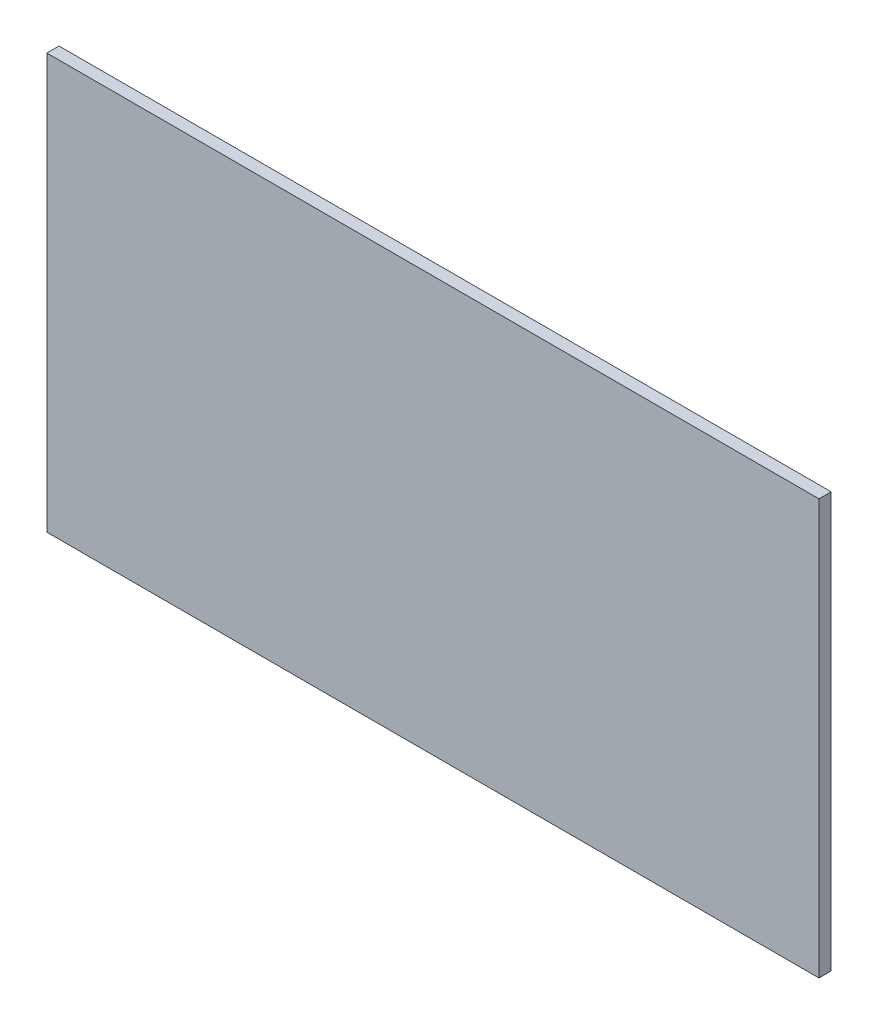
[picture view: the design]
SolidWorks part; units mm, degrees
ref_plane "前视基准面" through (0, 0, 0) normal (0, 0, 1) x (1, 0, 0)
ref_plane "上视基准面" through (0, 0, 0) normal (0, 1, 0) x (1, 0, 0)
ref_plane "右视基准面" through (0, 0, 0) normal (1, 0, 0) x (0, 0, -1)
sketch "草图1" plane through (0, 0, 0) normal (0, 0, 1) x (1, 0, 0)
  line L1 (0, 0) -> (12.6911, 0)
  line L2 (0, 0) -> (0, 6.8209)
  line L3 (0, 6.8209) -> (12.6911, 6.8209)
  line L4 (12.6911, 0) -> (12.6911, 6.8209)
extrude "凸台-拉伸1" add sketch "草图1" along normal blind 0.2
sketch "草图4" plane through (0, 0, 0) normal (0, 0, 1) x (1, 0, 0)
  line B0 (444.903, 426.0047) -> (444.903, 515.0047)
  line B1 (8.903, 515.0084) -> (8.903, 426.0047)
  line B2 (8.903, 426.0047) -> (444.903, 426.0047)
  line B3 (403.403, 506.5047) -> (414.403, 506.5047)
  line B4 (402.903, 492.0047) -> (402.903, 506.0047)
  line B5 (405.403, 491.5047) -> (403.403, 491.5047)
  line B6 (405.903, 503.0047) -> (405.903, 492.0047)
  line B7 (411.403, 503.5047) -> (406.403, 503.5047)
  line B8 (411.903, 492.0047) -> (411.903, 503.0047)
  line B9 (414.403, 491.5047) -> (412.403, 491.5047)
  line B10 (414.903, 506.0047) -> (414.903, 492.0047)
  line B11 (41.403, 491.5047) -> (39.403, 491.5047)
  line B12 (41.903, 503.0047) -> (41.903, 492.0047)
  line B13 (47.403, 503.5047) -> (42.403, 503.5047)
  line B14 (47.903, 492.0047) -> (47.903, 503.0047)
  line B15 (50.403, 491.5047) -> (48.403, 491.5047)
  line B16 (50.903, 506.0047) -> (50.903, 492.0047)
  line B17 (39.403, 506.5047) -> (50.403, 506.5047)
  line B18 (38.903, 492.0047) -> (38.903, 506.0047)
  line B19 (448.903, 515.0047) -> (4.903, 515.0047)
  line B20 (448.903, 525.0047) -> (4.903, 525.0047)
  line B21 (450.903, 525.0047) -> (448.903, 525.0047)
  line B22 (452.903, 523.0047) -> (452.903, 515.0047)
  line B23 (452.903, 515.0047) -> (448.903, 515.0047)
  line B24 (4.903, 525.0047) -> (2.903, 525.0047)
  line B25 (0.903, 523.0047) -> (0.903, 515.0047)
  line B26 (4.903, 515.0047) -> (0.903, 515.0047)
  arc B27 (414.903, 506.0047) -> (414.403, 506.5047) centre (414.403, 506.0047) ccw
  arc B28 (403.403, 506.5047) -> (402.903, 506.0047) centre (403.403, 506.0047) ccw
  arc B29 (402.903, 492.0047) -> (403.403, 491.5047) centre (403.403, 492.0047) ccw
  arc B30 (405.403, 491.5047) -> (405.903, 492.0047) centre (405.403, 492.0047) ccw
  arc B31 (406.403, 503.5047) -> (405.903, 503.0047) centre (406.403, 503.0047) ccw
  arc B32 (411.903, 503.0047) -> (411.403, 503.5047) centre (411.403, 503.0047) ccw
  arc B33 (411.903, 492.0047) -> (412.403, 491.5047) centre (412.403, 492.0047) ccw
  arc B34 (414.403, 491.5047) -> (414.903, 492.0047) centre (414.403, 492.0047) ccw
  arc B35 (38.903, 492.0047) -> (39.403, 491.5047) centre (39.403, 492.0047) ccw
  arc B36 (41.403, 491.5047) -> (41.903, 492.0047) centre (41.403, 492.0047) ccw
  arc B37 (42.403, 503.5047) -> (41.903, 503.0047) centre (42.403, 503.0047) ccw
  arc B38 (47.903, 503.0047) -> (47.403, 503.5047) centre (47.403, 503.0047) ccw
  arc B39 (47.903, 492.0047) -> (48.403, 491.5047) centre (48.403, 492.0047) ccw
  arc B40 (50.403, 491.5047) -> (50.903, 492.0047) centre (50.403, 492.0047) ccw
  arc B41 (50.903, 506.0047) -> (50.403, 506.5047) centre (50.403, 506.0047) ccw
  arc B42 (39.403, 506.5047) -> (38.903, 506.0047) centre (39.403, 506.0047) ccw
  circle B43 centre (55.403, 459.0047) radius 20.5
  circle B44 centre (108.903, 459.0047) radius 13
  circle B45 centre (344.903, 459.0047) radius 13
  circle B46 centre (55.403, 459.0047) radius 16.5
  circle B47 centre (398.403, 459.0047) radius 20.5
  circle B48 centre (398.403, 459.0047) radius 16.5
  arc B49 (452.903, 523.0047) -> (450.903, 525.0047) centre (450.903, 523.0047) ccw
  arc B50 (2.903, 525.0047) -> (0.903, 523.0047) centre (2.903, 523.0047) ccw
  circle B51 centre (309.403, 459.0047) radius 10.5
  circle B52 centre (276.403, 459.0047) radius 10.5
  circle B53 centre (243.403, 459.0047) radius 10.5
  circle B54 centre (210.403, 459.0047) radius 10.5
  circle B55 centre (177.403, 459.0047) radius 10.5
  circle B56 centre (144.403, 459.0047) radius 10.5
  line B57 (1264.4288, 223.2774) -> (1269.0505, 223.2774)
  line B58 (1280.4288, 223.2774) -> (1286.1309, 223.2774)
  line B59 (1288.4288, 223.2774) -> (1294.1309, 223.2774)
  line B60 (1296.4288, 223.2774) -> (1302.1309, 223.2774)
  line B61 (1304.4288, 223.2774) -> (1310.1309, 223.2774)
  line B62 (1312.4288, 223.2774) -> (1318.1309, 223.2774)
  line B63 (1320.4288, 223.2774) -> (1326.1309, 223.2774)
  line B64 (1328.4288, 223.2774) -> (1332.7799, 223.2774)
  line B65 (1332.7799, 223.2774) -> (1332.7799, 216.8774)
  line B66 (1332.7799, 216.8774) -> (1328.4288, 216.8774)
  line B67 (1326.1309, 216.8774) -> (1320.4288, 216.8774)
  line B68 (1318.1309, 216.8774) -> (1312.4288, 216.8774)
  line B69 (1310.1309, 216.8774) -> (1304.4288, 216.8774)
  line B70 (1302.1309, 216.8774) -> (1296.4288, 216.8774)
  line B71 (1294.1309, 216.8774) -> (1288.4288, 216.8774)
  line B72 (1286.1309, 216.8774) -> (1280.4288, 216.8774)
  line B73 (1269.0505, 216.8774) -> (1264.4288, 216.8774)
  line B74 (1273.5092, 223.2774) -> (1278.1309, 223.2774)
  line B75 (1278.1309, 216.8774) -> (1273.5092, 216.8774)
  line B76 (1225.7799, 216.8774) -> (1225.7799, 223.2774)
  line B77 (1225.7799, 223.2774) -> (1230.1309, 223.2774)
  line B78 (1232.4288, 223.2774) -> (1238.1309, 223.2774)
  line B79 (1240.4288, 223.2774) -> (1246.1309, 223.2774)
  line B80 (1248.4288, 223.2774) -> (1253.0505, 223.2774)
  line B81 (1257.5092, 223.2774) -> (1262.1309, 223.2774)
  line B82 (1262.1309, 216.8774) -> (1257.5092, 216.8774)
  line B83 (1253.0505, 216.8774) -> (1248.4288, 216.8774)
  line B84 (1246.1309, 216.8774) -> (1240.4288, 216.8774)
  line B85 (1238.1309, 216.8774) -> (1232.4288, 216.8774)
  line B86 (1230.1309, 216.8774) -> (1225.7799, 216.8774)
  line B87 (1408.1309, 223.1774) -> (1403.5092, 223.1774)
  line B88 (1392.1309, 223.1774) -> (1386.4288, 223.1774)
  line B89 (1384.1309, 223.1774) -> (1378.4288, 223.1774)
  line B90 (1376.1309, 223.1774) -> (1370.4288, 223.1774)
  line B91 (1368.1309, 223.1774) -> (1362.4288, 223.1774)
  line B92 (1360.1309, 223.1774) -> (1354.4288, 223.1774)
  line B93 (1352.1309, 223.1774) -> (1346.4288, 223.1774)
  line B94 (1344.1309, 223.1774) -> (1339.7798, 223.1774)
  line B95 (1339.7798, 223.1774) -> (1339.7798, 216.7774)
  line B96 (1339.7798, 216.7774) -> (1344.1309, 216.7774)
  line B97 (1346.4288, 216.7774) -> (1352.1309, 216.7774)
  line B98 (1354.4288, 216.7774) -> (1360.1309, 216.7774)
  line B99 (1362.4288, 216.7774) -> (1368.1309, 216.7774)
  line B100 (1370.4288, 216.7774) -> (1376.1309, 216.7774)
  line B101 (1378.4288, 216.7774) -> (1384.1309, 216.7774)
  line B102 (1386.4288, 216.7774) -> (1392.1309, 216.7774)
  line B103 (1403.5092, 216.7774) -> (1408.1309, 216.7774)
  line B104 (1399.0505, 223.1774) -> (1394.4288, 223.1774)
  line B105 (1394.4288, 216.7774) -> (1399.0505, 216.7774)
  line B106 (1446.7798, 216.7774) -> (1446.7798, 223.1774)
  line B107 (1446.7798, 223.1774) -> (1442.4288, 223.1774)
  line B108 (1440.1309, 223.1774) -> (1434.4288, 223.1774)
  line B109 (1432.1309, 223.1774) -> (1426.4288, 223.1774)
  line B110 (1424.1309, 223.1774) -> (1419.5092, 223.1774)
  line B111 (1415.0505, 223.1774) -> (1410.4288, 223.1774)
  line B112 (1410.4288, 216.7774) -> (1415.0505, 216.7774)
  line B113 (1419.5092, 216.7774) -> (1424.1309, 216.7774)
  line B114 (1426.4288, 216.7774) -> (1432.1309, 216.7774)
  line B115 (1434.4288, 216.7774) -> (1440.1309, 216.7774)
  line B116 (1442.4288, 216.7774) -> (1446.7798, 216.7774)
  line B117 (1128.2798, 24.8774) -> (1119.2798, 24.8774)
  line B118 (1128.2798, 230.2774) -> (1119.2798, 230.2774)
  line B119 (1129.2799, 24.8774) -> (1128.2798, 24.8774)
  line B120 (1129.2799, 24.8774) -> (1129.2799, 84.5774)
  line B121 (1129.2799, 160.5774) -> (1129.2799, 230.2774)
  line B122 (1129.2799, 230.2774) -> (1128.2798, 230.2774)
  line B123 (1118.2798, 24.8774) -> (1118.2798, 84.5774)
  line B124 (1118.2798, 160.5774) -> (1118.2798, 230.2774)
  line B125 (1119.2798, 24.8774) -> (1118.2798, 24.8774)
  line B126 (1119.2798, 230.2774) -> (1118.2798, 230.2774)
  line B127 (1119.2798, 24.8774) -> (1119.2798, 23.7476)
  line B128 (1118.2798, 24.8774) -> (1118.2798, 22.5774)
  line B129 (1119.2798, 230.2774) -> (1119.2798, 231.4076)
  line B130 (1118.2798, 230.2774) -> (1118.2798, 232.5774)
  line B131 (1130.2799, 160.5774) -> (1130.2799, 230.5774)
  line B132 (1120.0799, 24.5774) -> (1552.4799, 24.5774)
  line B133 (1118.2798, 236.5774) -> (1118.2798, 237.5774)
  line B134 (1118.2798, 237.5774) -> (1554.2799, 237.5774)
  line B135 (1120.0799, 230.5774) -> (1552.4799, 230.5774)
  line B136 (1118.2798, 17.5774) -> (1554.2799, 17.5774)
  line B137 (1118.2798, 17.5774) -> (1118.2798, 18.5774)
  line B138 (1119.1799, 231.5774) -> (1118.2798, 232.5774)
  line B139 (1118.2798, 232.5774) -> (1118.2798, 236.5774)
  line B140 (1118.2798, 18.5774) -> (1118.2798, 22.5774)
  line B141 (1118.2798, 22.5774) -> (1119.1799, 23.5774)
  line B142 (1386.7799, 40.0774) -> (1338.2799, 40.0774)
  line B143 (1334.2799, 40.0774) -> (1285.7799, 40.0774)
  line B144 (1285.7799, 65.0774) -> (1334.2799, 65.0774)
  line B145 (1338.2799, 65.0774) -> (1386.7799, 65.0774)
  line B146 (1285.7799, 190.0774) -> (1334.2799, 190.0774)
  line B147 (1338.2799, 190.0774) -> (1386.7799, 190.0774)
  line B148 (1544.2799, 24.8774) -> (1553.2799, 24.8774)
  line B149 (1544.2799, 230.2774) -> (1553.2799, 230.2774)
  line B150 (1543.2799, 24.8774) -> (1544.2799, 24.8774)
  line B151 (1543.2799, 24.8774) -> (1543.2799, 84.5774)
  line B152 (1543.2798, 160.5774) -> (1543.2798, 230.2774)
  line B153 (1543.2798, 230.2774) -> (1544.2799, 230.2774)
  line B154 (1554.2799, 24.8774) -> (1554.2799, 84.5774)
  line B155 (1554.2799, 160.5774) -> (1554.2799, 230.2774)
  line B156 (1553.2799, 24.8774) -> (1554.2799, 24.8774)
  line B157 (1553.2799, 230.2774) -> (1554.2799, 230.2774)
  line B158 (1553.2799, 24.8774) -> (1553.2799, 23.7476)
  line B159 (1554.2799, 24.8774) -> (1554.2799, 22.5774)
  line B160 (1553.2799, 230.2774) -> (1553.2799, 231.4076)
  line B161 (1554.2799, 230.2774) -> (1554.2799, 232.5774)
  line B162 (1542.2798, 160.5774) -> (1542.2798, 230.5774)
  line B163 (1554.2799, 236.5774) -> (1554.2799, 237.5774)
  line B164 (1554.2799, 17.5774) -> (1554.2799, 18.5774)
  line B165 (1553.3799, 231.5774) -> (1554.2799, 232.5774)
  line B166 (1554.2799, 232.5774) -> (1554.2799, 236.5774)
  line B167 (1554.2799, 18.5774) -> (1554.2799, 22.5774)
  line B168 (1554.2799, 22.5774) -> (1553.3799, 23.5774)
  line B169 (1216.2798, 229.2776) -> (1216.2798, 209.9773)
  line B170 (1456.2798, 209.9773) -> (1456.2798, 229.2774)
  line B171 (1334.5298, 230.2774) -> (1334.5298, 215.9274)
  line B172 (1338.0298, 230.2774) -> (1338.0298, 215.9274)
  line B173 (1334.5298, 224.8938) -> (1216.2799, 224.8938)
  line B174 (1456.2798, 224.8938) -> (1338.0298, 224.8938)
  line B175 (1216.2799, 213.9774) -> (1456.2798, 213.9774)
  line B176 (1456.2798, 215.9274) -> (1325.7798, 215.9274)
  line B177 (1216.2799, 215.9274) -> (1325.7798, 215.9274)
  line B178 (1217.2797, 208.9774) -> (1455.28, 208.9774)
  line B179 (1317.5799, 211.8774) -> (1321.5799, 211.8774)
  line B180 (1317.5799, 212.1774) -> (1317.5799, 211.8774)
  line B181 (1319.4299, 212.1774) -> (1317.5799, 212.1774)
  line B182 (1319.4299, 213.1774) -> (1319.4299, 212.1774)
  line B183 (1319.7299, 213.1774) -> (1319.4299, 213.1774)
  line B184 (1321.5799, 212.1774) -> (1319.7299, 212.1774)
  line B185 (1321.5799, 211.8774) -> (1321.5799, 212.1774)
  line B186 (1319.7299, 212.1774) -> (1319.7299, 213.1774)
  line B187 (1318.8299, 210.7774) -> (1318.8299, 210.4774)
  line B188 (1318.8299, 210.4774) -> (1320.3299, 210.4774)
  line B189 (1320.3299, 210.4774) -> (1320.3299, 210.7774)
  line B190 (1320.3299, 210.7774) -> (1318.8299, 210.7774)
  line B191 (1318.1799, 211.1774) -> (1320.9799, 211.1774)
  line B192 (1320.9799, 211.1774) -> (1320.9799, 211.4774)
  line B193 (1318.1799, 211.4774) -> (1318.1799, 211.1774)
  line B194 (1320.9799, 211.4774) -> (1318.1799, 211.4774)
  line B195 (1439.5791, 212.5037) -> (1439.5791, 210.0827)
  line B196 (1439.5791, 210.0827) -> (1439.9364, 210.0827)
  line B197 (1439.9364, 210.0827) -> (1439.9364, 213.1002)
  line B198 (1439.9364, 213.1002) -> (1439.722, 213.1002)
  line B199 (1438.9897, 212.3985) -> (1438.9897, 212.0652)
  line B200 (1431.5281, 212.5037) -> (1431.5281, 210.0827)
  line B201 (1431.5281, 210.0827) -> (1431.8855, 210.0827)
  line B202 (1431.8855, 210.0827) -> (1431.8855, 213.1002)
  line B203 (1431.8855, 213.1002) -> (1431.6711, 213.1002)
  line B204 (1430.9388, 212.3985) -> (1430.9388, 212.0652)
  line B205 (1423.4772, 212.5037) -> (1423.4772, 210.0827)
  line B206 (1423.4772, 210.0827) -> (1423.8346, 210.0827)
  line B207 (1423.8346, 210.0827) -> (1423.8346, 213.1002)
  line B208 (1423.8346, 213.1002) -> (1423.6201, 213.1002)
  line B209 (1422.8878, 212.3985) -> (1422.8878, 212.0652)
  line B210 (1415.4262, 212.5037) -> (1415.4262, 210.0827)
  line B211 (1415.4262, 210.0827) -> (1415.7836, 210.0827)
  line B212 (1415.7836, 210.0827) -> (1415.7836, 213.1002)
  line B213 (1415.7836, 213.1002) -> (1415.5692, 213.1002)
  line B214 (1414.8369, 212.3985) -> (1414.8369, 212.0652)
  line B215 (1385.1462, 211.9423) -> (1385.8967, 213.1002)
  line B216 (1385.8967, 213.1002) -> (1385.4854, 213.1002)
  line B217 (1385.4854, 213.1002) -> (1384.7531, 211.9774)
  line B218 (1369.5622, 210.7494) -> (1369.5622, 210.0827)
  line B219 (1369.5622, 210.0827) -> (1369.902, 210.0827)
  line B220 (1369.902, 210.0827) -> (1369.902, 210.7494)
  line B221 (1369.902, 210.7494) -> (1370.3309, 210.7494)
  line B222 (1370.3309, 210.7494) -> (1370.3309, 211.0476)
  line B223 (1370.3309, 211.0476) -> (1369.902, 211.0476)
  line B224 (1369.902, 211.0476) -> (1369.902, 213.1002)
  line B225 (1369.902, 213.1002) -> (1369.6337, 213.1002)
  line B226 (1369.6337, 213.1002) -> (1368.1866, 211.0476)
  line B227 (1368.1866, 211.0476) -> (1368.1866, 210.7494)
  line B228 (1368.1866, 210.7494) -> (1369.5622, 210.7494)
  line B229 (1352.2452, 210.1529) -> (1352.2452, 210.0827)
  line B230 (1352.2452, 210.0827) -> (1354.0503, 210.0827)
  line B231 (1354.0503, 210.0827) -> (1354.0503, 210.3985)
  line B232 (1354.0503, 210.3985) -> (1352.7637, 210.3985)
  line B233 (1352.1737, 212.3283) -> (1352.5136, 212.2757)
  line B234 (1230.682, 212.5037) -> (1230.682, 210.0827)
  line B235 (1230.682, 210.0827) -> (1231.0394, 210.0827)
  line B236 (1231.0394, 210.0827) -> (1231.0394, 213.1002)
  line B237 (1231.0394, 213.1002) -> (1230.8249, 213.1002)
  line B238 (1230.0927, 212.3985) -> (1230.0926, 212.0652)
  line B239 (1238.7329, 212.5037) -> (1238.7329, 210.0827)
  line B240 (1238.7329, 210.0827) -> (1239.0903, 210.0827)
  line B241 (1239.0903, 210.0827) -> (1239.0903, 213.1002)
  line B242 (1239.0903, 213.1002) -> (1238.8759, 213.1002)
  line B243 (1238.1436, 212.3985) -> (1238.1436, 212.0652)
  line B244 (1246.7839, 212.5037) -> (1246.7839, 210.0827)
  line B245 (1246.7839, 210.0827) -> (1247.1413, 210.0827)
  line B246 (1247.1413, 210.0827) -> (1247.1413, 213.1002)
  line B247 (1247.1413, 213.1002) -> (1246.9268, 213.1002)
  line B248 (1246.1945, 212.3985) -> (1246.1945, 212.0652)
  line B249 (1254.406, 210.0301) -> (1254.7991, 210.0301)
  line B250 (1270.5436, 210.0827) -> (1270.9367, 210.0827)
  line B251 (1272.0446, 212.7494) -> (1272.0446, 213.0476)
  line B252 (1272.0446, 213.0476) -> (1270.1329, 213.0476)
  line B253 (1270.1329, 213.0476) -> (1270.1329, 212.7318)
  line B254 (1270.1329, 212.7318) -> (1271.6697, 212.7318)
  line B255 (1286.4311, 210.9073) -> (1286.1094, 210.8195)
  line B256 (1286.8066, 212.7318) -> (1287.9502, 212.7318)
  line B257 (1287.9502, 212.7318) -> (1287.9502, 213.0476)
  line B258 (1287.9502, 213.0476) -> (1286.5383, 213.0476)
  line B259 (1286.1991, 211.5388) -> (1286.5025, 211.5038)
  line B260 (1302.3543, 212.3283) -> (1302.6759, 212.2757)
  line B261 (1303.0515, 211.7669) -> (1303.0515, 211.5388)
  line B262 (1302.6402, 210.8897) -> (1302.3185, 210.8371)
  line B263 (1327.2933, 212.5037) -> (1327.2933, 210.0827)
  line B264 (1327.2933, 210.0827) -> (1327.6507, 210.0827)
  line B265 (1327.6507, 210.0827) -> (1327.6507, 213.1002)
  line B266 (1327.6507, 213.1002) -> (1327.4363, 213.1002)
  line B267 (1326.704, 212.3985) -> (1326.704, 212.0652)
  line B268 (1310.4052, 210.1529) -> (1310.4052, 210.0827)
  line B269 (1310.4052, 210.0827) -> (1312.2103, 210.0827)
  line B270 (1312.2103, 210.0827) -> (1312.2103, 210.3985)
  line B271 (1312.2103, 210.3985) -> (1310.9237, 210.3985)
  line B272 (1310.3337, 212.3283) -> (1310.6735, 212.2757)
  line B273 (1295.5184, 210.7494) -> (1295.5184, 210.0827)
  line B274 (1295.5184, 210.0827) -> (1295.8582, 210.0827)
  line B275 (1295.8582, 210.0827) -> (1295.8582, 210.7494)
  line B276 (1295.8582, 210.7494) -> (1296.2871, 210.7494)
  line B277 (1296.2871, 210.7494) -> (1296.2871, 211.0476)
  line B278 (1296.2871, 211.0476) -> (1295.8582, 211.0476)
  line B279 (1295.8582, 211.0476) -> (1295.8582, 213.1002)
  line B280 (1295.8582, 213.1002) -> (1295.5899, 213.1002)
  line B281 (1295.5899, 213.1002) -> (1294.1428, 211.0476)
  line B282 (1294.1428, 211.0476) -> (1294.1428, 210.7494)
  line B283 (1294.1428, 210.7494) -> (1295.5184, 210.7494)
  line B284 (1278.8986, 211.9423) -> (1279.6491, 213.1002)
  line B285 (1279.6491, 213.1002) -> (1279.2378, 213.1002)
  line B286 (1279.2378, 213.1002) -> (1278.5055, 211.9774)
  line B287 (1240.7457, 212.5037) -> (1240.7457, 210.0827)
  line B288 (1240.7457, 210.0827) -> (1241.1031, 210.0827)
  line B289 (1241.1031, 210.0827) -> (1241.1031, 213.1002)
  line B290 (1241.1031, 213.1002) -> (1240.8886, 213.1002)
  line B291 (1240.1563, 212.3985) -> (1240.1563, 212.0652)
  line B292 (1231.9085, 210.1529) -> (1231.9085, 210.0827)
  line B293 (1231.9085, 210.0827) -> (1233.7136, 210.0827)
  line B294 (1233.7136, 210.0827) -> (1233.7136, 210.3985)
  line B295 (1233.7136, 210.3985) -> (1232.427, 210.3985)
  line B296 (1231.837, 212.3283) -> (1232.1769, 212.2757)
  line B297 (1344.9805, 212.5037) -> (1344.9805, 210.0827)
  line B298 (1344.9805, 210.0827) -> (1345.3379, 210.0827)
  line B299 (1345.3379, 210.0827) -> (1345.3379, 213.1002)
  line B300 (1345.3379, 213.1002) -> (1345.1235, 213.1002)
  line B301 (1344.3912, 212.3985) -> (1344.3912, 212.0652)
  line B302 (1360.2962, 212.3283) -> (1360.6178, 212.2757)
  line B303 (1360.9934, 211.7669) -> (1360.9934, 211.5388)
  line B304 (1360.5821, 210.8897) -> (1360.2604, 210.8371)
  line B305 (1376.5767, 210.9073) -> (1376.2551, 210.8195)
  line B306 (1376.9523, 212.7318) -> (1378.0959, 212.7318)
  line B307 (1378.0959, 212.7318) -> (1378.0959, 213.0476)
  line B308 (1378.0959, 213.0476) -> (1376.6839, 213.0476)
  line B309 (1376.3448, 211.5388) -> (1376.6482, 211.5038)
  line B310 (1392.893, 210.0827) -> (1393.2862, 210.0827)
  line B311 (1394.394, 212.7494) -> (1394.394, 213.0476)
  line B312 (1394.394, 213.0476) -> (1392.4824, 213.0476)
  line B313 (1392.4824, 213.0476) -> (1392.4824, 212.7318)
  line B314 (1392.4824, 212.7318) -> (1394.0191, 212.7318)
  line B315 (1408.9592, 210.0301) -> (1409.3523, 210.0301)
  line B316 (1425.4899, 212.5037) -> (1425.4899, 210.0827)
  line B317 (1425.4899, 210.0827) -> (1425.8473, 210.0827)
  line B318 (1425.8473, 210.0827) -> (1425.8473, 213.1002)
  line B319 (1425.8473, 213.1002) -> (1425.6329, 213.1002)
  line B320 (1424.9006, 212.3985) -> (1424.9006, 212.0652)
  line B321 (1432.7546, 210.1529) -> (1432.7546, 210.0827)
  line B322 (1432.7546, 210.0827) -> (1434.5597, 210.0827)
  line B323 (1434.5597, 210.0827) -> (1434.5597, 210.3985)
  line B324 (1434.5597, 210.3985) -> (1433.2732, 210.3985)
  line B325 (1432.6832, 212.3283) -> (1433.023, 212.2757)
  line B326 (1440.8056, 212.3283) -> (1441.1272, 212.2757)
  line B327 (1441.5028, 211.7669) -> (1441.5028, 211.5388)
  line B328 (1441.0915, 210.8897) -> (1440.7698, 210.8371)
  line B329 (1339.2289, 210.5763) -> (1339.8438, 210.5762)
  line B330 (1339.8438, 210.5762) -> (1339.917, 211.058)
  line B331 (1339.917, 211.058) -> (1340.2685, 211.3803)
  line B332 (1340.2685, 211.3803) -> (1340.5756, 210.5763)
  line B333 (1340.5756, 210.5763) -> (1341.3223, 210.5762)
  line B334 (1341.3223, 210.5762) -> (1340.7512, 211.8038)
  line B335 (1340.7512, 211.8038) -> (1341.4687, 212.4472)
  line B336 (1341.4687, 212.4472) -> (1341.4833, 212.4764)
  line B337 (1341.4833, 212.4764) -> (1341.4686, 212.5057)
  line B338 (1341.4686, 212.5057) -> (1341.4392, 212.535)
  line B339 (1341.4392, 212.535) -> (1340.7661, 212.5348)
  line B340 (1340.7661, 212.5348) -> (1340.7366, 212.5201)
  line B341 (1340.7366, 212.5201) -> (1340.0193, 211.7895)
  line B342 (1340.0193, 211.7895) -> (1340.1071, 212.4756)
  line B343 (1340.1071, 212.4756) -> (1340.107, 212.5056)
  line B344 (1340.107, 212.5056) -> (1340.0778, 212.5348)
  line B345 (1340.0778, 212.5348) -> (1339.5362, 212.5348)
  line B346 (1339.5362, 212.5348) -> (1339.5095, 212.5081)
  line B347 (1339.5095, 212.5081) -> (1339.2289, 210.5763)
  line B348 (1342.8593, 210.9415) -> (1342.3173, 210.9852)
  line B349 (1337.6475, 212.4757) -> (1337.6476, 212.5056)
  line B350 (1337.6476, 212.5056) -> (1337.6183, 212.5348)
  line B351 (1337.6183, 212.5348) -> (1337.0766, 212.5348)
  line B352 (1337.0766, 212.5348) -> (1337.0327, 212.491)
  line B353 (1337.0327, 212.491) -> (1336.7702, 210.5756)
  line B354 (1336.7702, 210.5756) -> (1338.2474, 210.5762)
  line B355 (1338.2474, 210.5762) -> (1338.3172, 211.0585)
  line B356 (1338.3172, 211.0585) -> (1337.4428, 211.0584)
  line B357 (1337.4428, 211.0584) -> (1337.6475, 212.4757)
  line B358 (1335.6712, 211.2209) -> (1335.7737, 211.9345)
  line B359 (1335.7737, 211.9345) -> (1335.7736, 211.9648)
  line B360 (1335.7736, 211.9648) -> (1335.7443, 211.994)
  line B361 (1335.7443, 211.994) -> (1335.2612, 211.9939)
  line B362 (1335.2612, 211.9939) -> (1335.2347, 211.9675)
  line B363 (1335.2347, 211.9675) -> (1335.1001, 211.0877)
  line B364 (1335.8764, 210.6347) -> (1336.0082, 210.7372)
  line B365 (1336.0082, 210.7372) -> (1336.0669, 210.7951)
  line B366 (1336.0669, 210.7951) -> (1336.0374, 210.5765)
  line B367 (1336.0374, 210.5765) -> (1336.5496, 210.5762)
  line B368 (1336.5496, 210.5762) -> (1336.7398, 211.9346)
  line B369 (1336.7398, 211.9346) -> (1336.7398, 211.9648)
  line B370 (1336.7398, 211.9648) -> (1336.7107, 211.9938)
  line B371 (1336.7107, 211.9938) -> (1336.2568, 211.994)
  line B372 (1336.2568, 211.994) -> (1336.2128, 211.9794)
  line B373 (1336.2128, 211.9794) -> (1336.1983, 211.9502)
  line B374 (1336.1983, 211.9502) -> (1336.1105, 211.3071)
  line B375 (1339.1995, 211.994) -> (1338.6432, 211.994)
  line B376 (1338.6432, 211.994) -> (1338.4382, 210.5762)
  line B377 (1338.4382, 210.5762) -> (1338.9946, 210.5762)
  line B378 (1338.9946, 210.5762) -> (1339.1995, 211.994)
  line B379 (1339.2578, 212.5345) -> (1338.731, 212.5348)
  line B380 (1338.731, 212.5348) -> (1338.7163, 212.5055)
  line B381 (1338.7163, 212.5055) -> (1338.6724, 212.1986)
  line B382 (1338.6724, 212.1986) -> (1338.6724, 212.184)
  line B383 (1338.6724, 212.184) -> (1338.7017, 212.1695)
  line B384 (1338.7017, 212.1695) -> (1339.1702, 212.1695)
  line B385 (1339.1702, 212.1695) -> (1339.1997, 212.1844)
  line B386 (1339.1997, 212.1844) -> (1339.2145, 212.1992)
  line B387 (1339.2145, 212.1992) -> (1339.2731, 212.5052)
  line B388 (1339.2731, 212.5052) -> (1339.2578, 212.5345)
  line B389 (1331.9085, 212.4753) -> (1332.4796, 211.3948)
  line B390 (1332.4796, 211.3948) -> (1332.3624, 210.5762)
  line B391 (1332.3624, 210.5762) -> (1332.9627, 210.5762)
  line B392 (1332.9627, 210.5762) -> (1333.0798, 211.3947)
  line B393 (1333.0798, 211.3947) -> (1333.9586, 212.4687)
  line B394 (1333.9272, 212.535) -> (1333.3357, 212.5346)
  line B395 (1333.3357, 212.5346) -> (1332.8456, 211.877)
  line B396 (1332.8456, 211.877) -> (1332.5776, 212.4686)
  line B397 (1332.4749, 212.5348) -> (1331.9444, 212.5348)
  line B398 (1329.6099, 212.2426) -> (1329.61, 210.8544)
  line B399 (1329.904, 210.5469) -> (1331.236, 210.5471)
  line B400 (1331.6011, 210.854) -> (1331.6011, 211.4824)
  line B401 (1331.6011, 211.4824) -> (1330.1224, 210.5617)
  line B402 (1330.1224, 210.5617) -> (1331.6011, 211.7457)
  line B403 (1331.6011, 211.7457) -> (1331.601, 211.9502)
  line B404 (1331.601, 211.9502) -> (1330.0931, 210.6789)
  line B405 (1330.0931, 210.6789) -> (1331.6006, 212.2566)
  line B406 (1331.4988, 212.4182) -> (1329.9028, 210.5932)
  line B407 (1329.9028, 210.5932) -> (1329.9028, 212.5344)
  line B408 (1331.235, 212.5494) -> (1330.1225, 212.5494)
  line B409 (1330.1225, 212.5494) -> (1330.1225, 210.947)
  line B410 (1330.1225, 210.947) -> (1331.2702, 212.5435)
  line B411 (1341.8201, 211.1464) -> (1342.9195, 211.1467)
  line B412 (1446.8087, 212.3161) -> (1446.8014, 212.3161)
  line B413 (1446.7036, 211.9572) -> (1446.2689, 210.6774)
  line B414 (1446.2689, 210.6774) -> (1445.8024, 210.6774)
  line B415 (1445.8024, 210.6774) -> (1446.5673, 212.9274)
  line B416 (1446.5673, 212.9274) -> (1447.0908, 212.9274)
  line B417 (1447.0908, 212.9274) -> (1447.5294, 211.5126)
  line B418 (1447.5804, 211.3338) -> (1447.5877, 211.3338)
  line B419 (1447.6678, 211.6447) -> (1448.1039, 212.9274)
  line B420 (1448.1039, 212.9274) -> (1448.5703, 212.9274)
  line B421 (1448.5703, 212.9274) -> (1447.8055, 210.6774)
  line B422 (1447.8055, 210.6774) -> (1447.3137, 210.6774)
  line B423 (1447.3137, 210.6774) -> (1446.8541, 212.133)
  line B424 (1369.5622, 211.0476) -> (1368.5615, 211.0476)
  line B425 (1368.5615, 211.0476) -> (1369.5622, 212.4336)
  line B426 (1369.5622, 212.4336) -> (1369.5622, 211.0476)
  line B427 (1226.0298, 210.7774) -> (1226.0298, 210.4774)
  line B428 (1224.5299, 210.7774) -> (1224.5299, 210.4774)
  line B429 (1224.5299, 210.7774) -> (1226.0298, 210.7774)
  line B430 (1226.0298, 210.4774) -> (1224.5299, 210.4774)
  line B431 (1295.5184, 211.0476) -> (1294.5177, 211.0476)
  line B432 (1294.5177, 211.0476) -> (1295.5184, 212.4336)
  line B433 (1295.5184, 212.4336) -> (1295.5184, 211.0476)
  line B434 (1342.4057, 211.4094) -> (1341.8641, 211.4094)
  line B435 (1226.6799, 211.1774) -> (1223.8798, 211.1774)
  line B436 (1223.8798, 211.4774) -> (1223.8798, 211.1774)
  line B437 (1226.6799, 211.4774) -> (1226.6799, 211.1774)
  line B438 (1223.8798, 211.4774) -> (1226.6799, 211.4774)
  line B439 (1223.2799, 212.1774) -> (1225.1299, 212.1774)
  line B440 (1225.1299, 213.1774) -> (1225.1299, 212.1774)
  line B441 (1223.2799, 211.8774) -> (1223.2799, 212.1774)
  line B442 (1227.2799, 211.8774) -> (1223.2799, 211.8774)
  line B443 (1227.2799, 212.1774) -> (1227.2799, 211.8774)
  line B444 (1225.4299, 212.1774) -> (1227.2799, 212.1774)
  line B445 (1225.1299, 213.1774) -> (1225.4299, 213.1774)
  line B446 (1225.4299, 213.1774) -> (1225.4299, 212.1774)
  line B447 (1217.2798, 230.2774) -> (1455.2798, 230.2774)
  line B448 (1121.4704, 131.5774) -> (1119.161, 127.5774)
  line B449 (1119.161, 127.5774) -> (1121.4704, 123.5774)
  line B450 (1121.4704, 123.5774) -> (1126.0893, 123.5774)
  line B451 (1126.0893, 123.5774) -> (1128.3987, 127.5774)
  line B452 (1128.3987, 127.5774) -> (1126.0893, 131.5774)
  line B453 (1126.0893, 131.5774) -> (1121.4704, 131.5774)
  line B454 (1119.161, 127.5774) -> (1121.4704, 123.5774)
  line B455 (1121.4704, 123.5774) -> (1126.0893, 123.5774)
  line B456 (1126.0893, 123.5774) -> (1128.3987, 127.5774)
  line B457 (1128.3987, 127.5774) -> (1126.0893, 131.5774)
  line B458 (1126.0893, 131.5774) -> (1121.4704, 131.5774)
  line B459 (1121.4704, 131.5774) -> (1119.161, 127.5774)
  line B460 (1121.4704, 123.5774) -> (1126.0893, 123.5774)
  line B461 (1126.0893, 123.5774) -> (1128.3987, 127.5774)
  line B462 (1128.3987, 127.5774) -> (1126.0893, 131.5774)
  line B463 (1126.0893, 131.5774) -> (1121.4704, 131.5774)
  line B464 (1121.4704, 131.5774) -> (1119.161, 127.5774)
  line B465 (1119.161, 127.5774) -> (1121.4704, 123.5774)
  line B466 (1126.0893, 123.5774) -> (1128.3987, 127.5774)
  line B467 (1128.3987, 127.5774) -> (1126.0893, 131.5774)
  line B468 (1126.0893, 131.5774) -> (1121.4704, 131.5774)
  line B469 (1121.4704, 131.5774) -> (1119.161, 127.5774)
  line B470 (1119.161, 127.5774) -> (1121.4704, 123.5774)
  line B471 (1121.4704, 123.5774) -> (1126.0893, 123.5774)
  line B472 (1128.3987, 127.5774) -> (1126.0893, 131.5774)
  line B473 (1126.0893, 131.5774) -> (1121.4704, 131.5774)
  line B474 (1121.4704, 131.5774) -> (1119.161, 127.5774)
  line B475 (1119.161, 127.5774) -> (1121.4704, 123.5774)
  line B476 (1121.4704, 123.5774) -> (1126.0893, 123.5774)
  line B477 (1126.0893, 123.5774) -> (1128.3987, 127.5774)
  line B478 (1126.0893, 131.5774) -> (1121.4704, 131.5774)
  line B479 (1121.4704, 131.5774) -> (1119.161, 127.5774)
  line B480 (1119.161, 127.5774) -> (1121.4704, 123.5774)
  line B481 (1121.4704, 123.5774) -> (1126.0893, 123.5774)
  line B482 (1126.0893, 123.5774) -> (1128.3987, 127.5774)
  line B483 (1128.3987, 127.5774) -> (1126.0893, 131.5774)
  line B484 (1121.9258, 126.8274) -> (1122.8299, 126.8274)
  line B485 (1123.0299, 129.4315) -> (1123.0299, 128.5274)
  line B486 (1124.5299, 129.4315) -> (1124.5299, 128.5274)
  line B487 (1123.0299, 126.6274) -> (1123.0299, 125.7234)
  line B488 (1124.5299, 126.6274) -> (1124.5299, 125.7234)
  line B489 (1122.8299, 128.3274) -> (1121.9258, 128.3274)
  line B490 (1124.7299, 128.3274) -> (1125.6339, 128.3274)
  line B491 (1124.7299, 126.8274) -> (1125.6339, 126.8274)
  line B492 (1546.4704, 131.5774) -> (1544.161, 127.5774)
  line B493 (1544.161, 127.5774) -> (1546.4704, 123.5774)
  line B494 (1546.4704, 123.5774) -> (1551.0893, 123.5774)
  line B495 (1551.0893, 123.5774) -> (1553.3987, 127.5774)
  line B496 (1553.3987, 127.5774) -> (1551.0893, 131.5774)
  line B497 (1551.0893, 131.5774) -> (1546.4704, 131.5774)
  line B498 (1544.161, 127.5774) -> (1546.4704, 123.5774)
  line B499 (1546.4704, 123.5774) -> (1551.0893, 123.5774)
  line B500 (1551.0893, 123.5774) -> (1553.3987, 127.5774)
  line B501 (1553.3987, 127.5774) -> (1551.0893, 131.5774)
  line B502 (1551.0893, 131.5774) -> (1546.4704, 131.5774)
  line B503 (1546.4704, 131.5774) -> (1544.161, 127.5774)
  line B504 (1546.4704, 123.5774) -> (1551.0893, 123.5774)
  line B505 (1551.0893, 123.5774) -> (1553.3987, 127.5774)
  line B506 (1553.3987, 127.5774) -> (1551.0893, 131.5774)
  line B507 (1551.0893, 131.5774) -> (1546.4704, 131.5774)
  line B508 (1546.4704, 131.5774) -> (1544.161, 127.5774)
  line B509 (1544.161, 127.5774) -> (1546.4704, 123.5774)
  line B510 (1551.0893, 123.5774) -> (1553.3987, 127.5774)
  line B511 (1553.3987, 127.5774) -> (1551.0893, 131.5774)
  line B512 (1551.0893, 131.5774) -> (1546.4704, 131.5774)
  line B513 (1546.4704, 131.5774) -> (1544.161, 127.5774)
  line B514 (1544.161, 127.5774) -> (1546.4704, 123.5774)
  line B515 (1546.4704, 123.5774) -> (1551.0893, 123.5774)
  line B516 (1553.3987, 127.5774) -> (1551.0893, 131.5774)
  line B517 (1551.0893, 131.5774) -> (1546.4704, 131.5774)
  line B518 (1546.4704, 131.5774) -> (1544.161, 127.5774)
  line B519 (1544.161, 127.5774) -> (1546.4704, 123.5774)
  line B520 (1546.4704, 123.5774) -> (1551.0893, 123.5774)
  line B521 (1551.0893, 123.5774) -> (1553.3987, 127.5774)
  line B522 (1551.0893, 131.5774) -> (1546.4704, 131.5774)
  line B523 (1546.4704, 131.5774) -> (1544.161, 127.5774)
  line B524 (1544.161, 127.5774) -> (1546.4704, 123.5774)
  line B525 (1546.4704, 123.5774) -> (1551.0893, 123.5774)
  line B526 (1551.0893, 123.5774) -> (1553.3987, 127.5774)
  line B527 (1553.3987, 127.5774) -> (1551.0893, 131.5774)
  line B528 (1546.9258, 126.8274) -> (1547.8299, 126.8274)
  line B529 (1548.0299, 129.4315) -> (1548.0299, 128.5274)
  line B530 (1549.5299, 129.4315) -> (1549.5299, 128.5274)
  line B531 (1548.0299, 126.6274) -> (1548.0299, 125.7234)
  line B532 (1549.5299, 126.6274) -> (1549.5299, 125.7234)
  line B533 (1547.8299, 128.3274) -> (1546.9258, 128.3274)
  line B534 (1549.7299, 128.3274) -> (1550.6339, 128.3274)
  line B535 (1549.7299, 126.8274) -> (1550.6339, 126.8274)
  line B536 (1549.0658, 140.6798) -> (1549.0658, 144.1798)
  line B537 (1549.5366, 140.6798) -> (1549.0658, 140.6798)
  line B538 (1549.5366, 142.0511) -> (1549.5366, 140.6798)
  line B539 (1550.1301, 142.0511) -> (1549.5366, 142.0511)
  line B540 (1549.0658, 144.1798) -> (1550.1301, 144.1798)
  line B541 (1548.5018, 97.263) -> (1550.4396, 97.263)
  line B542 (1546.2514, 90.763) -> (1548.5018, 97.263)
  line B543 (1547.3689, 90.763) -> (1546.2514, 90.763)
  line B544 (1548.3162, 93.4989) -> (1547.3689, 90.763)
  line B545 (1549.0431, 93.4989) -> (1548.3162, 93.4989)
  line B546 (1549.4268, 90.763) -> (1549.0431, 93.4989)
  line B547 (1550.5485, 90.763) -> (1549.4268, 90.763)
  line B548 (1550.1425, 93.6482) -> (1550.5485, 90.763)
  line B549 (1551.2799, 150.0774) -> (1549.7798, 150.0774)
  line B550 (1548.7799, 152.5774) -> (1551.2799, 150.0774)
  line B551 (1546.2798, 150.0774) -> (1548.7799, 152.5774)
  line B552 (1547.7799, 150.0774) -> (1546.2798, 150.0774)
  line B553 (1547.7799, 145.5774) -> (1547.7799, 150.0774)
  line B554 (1549.7798, 145.5774) -> (1547.7799, 145.5774)
  line B555 (1549.7798, 150.0774) -> (1549.7798, 145.5774)
  line B556 (1559.7799, 89.5774) -> (1559.7798, 155.5774)
  line B557 (1554.7799, 84.5774) -> (1540.2799, 84.5774)
  line B558 (1540.2799, 84.5774) -> (1540.2799, 160.5774)
  line B559 (1554.7799, 160.5774) -> (1540.2799, 160.5774)
  line B560 (1554.518, 127.9465) -> (1557.7799, 129.5774)
  line B561 (1557.7799, 125.5774) -> (1554.518, 127.2084)
  line B562 (1556.5799, 127.5774) -> (1557.7799, 125.5774)
  line B563 (1557.7799, 129.5774) -> (1556.5799, 127.5774)
  line B564 (1548.0629, 141.7032) -> (1548.0629, 144.1798)
  line B565 (1546.8758, 144.1798) -> (1546.8758, 141.7032)
  line B566 (1546.405, 144.1798) -> (1546.8758, 144.1798)
  line B567 (1546.405, 141.7032) -> (1546.405, 144.1798)
  line B568 (1548.5336, 144.1798) -> (1548.5336, 141.7032)
  line B569 (1548.0629, 144.1798) -> (1548.5336, 144.1798)
  line B570 (1538.7798, 84.5774) -> (1538.7798, 160.5774)
  line B571 (1540.2799, 160.5774) -> (1538.7798, 160.5774)
  line B572 (1540.2799, 84.5774) -> (1538.7798, 84.5774)
  line B573 (1549.3152, 96.3826) -> (1548.6218, 94.3792)
  line B574 (1549.95, 96.3826) -> (1549.3152, 96.3826)
  line B575 (1548.6218, 94.3792) -> (1549.4784, 94.3792)
  line B576 (1549.5366, 142.44) -> (1550.0073, 142.44)
  line B577 (1550.0073, 143.7909) -> (1549.5366, 143.7909)
  line B578 (1549.5366, 143.7909) -> (1549.5366, 142.44)
  line B579 (1538.7798, 84.5774) -> (1521.2798, 84.5774)
  line B580 (1521.2798, 84.5774) -> (1521.2798, 160.5774)
  line B581 (1538.7798, 160.5774) -> (1521.2798, 160.5774)
  line B582 (1519.7799, 84.5774) -> (1519.7799, 160.5774)
  line B583 (1521.2798, 84.5774) -> (1519.7799, 84.5774)
  line B584 (1521.2798, 160.5774) -> (1519.7799, 160.5774)
  line B585 (1516.2799, 151.5774) -> (1516.2799, 147.5774)
  line B586 (1519.7799, 152.0774) -> (1516.7799, 152.0774)
  line B587 (1516.7799, 147.0774) -> (1519.7799, 147.0774)
  line B588 (1516.2799, 93.5774) -> (1516.2799, 97.5774)
  line B589 (1516.7799, 98.0774) -> (1519.7799, 98.0774)
  line B590 (1519.7799, 93.0774) -> (1516.7799, 93.0774)
  line B591 (1517.2798, 134.3274) -> (1517.2798, 134.3135)
  line B592 (1517.2798, 134.3274) -> (1519.7799, 134.3274)
  line B593 (1518.1846, 132.8274) -> (1519.7799, 132.8274)
  line B594 (1519.7799, 131.8068) -> (1518.2593, 132.4275)
  line B595 (1519.7799, 135.348) -> (1517.2798, 134.3274)
  line B596 (1518.1846, 102.3274) -> (1519.7799, 102.3274)
  line B597 (1519.7799, 103.348) -> (1518.2593, 102.7273)
  line B598 (1517.2798, 100.8274) -> (1519.7799, 100.8274)
  line B599 (1519.7799, 99.8068) -> (1517.2798, 100.8274)
  line B600 (1517.2798, 100.8274) -> (1517.2798, 100.8414)
  line B601 (1516.2799, 95.0346) -> (1516.151, 95.12)
  line B602 (1516.151, 95.12) -> (1515.9434, 95.2793)
  line B603 (1510.2252, 100.0774) -> (1515.9434, 95.2793)
  line B604 (1510.2252, 135.0774) -> (1515.9434, 139.8756)
  line B605 (1519.7799, 140.5774) -> (1517.8718, 140.5774)
  line B606 (1124.0658, 140.6798) -> (1124.0658, 144.1798)
  line B607 (1124.5366, 140.6798) -> (1124.0658, 140.6798)
  line B608 (1124.5366, 142.0511) -> (1124.5366, 140.6798)
  line B609 (1125.1301, 142.0511) -> (1124.5366, 142.0511)
  line B610 (1124.0658, 144.1798) -> (1125.1301, 144.1798)
  line B611 (1124.657, 97.263) -> (1122.7121, 91.6433)
  line B612 (1123.5381, 97.263) -> (1124.657, 97.263)
  line B613 (1121.2877, 90.763) -> (1123.5381, 97.263)
  line B614 (1125.4006, 90.763) -> (1121.2877, 90.763)
  line B615 (1125.7061, 91.6433) -> (1125.4006, 90.763)
  line B616 (1115.9798, 127.5774) -> (1114.7798, 125.5774)
  line B617 (1114.7798, 125.5774) -> (1118.0417, 127.2084)
  line B618 (1118.0417, 127.9465) -> (1114.7798, 129.5774)
  line B619 (1114.7798, 129.5774) -> (1115.9798, 127.5774)
  line B620 (1132.2799, 84.5774) -> (1132.2799, 160.5774)
  line B621 (1117.7799, 84.5774) -> (1132.2799, 84.5774)
  line B622 (1112.7799, 89.5774) -> (1112.7799, 155.5774)
  line B623 (1117.7799, 160.5774) -> (1132.2799, 160.5774)
  line B624 (1122.7799, 145.5774) -> (1124.7798, 145.5774)
  line B625 (1124.7798, 145.5774) -> (1124.7798, 150.0774)
  line B626 (1124.7798, 150.0774) -> (1126.2799, 150.0774)
  line B627 (1126.2799, 150.0774) -> (1123.7798, 152.5774)
  line B628 (1123.7798, 152.5774) -> (1121.2799, 150.0774)
  line B629 (1121.2799, 150.0774) -> (1122.7799, 150.0774)
  line B630 (1122.7799, 150.0774) -> (1122.7799, 145.5774)
  line B631 (1123.0629, 141.7032) -> (1123.0629, 144.1798)
  line B632 (1121.8758, 144.1798) -> (1121.8758, 141.7032)
  line B633 (1121.405, 144.1798) -> (1121.8758, 144.1798)
  line B634 (1121.405, 141.7032) -> (1121.405, 144.1798)
  line B635 (1123.5337, 144.1798) -> (1123.5337, 141.7032)
  line B636 (1123.0629, 144.1798) -> (1123.5337, 144.1798)
  line B637 (1122.7121, 91.6433) -> (1125.7061, 91.6433)
  line B638 (1133.7799, 84.5774) -> (1133.7799, 160.5774)
  line B639 (1132.2799, 160.5774) -> (1133.7799, 160.5774)
  line B640 (1132.2799, 84.5774) -> (1133.7799, 84.5774)
  line B641 (1124.5366, 143.7909) -> (1124.5366, 142.44)
  line B642 (1125.0073, 143.7909) -> (1124.5366, 143.7909)
  line B643 (1124.5366, 142.44) -> (1125.0073, 142.44)
  line B644 (1151.2799, 84.5774) -> (1151.2799, 160.5774)
  line B645 (1133.7799, 84.5774) -> (1151.2799, 84.5774)
  line B646 (1133.7799, 160.5774) -> (1151.2799, 160.5774)
  line B647 (1152.7798, 84.5774) -> (1152.7798, 160.5774)
  line B648 (1151.2799, 84.5774) -> (1152.7798, 84.5774)
  line B649 (1151.2799, 160.5774) -> (1152.7798, 160.5774)
  line B650 (1152.7798, 152.0774) -> (1155.7799, 152.0774)
  line B651 (1156.2799, 151.5774) -> (1156.2798, 147.5774)
  line B652 (1155.7798, 147.0774) -> (1152.7798, 147.0774)
  line B653 (1156.2799, 93.5774) -> (1156.2798, 97.5774)
  line B654 (1155.7799, 98.0774) -> (1152.7798, 98.0774)
  line B655 (1152.7798, 93.0774) -> (1155.7799, 93.0774)
  line B656 (1155.2799, 134.3274) -> (1152.7798, 134.3274)
  line B657 (1155.2799, 134.3274) -> (1155.2799, 134.3135)
  line B658 (1154.3751, 132.8274) -> (1152.7798, 132.8274)
  line B659 (1152.7798, 131.8068) -> (1154.3004, 132.4275)
  line B660 (1152.7798, 135.348) -> (1155.2799, 134.3274)
  line B661 (1155.2799, 100.8274) -> (1152.7798, 100.8274)
  line B662 (1152.7798, 99.8068) -> (1155.2799, 100.8274)
  line B663 (1155.2799, 100.8274) -> (1155.2799, 100.8414)
  line B664 (1154.3751, 102.3274) -> (1152.7798, 102.3274)
  line B665 (1152.7798, 103.348) -> (1154.3004, 102.7273)
  line B666 (1152.7798, 140.5774) -> (1154.6879, 140.5774)
  line B667 (1162.3345, 135.0774) -> (1156.6163, 139.8756)
  line B668 (1162.3345, 100.0774) -> (1156.6163, 95.2793)
  line B669 (1156.2798, 95.0346) -> (1156.4087, 95.12)
  line B670 (1156.4087, 95.12) -> (1156.6163, 95.2793)
  line B671 (1157.2798, 135.0774) -> (1515.2799, 135.0774)
  line B672 (1154.2799, 132.0774) -> (1518.2799, 132.0774)
  line B673 (1154.2799, 130.0774) -> (1518.2799, 130.0774)
  line B674 (1518.2799, 132.0774) -> (1518.2799, 130.0774)
  line B675 (1154.2799, 132.0774) -> (1154.2799, 130.0774)
  line B676 (1154.2799, 103.0774) -> (1518.2799, 103.0774)
  line B677 (1157.2799, 100.0774) -> (1515.2799, 100.0774)
  line B678 (1154.2799, 105.0774) -> (1154.2799, 103.0774)
  line B679 (1154.2799, 105.0774) -> (1518.2799, 105.0774)
  line B680 (1518.2799, 105.0774) -> (1518.2799, 103.0774)
  line B681 (1154.2799, 130.0774) -> (1154.2799, 105.0774)
  line B682 (1518.2799, 130.0774) -> (1518.2799, 105.0774)
  line B683 (1130.7066, 50.1399) -> (1130.213, 55.0149)
  line B684 (1131.7414, 50.1399) -> (1131.2478, 55.0149)
  line B685 (1130.213, 55.0149) -> (1129.6387, 55.5774)
  line B686 (1130.6735, 55.5774) -> (1130.213, 55.0149)
  line B687 (1131.2478, 55.0149) -> (1130.6735, 55.5774)
  line B688 (1131.7082, 55.5774) -> (1131.2478, 55.0149)
  line B689 (1132.3146, 49.5786) -> (1131.7414, 50.1399)
  line B690 (1131.7414, 50.1399) -> (1131.281, 49.5774)
  line B691 (1130.7066, 50.1399) -> (1130.2462, 49.5774)
  line B692 (1131.281, 49.5774) -> (1130.7066, 50.1399)
  line B693 (1130.2462, 49.5774) -> (1129.6387, 55.5774)
  line B694 (1131.281, 49.5774) -> (1130.6735, 55.5774)
  line B695 (1132.3146, 49.5888) -> (1131.7095, 55.5774)
  line B696 (1129.6719, 50.1399) -> (1129.2798, 54.0117)
  line B697 (1129.6387, 55.5774) -> (1129.2798, 55.139)
  line B698 (1130.2462, 49.5774) -> (1129.6719, 50.1399)
  line B699 (1129.6719, 50.1399) -> (1129.2798, 49.661)
  line B700 (1129.2798, 49.661) -> (1129.2114, 49.5774) construction
  line B701 (1133.8122, 50.1399) -> (1133.3186, 55.0149)
  line B702 (1134.847, 50.1399) -> (1134.3534, 55.0149)
  line B703 (1133.3186, 55.0149) -> (1132.7443, 55.5774)
  line B704 (1133.7791, 55.5774) -> (1133.3186, 55.0149)
  line B705 (1134.3534, 55.0149) -> (1133.7791, 55.5774)
  line B706 (1134.8138, 55.5774) -> (1134.3534, 55.0149)
  line B707 (1135.4202, 49.5786) -> (1134.847, 50.1399)
  line B708 (1134.847, 50.1399) -> (1134.3866, 49.5775)
  line B709 (1133.8122, 50.1399) -> (1133.3518, 49.5775)
  line B710 (1134.3866, 49.5775) -> (1133.8122, 50.1399)
  line B711 (1133.3518, 49.5775) -> (1132.7443, 55.5774)
  line B712 (1134.3866, 49.5775) -> (1133.7791, 55.5774)
  line B713 (1135.4202, 49.5888) -> (1134.8151, 55.5774)
  line B714 (1132.2839, 55.0149) -> (1131.7095, 55.5774)
  line B715 (1132.7443, 55.5774) -> (1132.2839, 55.0149)
  line B716 (1133.3518, 49.5775) -> (1132.7775, 50.1399)
  line B717 (1132.7775, 50.1399) -> (1132.317, 49.5774)
  line B718 (1135.3895, 55.0149) -> (1134.8151, 55.5774)
  line B719 (1135.7729, 55.4834) -> (1135.3895, 55.0149)
  line B720 (1135.9902, 50.035) -> (1135.8831, 50.1399)
  line B721 (1135.8831, 50.1399) -> (1135.4226, 49.5775)
  line B722 (1132.2839, 55.0149) -> (1132.7775, 50.1399)
  line B723 (1135.3895, 55.0149) -> (1135.8831, 50.1399)
  line B724 (1137.2798, 54.8712) -> (1137.2798, 50.2836)
  line B725 (1137.2798, 54.8712) -> (1136.2225, 54.9444)
  line B726 (1137.2798, 50.2836) -> (1136.2225, 50.2105)
  line B727 (1135.7729, 55.4834) -> (1136.1345, 51.9124)
  line B728 (1542.2798, 84.5774) -> (1542.2798, 24.5774)
  line B729 (1130.2799, 84.5774) -> (1130.2799, 55.0966)
  line B730 (1130.2799, 49.6185) -> (1130.2799, 24.5774)
  circle B731 centre (1271.2799, 220.0774) radius 3.9
  circle B732 centre (1287.2799, 220.0774) radius 3.4
  circle B733 centre (1295.2799, 220.0774) radius 3.4
  circle B734 centre (1303.2799, 220.0774) radius 3.4
  circle B735 centre (1311.2799, 220.0774) radius 3.4
  circle B736 centre (1327.2799, 220.0774) radius 3.4
  circle B737 centre (1319.2799, 220.0774) radius 3.4
  circle B738 centre (1279.2799, 220.0774) radius 3.4
  circle B739 centre (1263.2799, 220.0774) radius 3.4
  circle B740 centre (1255.2799, 220.0774) radius 3.9
  circle B741 centre (1247.2799, 220.0774) radius 3.4
  circle B742 centre (1401.2798, 219.9774) radius 3.9
  circle B743 centre (1385.2798, 219.9774) radius 3.4
  circle B744 centre (1377.2798, 219.9774) radius 3.4
  circle B745 centre (1369.2798, 219.9774) radius 3.4
  circle B746 centre (1361.2798, 219.9774) radius 3.4
  circle B747 centre (1345.2798, 219.9774) radius 3.4
  circle B748 centre (1353.2798, 219.9774) radius 3.4
  circle B749 centre (1393.2798, 219.9774) radius 3.4
  circle B750 centre (1409.2798, 219.9774) radius 3.4
  circle B751 centre (1417.2798, 219.9774) radius 3.9
  circle B752 centre (1425.2798, 219.9774) radius 3.4
  circle B753 centre (1239.2799, 220.0774) radius 3.4
  circle B754 centre (1433.2798, 219.9774) radius 3.4
  circle B755 centre (1441.2798, 219.9774) radius 3.4
  circle B756 centre (1529.2799, 42.5774) radius 2.5
  circle B757 centre (1143.2799, 42.5774) radius 2.5
  arc B758 (1285.7799, 65.0774) -> (1273.4399, 54.571) centre (1285.7799, 52.5774) ccw
  arc B759 (1273.4399, 50.5838) -> (1273.4399, 54.571) centre (1273.2799, 52.5774) ccw
  arc B760 (1338.2799, 40.0774) -> (1334.2799, 40.0774) centre (1336.2799, 40.0774) ccw
  arc B761 (1399.1199, 54.571) -> (1399.1199, 50.5838) centre (1399.2799, 52.5774) ccw
  arc B762 (1386.7799, 40.0774) -> (1399.1199, 50.5838) centre (1386.7799, 52.5774) ccw
  arc B763 (1273.4399, 50.5838) -> (1285.7799, 40.0774) centre (1285.7799, 52.5774) ccw
  arc B764 (1399.1199, 54.571) -> (1386.7799, 65.0774) centre (1386.7799, 52.5774) ccw
  arc B765 (1334.2799, 65.0774) -> (1338.2799, 65.0774) centre (1336.2799, 65.0774) ccw
  arc B766 (1273.4399, 200.5838) -> (1285.7799, 190.0774) centre (1285.7799, 202.5774) ccw
  arc B767 (1273.4399, 200.5838) -> (1273.4399, 204.571) centre (1273.2799, 202.5774) ccw
  arc B768 (1399.1199, 204.571) -> (1399.1199, 200.5838) centre (1399.2799, 202.5774) ccw
  arc B769 (1399.1199, 204.571) -> (1397.5172, 208.9774) centre (1386.7799, 202.5774) ccw
  arc B770 (1275.0425, 208.9774) -> (1273.4399, 204.571) centre (1285.7799, 202.5774) ccw
  arc B771 (1386.7799, 190.0774) -> (1399.1199, 200.5838) centre (1386.7799, 202.5774) ccw
  arc B772 (1338.2799, 190.0774) -> (1334.2799, 190.0774) centre (1336.2799, 190.0774) ccw
  circle B773 centre (1529.2799, 212.5774) radius 2.5
  circle B774 centre (1143.2799, 212.5774) radius 2.5
  arc B775 (1456.2798, 229.2774) -> (1455.2798, 230.2774) centre (1455.2798, 229.2774) ccw
  arc B776 (1335.1001, 211.0877) -> (1335.1001, 210.8407) centre (1336.6042, 210.9642) ccw
  arc B777 (1335.1001, 210.8407) -> (1335.2314, 210.6201) centre (1335.4755, 210.9147) ccw
  arc B778 (1335.2314, 210.6201) -> (1335.4078, 210.5468) centre (1335.5648, 211.1731) ccw
  arc B779 (1335.4078, 210.5468) -> (1335.5103, 210.5323) centre (1335.5744, 211.3568) ccw
  arc B780 (1335.5103, 210.5323) -> (1335.8764, 210.6347) centre (1335.4489, 211.4582) ccw
  arc B781 (1336.0571, 211.1218) -> (1336.1105, 211.3071) centre (1335.3806, 211.4171) ccw
  arc B782 (1335.9392, 210.997) -> (1336.0571, 211.1218) centre (1335.8072, 211.2398) ccw
  arc B783 (1335.7297, 210.9998) -> (1335.9392, 210.997) centre (1335.8365, 211.1532) ccw
  arc B784 (1335.6709, 211.1026) -> (1335.7297, 210.9998) centre (1335.8651, 211.1454) ccw
  arc B785 (1335.6712, 211.2209) -> (1335.6709, 211.1026) centre (1336.2356, 211.1604) ccw
  arc B786 (1333.8603, 210.5555) -> (1334.6626, 210.6934) centre (1334.0878, 211.6349) ccw
  arc B787 (1334.6626, 210.6934) -> (1335.0037, 211.1517) centre (1334.1095, 211.461) ccw
  arc B788 (1335.0037, 211.1517) -> (1335.0273, 211.5562) centre (1334.1887, 211.4022) ccw
  arc B789 (1335.0273, 211.5562) -> (1334.7498, 211.9358) centre (1334.3932, 211.3838) ccw
  arc B790 (1334.7498, 211.9358) -> (1334.12, 212.0218) centre (1334.2795, 210.8413) ccw
  arc B791 (1334.12, 212.0218) -> (1333.475, 211.5836) centre (1334.3026, 211.0593) ccw
  arc B792 (1333.475, 211.5836) -> (1333.3716, 211.1578) centre (1334.5393, 211.0996) ccw
  arc B793 (1333.3716, 211.1578) -> (1333.8603, 210.5555) centre (1333.9656, 211.1403) ccw
  arc B794 (1333.9586, 212.4687) -> (1333.9272, 212.535) centre (1333.9272, 212.4944) ccw
  arc B795 (1332.5776, 212.4686) -> (1332.4749, 212.5348) centre (1332.4749, 212.4221) ccw
  arc B796 (1331.9444, 212.5348) -> (1331.9085, 212.4753) centre (1331.9444, 212.4942) ccw
  arc B797 (1329.61, 210.8544) -> (1329.904, 210.5469) centre (1329.99, 210.9236) ccw
  arc B798 (1331.236, 210.5471) -> (1331.6011, 210.854) centre (1331.2389, 210.9143) ccw
  arc B799 (1331.6006, 212.2566) -> (1331.4988, 212.4182) centre (1331.1774, 212.1028) ccw
  arc B800 (1329.9028, 212.5344) -> (1329.6099, 212.2426) centre (1329.9701, 212.1739) ccw
  arc B801 (1331.2702, 212.5435) -> (1331.235, 212.5494) centre (1331.1774, 212.1028) ccw
  arc B802 (1334.0445, 210.9267) -> (1334.2665, 210.9272) centre (1334.1547, 211.2385) ccw
  arc B803 (1334.3495, 211.6463) -> (1334.2649, 211.6572) centre (1334.2731, 211.3866) ccw
  arc B804 (1334.5001, 211.4208) -> (1334.3495, 211.6463) centre (1334.277, 211.4349) ccw
  arc B805 (1334.0014, 211.5113) -> (1333.9277, 211.1179) centre (1334.6164, 211.1924) ccw
  arc B806 (1333.9277, 211.1179) -> (1334.0445, 210.9267) centre (1334.1861, 211.1445) ccw
  arc B807 (1334.2665, 210.9272) -> (1334.4355, 211.1257) centre (1334.0405, 211.2909) ccw
  arc B808 (1334.4355, 211.1257) -> (1334.4997, 211.4059) centre (1333.8487, 211.4076) ccw
  arc B809 (1334.2649, 211.6572) -> (1334.0014, 211.5113) centre (1334.2898, 211.3014) ccw
  arc B810 (1334.4997, 211.4059) -> (1334.5001, 211.4208) centre (1333.9323, 211.4262) ccw
  arc B811 (1217.2798, 230.2774) -> (1216.2798, 229.2776) centre (1217.2798, 229.2774) ccw
  circle B812 centre (1231.2799, 220.0774) radius 3.4
  circle B813 centre (1167.2799, 125.5774) radius 1.5
  arc B814 (1120.3906, 122.5439) -> (1120.6186, 122.7744) centre (1119.8029, 123.3529) ccw
  arc B815 (1126.8936, 122.7435) -> (1127.0356, 122.6248) centre (1127.6035, 123.4479) ccw
  arc B816 (1545.5241, 122.6248) -> (1545.6661, 122.7435) centre (1544.9562, 123.4479) ccw
  arc B817 (1551.9411, 122.7744) -> (1552.1691, 122.5439) centre (1552.7568, 123.3529) ccw
  circle B818 centre (1123.7799, 127.5774) radius 3.6
  circle B819 centre (1123.7799, 127.5774) radius 5.75
  arc B820 (1123.0299, 125.7234) -> (1124.5299, 125.7234) centre (1123.7799, 127.5774) ccw
  arc B821 (1124.5299, 128.5274) -> (1124.7299, 128.3274) centre (1124.7299, 128.5274) ccw
  arc B822 (1122.8299, 128.3274) -> (1123.0299, 128.5274) centre (1122.8299, 128.5274) ccw
  arc B823 (1123.0299, 126.6274) -> (1122.8299, 126.8274) centre (1122.8299, 126.6274) ccw
  arc B824 (1124.7299, 126.8274) -> (1124.5299, 126.6274) centre (1124.7299, 126.6274) ccw
  arc B825 (1125.6339, 126.8274) -> (1125.6339, 128.3274) centre (1123.7799, 127.5774) ccw
  arc B826 (1124.5299, 129.4315) -> (1123.0299, 129.4315) centre (1123.7799, 127.5774) ccw
  arc B827 (1121.9258, 128.3274) -> (1121.9258, 126.8274) centre (1123.7799, 127.5774) ccw
  circle B828 centre (1548.7799, 127.5774) radius 3.6
  circle B829 centre (1548.7799, 127.5774) radius 5.75
  arc B830 (1548.0299, 125.7234) -> (1549.5299, 125.7234) centre (1548.7799, 127.5774) ccw
  arc B831 (1549.5299, 128.5274) -> (1549.7299, 128.3274) centre (1549.7299, 128.5274) ccw
  arc B832 (1547.8299, 128.3274) -> (1548.0299, 128.5274) centre (1547.8299, 128.5274) ccw
  arc B833 (1548.0299, 126.6274) -> (1547.8299, 126.8274) centre (1547.8299, 126.6274) ccw
  arc B834 (1549.7299, 126.8274) -> (1549.5299, 126.6274) centre (1549.7299, 126.6274) ccw
  arc B835 (1550.6339, 126.8274) -> (1550.6339, 128.3274) centre (1548.7799, 127.5774) ccw
  arc B836 (1549.5299, 129.4315) -> (1548.0299, 129.4315) centre (1548.7799, 127.5774) ccw
  arc B837 (1546.9258, 128.3274) -> (1546.9258, 126.8274) centre (1548.7799, 127.5774) ccw
  arc B838 (1545.5241, 122.6248) -> (1552.1691, 122.5439) centre (1548.7895, 117.8919) ccw
  arc B839 (1551.4428, 132.6736) -> (1551.2813, 134.9851) centre (1390.2799, 122.5774) ccw
  arc B840 (1551.2813, 134.9851) -> (1545.4984, 134.5395) centre (1548.3899, 134.7623) ccw
  arc B841 (1545.6485, 132.4) -> (1545.4984, 134.5395) centre (1390.2799, 122.5774) ccw
  arc B842 (1559.7798, 155.5774) -> (1554.7799, 160.5774) centre (1554.7798, 155.5774) ccw
  arc B843 (1554.7799, 84.5774) -> (1559.7799, 89.5774) centre (1554.7799, 89.5774) ccw
  circle B844 centre (1527.2799, 117.5774) radius 2.6
  circle B845 centre (1529.2799, 155.5774) radius 2.1
  circle B846 centre (1529.2799, 145.5774) radius 2.1
  circle B847 centre (1527.2799, 117.5774) radius 1.6
  arc B848 (1516.2799, 147.5774) -> (1516.7799, 147.0774) centre (1516.7799, 147.5774) ccw
  arc B849 (1516.7799, 152.0774) -> (1516.2799, 151.5774) centre (1516.7799, 151.5774) ccw
  arc B850 (1516.2799, 93.5774) -> (1516.7799, 93.0774) centre (1516.7799, 93.5774) ccw
  arc B851 (1516.7799, 98.0774) -> (1516.2799, 97.5774) centre (1516.7799, 97.5774) ccw
  arc B852 (1517.8718, 140.5774) -> (1515.9434, 139.8756) centre (1517.8718, 137.5774) ccw
  arc B853 (1112.7799, 89.5774) -> (1117.7799, 84.5774) centre (1117.7799, 89.5774) ccw
  arc B854 (1117.7799, 160.5774) -> (1112.7799, 155.5774) centre (1117.7799, 155.5774) ccw
  arc B855 (1127.0613, 134.5395) -> (1121.2784, 134.9851) centre (1124.1698, 134.7623) ccw
  arc B856 (1121.2784, 134.9851) -> (1121.1169, 132.6736) centre (1282.2799, 122.5774) ccw
  arc B857 (1120.3906, 122.5439) -> (1120.6186, 122.7744) centre (1119.8029, 123.3529) ccw
  arc B858 (1120.3906, 122.5439) -> (1127.0356, 122.6248) centre (1123.7702, 117.8919) ccw
  arc B859 (1126.8936, 122.7435) -> (1127.0356, 122.6248) centre (1127.6035, 123.4479) ccw
  arc B860 (1127.0613, 134.5395) -> (1126.9112, 132.4) centre (1282.2799, 122.5774) ccw
  circle B861 centre (1145.2799, 117.5774) radius 2.6
  circle B862 centre (1143.2799, 155.5774) radius 2.1
  circle B863 centre (1143.2799, 145.5774) radius 2.1
  circle B864 centre (1145.2799, 117.5774) radius 1.6
  arc B865 (1156.2799, 151.5774) -> (1155.7799, 152.0774) centre (1155.7799, 151.5774) ccw
  arc B866 (1155.7798, 147.0774) -> (1156.2798, 147.5774) centre (1155.7798, 147.5774) ccw
  arc B867 (1156.2798, 97.5774) -> (1155.7799, 98.0774) centre (1155.7798, 97.5774) ccw
  arc B868 (1155.7799, 93.0774) -> (1156.2799, 93.5774) centre (1155.7799, 93.5774) ccw
  arc B869 (1156.6163, 139.8756) -> (1154.6879, 140.5774) centre (1154.6879, 137.5774) ccw
  arc B870 (1157.2798, 135.0774) -> (1154.2799, 132.0774) centre (1157.2799, 132.0774) ccw
  arc B871 (1518.2799, 132.0774) -> (1515.2799, 135.0774) centre (1515.2799, 132.0774) ccw
  arc B872 (1154.2799, 103.0774) -> (1157.2799, 100.0774) centre (1157.2799, 103.0774) ccw
  arc B873 (1515.2799, 100.0774) -> (1518.2799, 103.0774) centre (1515.2799, 103.0774) ccw
  circle B874 centre (1505.2799, 125.5774) radius 1.5
  circle B875 centre (1505.2799, 109.5774) radius 1.5
  circle B876 centre (1167.2799, 109.5774) radius 1.5
  arc B877 (1526.7622, 115.6456) -> (1525.348, 117.0598) centre (1527.2799, 117.5774) ccw
  arc B878 (1144.7622, 115.6456) -> (1143.348, 117.0598) centre (1145.2799, 117.5774) ccw
  arc B879 (1135.7831, 55.3827) -> (1136.2354, 54.9435) centre (1136.2612, 55.4226) ccw
  arc B880 (1136.2225, 50.2105) -> (1135.9902, 50.035) centre (1136.2568, 49.9236) ccw
  ellipse B881 centre (1455.2797, 209.9776) end of major axis (1454.5724, 210.6849) minor radius 1 (1455.28, 208.9774) -> (1456.2798, 209.9773) ccw
  ellipse B882 centre (1217.28, 209.9776) end of major axis (1217.9873, 210.6849) minor radius 1 (1216.2798, 209.9773) -> (1217.2797, 208.9774) ccw
  spline B883 degree 3 poles (1119.1799, 23.5774) (1119.2556, 23.7096) (1119.3293, 23.8381) (1119.4806, 24.0823) (1119.5543, 24.1913) (1119.7056, 24.378) (1119.7795, 24.451) (1119.9306, 24.5519) (1120.0041, 24.5774) (1120.0799, 24.5774) knots 0 0 0 0 0.25 0.25 0.5 0.5 0.75 0.75 1 1 1 1
  spline B884 degree 3 poles (1120.0799, 230.5774) (1120.0041, 230.5774) (1119.9304, 230.603) (1119.7791, 230.7042) (1119.7054, 230.7771) (1119.5541, 230.9639) (1119.4802, 231.0731) (1119.3291, 231.317) (1119.2556, 231.4453) (1119.1799, 231.5774) knots 0 0 0 0 0.25 0.25 0.5 0.5 0.75 0.75 1 1 1 1
  spline B885 degree 3 poles (1553.3799, 23.5774) (1553.3041, 23.7096) (1553.2304, 23.8381) (1553.0791, 24.0823) (1553.0054, 24.1913) (1552.8541, 24.378) (1552.7802, 24.451) (1552.6291, 24.5519) (1552.5556, 24.5774) (1552.4799, 24.5774) knots 0 0 0 0 0.25 0.25 0.5 0.5 0.75 0.75 1 1 1 1
  spline B886 degree 3 poles (1552.4799, 230.5774) (1552.5556, 230.5774) (1552.6293, 230.603) (1552.7806, 230.7042) (1552.8543, 230.7771) (1553.0056, 230.9639) (1553.0795, 231.0731) (1553.2306, 231.317) (1553.3041, 231.4453) (1553.3799, 231.5774) knots 0 0 0 0 0.25 0.25 0.5 0.5 0.75 0.75 1 1 1 1
  spline B887 degree 3 poles (1227.7799, 211.7274) (1227.7799, 211.8733) (1227.7545, 212.0382) (1227.6052, 212.3966) (1227.4799, 212.5908) (1227.0799, 212.9641) (1226.8023, 213.1424) (1226.1103, 213.4007) (1225.6965, 213.4774) (1224.8632, 213.4774) (1224.4494, 213.4007) (1223.7574, 213.1424) (1223.4799, 212.9641) (1223.0799, 212.5908) (1222.9545, 212.3966) (1222.8052, 212.0382) (1222.7799, 211.8733) (1222.7799, 211.7274) knots 0 0 0 0 0.125 0.125 0.25 0.25 0.375 0.375 0.5 0.5 0.625 0.625 0.75 0.75 0.875 0.875 1 1 1 1
  spline B888 degree 3 poles (1222.7799, 211.7274) (1222.7799, 211.5816) (1222.8052, 211.4166) (1222.9545, 211.0582) (1223.0799, 210.8641) (1223.4799, 210.4908) (1223.7574, 210.3125) (1224.4494, 210.0541) (1224.8632, 209.9774) (1225.6965, 209.9774) (1226.1103, 210.0541) (1226.8023, 210.3125) (1227.0799, 210.4908) (1227.4799, 210.8641) (1227.6052, 211.0582) (1227.7545, 211.4166) (1227.7799, 211.5816) (1227.7799, 211.7274) knots 0 0 0 0 0.125 0.125 0.25 0.25 0.375 0.375 0.5 0.5 0.625 0.625 0.75 0.75 0.875 0.875 1 1 1 1
  spline B889 degree 3 poles (1449.7799, 211.7274) (1449.7799, 211.8733) (1449.7545, 212.0382) (1449.6052, 212.3966) (1449.4799, 212.5908) (1449.0799, 212.9641) (1448.8023, 213.1424) (1448.1103, 213.4007) (1447.6965, 213.4774) (1446.8632, 213.4774) (1446.4494, 213.4007) (1445.7574, 213.1424) (1445.4799, 212.9641) (1445.0799, 212.5908) (1444.9545, 212.3966) (1444.8052, 212.0382) (1444.7799, 211.8733) (1444.7799, 211.7274) knots 0 0 0 0 0.125 0.125 0.25 0.25 0.375 0.375 0.5 0.5 0.625 0.625 0.75 0.75 0.875 0.875 1 1 1 1
  spline B890 degree 3 poles (1444.7799, 211.7274) (1444.7799, 211.5816) (1444.8052, 211.4166) (1444.9545, 211.0582) (1445.0799, 210.8641) (1445.4799, 210.4908) (1445.7574, 210.3125) (1446.4494, 210.0541) (1446.8632, 209.9774) (1447.6965, 209.9774) (1448.1103, 210.0541) (1448.8023, 210.3125) (1449.0799, 210.4908) (1449.4799, 210.8641) (1449.6052, 211.0582) (1449.7545, 211.4166) (1449.7799, 211.5816) (1449.7799, 211.7274) knots 0 0 0 0 0.125 0.125 0.25 0.25 0.375 0.375 0.5 0.5 0.625 0.625 0.75 0.75 0.875 0.875 1 1 1 1
  spline B891 degree 3 poles (1439.722, 213.1002) (1439.6977, 213.0668) (1439.649, 213.0001) (1439.5697, 212.9042) (1439.4853, 212.8116) (1439.3964, 212.7219) (1439.3025, 212.6356) (1439.2027, 212.5536) (1439.0992, 212.473) (1439.0264, 212.4234) (1438.9897, 212.3985) knots 0 0 0 0 0.121557 0.242856 0.365979 0.489864 0.614317 0.740997 0.869571 1 1 1 1
  spline B892 degree 3 poles (1438.9897, 212.0652) (1439.0471, 212.1) (1439.1584, 212.1678) (1439.3137, 212.2765) (1439.4542, 212.3867) (1439.5382, 212.4655) (1439.5791, 212.5037) knots 0 0 0 0 0.273515 0.530811 0.771994 1 1 1 1
  spline B893 degree 3 poles (1431.6711, 213.1002) (1431.6467, 213.0668) (1431.5981, 213.0001) (1431.5187, 212.9042) (1431.4344, 212.8116) (1431.3454, 212.7219) (1431.2515, 212.6356) (1431.1518, 212.5536) (1431.0483, 212.473) (1430.9755, 212.4234) (1430.9388, 212.3985) knots 0 0 0 0 0.121557 0.242855 0.365979 0.489864 0.614317 0.740997 0.869571 1 1 1 1
  spline B894 degree 3 poles (1430.9388, 212.0652) (1430.9962, 212.1) (1431.1075, 212.1678) (1431.2628, 212.2765) (1431.4032, 212.3867) (1431.4873, 212.4655) (1431.5281, 212.5037) knots 0 0 0 0 0.273515 0.530811 0.771994 1 1 1 1
  spline B895 degree 3 poles (1423.6201, 213.1002) (1423.5958, 213.0668) (1423.5471, 213.0001) (1423.4678, 212.9042) (1423.3834, 212.8116) (1423.2945, 212.7219) (1423.2006, 212.6356) (1423.1008, 212.5536) (1422.9973, 212.473) (1422.9245, 212.4234) (1422.8878, 212.3985) knots 0 0 0 0 0.121557 0.242855 0.365979 0.489864 0.614317 0.740997 0.869571 1 1 1 1
  spline B896 degree 3 poles (1422.8878, 212.0652) (1422.9452, 212.1) (1423.0565, 212.1678) (1423.2118, 212.2765) (1423.3523, 212.3867) (1423.4363, 212.4655) (1423.4772, 212.5037) knots 0 0 0 0 0.273515 0.530811 0.771994 1 1 1 1
  spline B897 degree 3 poles (1415.5692, 213.1002) (1415.5448, 213.0668) (1415.4962, 213.0001) (1415.4168, 212.9042) (1415.3325, 212.8116) (1415.2436, 212.7219) (1415.1496, 212.6356) (1415.0499, 212.5536) (1414.9464, 212.473) (1414.8736, 212.4234) (1414.8369, 212.3985) knots 0 0 0 0 0.121557 0.242855 0.365979 0.489864 0.614317 0.740997 0.869571 1 1 1 1
  spline B898 degree 3 poles (1414.8369, 212.0652) (1414.8943, 212.1) (1415.0056, 212.1678) (1415.1609, 212.2765) (1415.3014, 212.3867) (1415.3854, 212.4655) (1415.4262, 212.5037) knots 0 0 0 0 0.273515 0.530811 0.771994 1 1 1 1
  spline B899 degree 3 poles (1400.4619, 210.9423) (1400.4623, 210.9081) (1400.4631, 210.8415) (1400.4716, 210.7442) (1400.486, 210.6527) (1400.5049, 210.566) (1400.5321, 210.4845) (1400.5693, 210.4084) (1400.6174, 210.3382) (1400.6755, 210.2742) (1400.7416, 210.216) (1400.8169, 210.1664) (1400.8995, 210.1242) (1400.9902, 210.0898) (1401.0888, 210.0622) (1401.1967, 210.0441) (1401.3132, 210.0323) (1401.4352, 210.0289) (1401.5561, 210.0323) (1401.669, 210.0439) (1401.7716, 210.0619) (1401.8627, 210.0897) (1401.9442, 210.1224) (1402.0156, 210.1622) (1402.0794, 210.2057) (1402.1335, 210.2575) (1402.182, 210.3143) (1402.2278, 210.3772) (1402.2706, 210.4469) (1402.3138, 210.5224) (1402.3493, 210.6091) (1402.3745, 210.7087) (1402.3884, 210.8213) (1402.3937, 210.943) (1402.387, 211.0668) (1402.364, 211.185) (1402.3243, 211.2931) (1402.2793, 211.376) (1402.2329, 211.4352) (1402.1932, 211.4769) (1402.1477, 211.5157) (1402.0964, 211.5511) (1402.0397, 211.5837) (1401.9774, 211.6128) (1401.9098, 211.6398) (1401.862, 211.6542) (1401.8374, 211.6616) knots 0 0 0 0 0.025462 0.049558 0.072548 0.094356 0.115448 0.13627 0.157138 0.178584 0.200393 0.222465 0.24545 0.269265 0.294515 0.321504 0.350487 0.381595 0.41222 0.440401 0.465964 0.489512 0.511112 0.531157 0.550241 0.568363 0.586641 0.605782 0.62612 0.647464 0.67044 0.695565 0.723681 0.754639 0.786114 0.815687 0.84382 0.871517 0.885406 0.89965 0.914276 0.929783 0.945949 0.962884 0.980894 1 1 1 1
  spline B900 degree 3 poles (1401.8374, 211.6616) (1401.8647, 211.6751) (1401.9176, 211.7011) (1401.9911, 211.746) (1402.0555, 211.7958) (1402.1129, 211.8485) (1402.1617, 211.9057) (1402.2024, 211.9668) (1402.2354, 212.0314) (1402.2587, 212.0996) (1402.2756, 212.1681) (1402.2892, 212.235) (1402.2965, 212.3) (1402.301, 212.3627) (1402.2998, 212.4232) (1402.2929, 212.4813) (1402.283, 212.5376) (1402.262, 212.6082) (1402.2278, 212.69) (1402.1755, 212.7788) (1402.1113, 212.8552) (1402.0362, 212.9173) (1401.9575, 212.968) (1401.8804, 213.0109) (1401.805, 213.0431) (1401.7309, 213.0662) (1401.6556, 213.0821) (1401.577, 213.0916) (1401.4943, 213.0995) (1401.4083, 213.1008) (1401.3217, 213.0988) (1401.2373, 213.0903) (1401.1564, 213.0765) (1401.0782, 213.0584) (1401.0035, 213.0305) (1400.9314, 212.9946) (1400.8641, 212.9465) (1400.8007, 212.8908) (1400.743, 212.8287) (1400.6914, 212.7641) (1400.6483, 212.6967) (1400.6124, 212.6269) (1400.5843, 212.5526) (1400.5673, 212.4715) (1400.5582, 212.3844) (1400.5587, 212.2928) (1400.5669, 212.2008) (1400.5828, 212.1122) (1400.6072, 212.0291) (1400.6386, 211.9498) (1400.6849, 211.8748) (1400.7485, 211.8042) (1400.8303, 211.7378) (1400.8932, 211.6994) (1400.9264, 211.6792) knots 0 0 0 0 0.021339 0.041329 0.060294 0.078357 0.095927 0.112911 0.129764 0.146681 0.163303 0.179246 0.194551 0.209167 0.223302 0.236911 0.250204 0.263333 0.288534 0.312249 0.335324 0.358185 0.380354 0.400958 0.419953 0.437784 0.455338 0.473884 0.493255 0.513622 0.534145 0.553998 0.573108 0.59172 0.610181 0.628938 0.648034 0.668061 0.688057 0.707422 0.726011 0.744088 0.762406 0.781542 0.802015 0.823744 0.845715 0.866727 0.886828 0.906383 0.926373 0.94833 0.972728 1 1 1 1
  spline B901 degree 3 poles (1400.9264, 211.6792) (1400.9061, 211.6689) (1400.8663, 211.6486) (1400.8103, 211.614) (1400.7591, 211.5769) (1400.7116, 211.538) (1400.6697, 211.4953) (1400.631, 211.4515) (1400.5975, 211.4046) (1400.5593, 211.3397) (1400.5209, 211.2554) (1400.4866, 211.1522) (1400.4655, 211.0476) (1400.4631, 210.9773) (1400.4619, 210.9423) knots 0 0 0 0 0.074163 0.145434 0.214162 0.280285 0.345139 0.408654 0.470329 0.532642 0.653859 0.771212 0.886194 1 1 1 1
  spline B902 degree 3 poles (1384.4139, 211.1093) (1384.4122, 211.0664) (1384.4088, 210.9798) (1384.423, 210.8483) (1384.4507, 210.7153) (1384.4844, 210.6041) (1384.52, 210.5168) (1384.5519, 210.4541) (1384.5891, 210.3953) (1384.6315, 210.3405) (1384.6791, 210.2898) (1384.7313, 210.2427) (1384.7888, 210.1997) (1384.851, 210.1609) (1384.9176, 210.1265) (1384.9874, 210.0965) (1385.061, 210.0726) (1385.1375, 210.0528) (1385.2177, 210.0394) (1385.3013, 210.0312) (1385.3881, 210.027) (1385.4768, 210.0293) (1385.5646, 210.036) (1385.6487, 210.0487) (1385.728, 210.0648) (1385.8021, 210.0881) (1385.8716, 210.1155) (1385.9358, 210.1492) (1385.9953, 210.1873) (1386.066, 210.2453) (1386.1439, 210.3239) (1386.2244, 210.4243) (1386.2887, 210.531) (1386.3367, 210.6428) (1386.3706, 210.7576) (1386.3943, 210.8737) (1386.4066, 210.9912) (1386.4082, 211.1089) (1386.3975, 211.2248) (1386.3773, 211.3374) (1386.3439, 211.4451) (1386.3088, 211.5323) (1386.2711, 211.5983) (1386.2383, 211.6475) (1386.198, 211.6939) (1386.1531, 211.74) (1386.1015, 211.7836) (1386.0448, 211.827) (1385.9816, 211.868) (1385.9139, 211.909) (1385.8396, 211.9444) (1385.7582, 211.9701) (1385.6708, 211.9877) (1385.5774, 211.9966) (1385.4778, 211.9964) (1385.3725, 211.9868) (1385.2609, 211.9693) (1385.1853, 211.9515) (1385.1462, 211.9423) knots 0 0 0 0 0.025119 0.050741 0.077161 0.104644 0.118637 0.132309 0.145822 0.159295 0.172846 0.186499 0.200452 0.214812 0.229393 0.244283 0.259245 0.27469 0.290518 0.306838 0.323852 0.341361 0.358795 0.375335 0.391158 0.406164 0.420791 0.434805 0.448562 0.462093 0.488283 0.513205 0.53733 0.560965 0.584281 0.607317 0.630276 0.653364 0.67616 0.698352 0.720222 0.742108 0.753185 0.76469 0.77666 0.789128 0.80235 0.816202 0.830943 0.84641 0.862526 0.879053 0.896268 0.91462 0.933901 0.954527 0.976487 1 1 1 1
  spline B903 degree 3 poles (1384.7531, 211.9774) (1384.7278, 211.9355) (1384.6797, 211.8558) (1384.6137, 211.7409) (1384.5587, 211.6365) (1384.5112, 211.5405) (1384.4732, 211.4446) (1384.4447, 211.3416) (1384.4249, 211.2288) (1384.4177, 211.1501) (1384.4139, 211.1093) knots 0 0 0 0 0.155661 0.296002 0.421379 0.530722 0.636482 0.748767 0.869802 1 1 1 1
  spline B904 degree 3 poles (1352.7637, 210.3985) (1352.793, 210.4316) (1352.8502, 210.4965) (1352.9345, 210.5921) (1353.014, 210.6851) (1353.0909, 210.7742) (1353.1645, 210.8595) (1353.2329, 210.9427) (1353.2999, 211.0206) (1353.361, 211.0971) (1353.4198, 211.1692) (1353.475, 211.2379) (1353.5263, 211.3035) (1353.574, 211.3658) (1353.617, 211.4254) (1353.6587, 211.48) (1353.6945, 211.5329) (1353.7384, 211.5968) (1353.7874, 211.6732) (1353.8393, 211.7626) (1353.8845, 211.8488) (1353.9228, 211.9316) (1353.9544, 212.0111) (1353.9788, 212.0875) (1353.9956, 212.1608) (1354.0094, 212.252) (1354.0128, 212.3598) (1354.0044, 212.4821) (1353.9781, 212.5947) (1353.9371, 212.6965) (1353.8839, 212.7863) (1353.825, 212.8658) (1353.7587, 212.9333) (1353.6859, 212.9873) (1353.6103, 213.0303) (1353.5357, 213.0655) (1353.4625, 213.093) (1353.3891, 213.1105) (1353.314, 213.121) (1353.2355, 213.1251) (1353.1526, 213.1246) (1353.0962, 213.1201) (1353.0672, 213.1178) knots 0 0 0 0 0.035373 0.069278 0.101977 0.133322 0.163445 0.192123 0.219558 0.245685 0.270458 0.294013 0.316242 0.33715 0.35674 0.375081 0.392153 0.407876 0.437114 0.464767 0.490588 0.515022 0.537749 0.559022 0.579124 0.597879 0.632752 0.665274 0.695719 0.724885 0.752775 0.779021 0.803906 0.828176 0.851399 0.873424 0.8941 0.913904 0.933689 0.9547 0.976718 1 1 1 1
  spline B905 degree 3 poles (1353.0672, 213.1178) (1353.0422, 213.1158) (1352.9929, 213.1119) (1352.9207, 213.099) (1352.8507, 213.0827) (1352.7836, 213.0594) (1352.7186, 213.0319) (1352.6567, 212.998) (1352.5964, 212.9606) (1352.5392, 212.9167) (1352.484, 212.8671) (1352.4323, 212.81) (1352.3818, 212.7472) (1352.3353, 212.6762) (1352.2903, 212.5992) (1352.2492, 212.5148) (1352.209, 212.4245) (1352.1857, 212.3609) (1352.1737, 212.3283) knots 0 0 0 0 0.058881 0.116278 0.172401 0.227846 0.283327 0.338283 0.393714 0.450086 0.507822 0.568061 0.631184 0.69734 0.767451 0.840846 0.918214 1 1 1 1
  spline B906 degree 3 poles (1352.5136, 212.2757) (1352.529, 212.3145) (1352.5587, 212.3895) (1352.6191, 212.4905) (1352.6896, 212.5764) (1352.7704, 212.6454) (1352.8565, 212.6998) (1352.9453, 212.7419) (1353.0366, 212.7709) (1353.1289, 212.7867) (1353.22, 212.7884) (1353.3068, 212.7714) (1353.3885, 212.7394) (1353.4618, 212.6901) (1353.5259, 212.6301) (1353.576, 212.5598) (1353.6127, 212.4826) (1353.6299, 212.4123) (1353.6358, 212.3529) (1353.6365, 212.3055) (1353.6325, 212.2559) (1353.6235, 212.2044) (1353.6122, 212.1504) (1353.5957, 212.0944) (1353.5745, 212.0365) (1353.5498, 211.9754) (1353.5187, 211.9098) (1353.4792, 211.8394) (1353.4331, 211.7619) (1353.3792, 211.6781) (1353.3165, 211.5889) (1353.2467, 211.4928) (1353.1689, 211.3907) (1353.0852, 211.2844) (1353.0004, 211.178) (1352.9165, 211.0777) (1352.837, 210.9842) (1352.7613, 210.8982) (1352.6899, 210.8193) (1352.6222, 210.7482) (1352.5581, 210.6847) (1352.4975, 210.628) (1352.4412, 210.5749) (1352.3933, 210.5194) (1352.3512, 210.4627) (1352.3159, 210.4041) (1352.2877, 210.3435) (1352.2673, 210.2812) (1352.2513, 210.2179) (1352.2473, 210.1746) (1352.2452, 210.1529) knots 0 0 0 0 0.02948 0.056933 0.082798 0.107648 0.131593 0.154596 0.176909 0.1991 0.220526 0.240936 0.261199 0.282082 0.302975 0.322936 0.342721 0.363062 0.373676 0.384849 0.396516 0.408769 0.421767 0.435473 0.449947 0.465322 0.482094 0.501136 0.522343 0.545818 0.571545 0.599371 0.629735 0.662217 0.694986 0.725847 0.754615 0.781724 0.80675 0.829806 0.851125 0.870503 0.888469 0.905716 0.922245 0.938308 0.953988 0.96933 0.984586 1 1 1 1
  spline B907 degree 3 poles (1230.8249, 213.1002) (1230.8006, 213.0668) (1230.7519, 213.0001) (1230.6726, 212.9042) (1230.5882, 212.8116) (1230.4993, 212.7219) (1230.4054, 212.6356) (1230.3056, 212.5536) (1230.2021, 212.473) (1230.1293, 212.4234) (1230.0927, 212.3985) knots 0 0 0 0 0.121557 0.242855 0.365979 0.489864 0.614317 0.740997 0.869571 1 1 1 1
  spline B908 degree 3 poles (1230.0926, 212.0652) (1230.15, 212.1) (1230.2614, 212.1678) (1230.4166, 212.2765) (1230.5571, 212.3867) (1230.6412, 212.4655) (1230.682, 212.5037) knots 0 0 0 0 0.273515 0.530811 0.771994 1 1 1 1
  spline B909 degree 3 poles (1238.8759, 213.1002) (1238.8515, 213.0668) (1238.8029, 213.0001) (1238.7235, 212.9042) (1238.6392, 212.8116) (1238.5502, 212.7219) (1238.4563, 212.6356) (1238.3566, 212.5536) (1238.2531, 212.473) (1238.1803, 212.4234) (1238.1436, 212.3985) knots 0 0 0 0 0.121557 0.242855 0.365979 0.489864 0.614317 0.740997 0.869571 1 1 1 1
  spline B910 degree 3 poles (1238.1436, 212.0652) (1238.201, 212.1) (1238.3123, 212.1678) (1238.4676, 212.2765) (1238.608, 212.3867) (1238.6921, 212.4655) (1238.7329, 212.5037) knots 0 0 0 0 0.273515 0.530811 0.771994 1 1 1 1
  spline B911 degree 3 poles (1246.9268, 213.1002) (1246.9025, 213.0668) (1246.8538, 213.0001) (1246.7745, 212.9042) (1246.6901, 212.8116) (1246.6012, 212.7219) (1246.5073, 212.6356) (1246.4075, 212.5536) (1246.304, 212.473) (1246.2312, 212.4234) (1246.1945, 212.3985) knots 0 0 0 0 0.121557 0.242855 0.365979 0.489864 0.614317 0.740997 0.869571 1 1 1 1
  spline B912 degree 3 poles (1246.1945, 212.0652) (1246.2519, 212.1) (1246.3632, 212.1678) (1246.5185, 212.2765) (1246.659, 212.3867) (1246.743, 212.4655) (1246.7839, 212.5037) knots 0 0 0 0 0.273515 0.530811 0.771994 1 1 1 1
  spline B913 degree 3 number of poles 75 (1254.7991, 210.0301) -> (1255.0492, 211.2055)
  spline B914 degree 3 poles (1255.0492, 211.2055) (1255.0276, 211.1611) (1254.9836, 211.0705) (1254.9152, 210.9327) (1254.8406, 210.7919) (1254.7628, 210.6468) (1254.6802, 210.4981) (1254.5931, 210.3454) (1254.5015, 210.1887) (1254.4381, 210.0835) (1254.406, 210.0301) knots 0 0 0 0 0.110561 0.225453 0.344271 0.467022 0.593952 0.72508 0.860425 1 1 1 1
  spline B915 degree 3 poles (1270.9367, 210.0827) (1270.9609, 210.1941) (1271.0096, 210.4183) (1271.1042, 210.7519) (1271.216, 211.0856) (1271.3464, 211.4191) (1271.4942, 211.7527) (1271.6596, 212.0864) (1271.8426, 212.4201) (1271.9767, 212.6388) (1272.0446, 212.7494) knots 0 0 0 0 0.117755 0.236999 0.358088 0.481311 0.606856 0.734965 0.865975 1 1 1 1
  spline B916 degree 3 poles (1271.6697, 212.7318) (1271.6043, 212.6225) (1271.4749, 212.4058) (1271.2961, 212.0758) (1271.1332, 211.7451) (1270.9846, 211.414) (1270.8512, 211.0824) (1270.7331, 210.7502) (1270.6284, 210.4179) (1270.5718, 210.1941) (1270.5436, 210.0827) knots 0 0 0 0 0.132219 0.261895 0.389489 0.514883 0.638461 0.760417 0.880737 1 1 1 1
  spline B917 degree 3 poles (1286.1094, 210.8195) (1286.1171, 210.7856) (1286.1321, 210.7197) (1286.1627, 210.626) (1286.1958, 210.5392) (1286.2346, 210.4602) (1286.2794, 210.3898) (1286.3275, 210.326) (1286.3806, 210.2697) (1286.4392, 210.2226) (1286.4997, 210.1811) (1286.5613, 210.1446) (1286.624, 210.1134) (1286.6873, 210.0866) (1286.7514, 210.0642) (1286.8168, 210.0483) (1286.8827, 210.0364) (1286.9703, 210.0272) (1287.0771, 210.0256) (1287.2001, 210.0341) (1287.3156, 210.0552) (1287.4227, 210.0895) (1287.5212, 210.133) (1287.6133, 210.1812) (1287.6962, 210.2383) (1287.7727, 210.3006) (1287.8402, 210.3713) (1287.8985, 210.4509) (1287.9483, 210.5392) (1287.9873, 210.6352) (1288.0187, 210.7345) (1288.0429, 210.834) (1288.0592, 210.9323) (1288.0679, 211.0292) (1288.068, 211.1239) (1288.0635, 211.2158) (1288.0508, 211.3044) (1288.0321, 211.3904) (1288.0055, 211.4742) (1287.9728, 211.5577) (1287.9337, 211.6412) (1287.8892, 211.7249) (1287.833, 211.8049) (1287.7601, 211.8751) (1287.674, 211.9377) (1287.5743, 211.9887) (1287.4674, 212.0312) (1287.3561, 212.062) (1287.2432, 212.0842) (1287.1274, 212.094) (1287.0074, 212.0907) (1286.8839, 212.0687) (1286.7555, 212.0324) (1286.6715, 211.9962) (1286.6279, 211.9774) knots 0 0 0 0 0.020599 0.039992 0.058312 0.075639 0.092012 0.107664 0.122909 0.137676 0.152159 0.166307 0.180076 0.193587 0.207015 0.220239 0.233401 0.24669 0.272353 0.296539 0.319637 0.341709 0.362968 0.383344 0.403199 0.422516 0.441662 0.460933 0.480808 0.501512 0.522245 0.542439 0.562074 0.581262 0.599993 0.618111 0.635728 0.652941 0.670145 0.687775 0.706027 0.724743 0.743863 0.763639 0.784399 0.806722 0.829759 0.852421 0.875016 0.897805 0.921166 0.945885 0.971913 1 1 1 1
  spline B918 degree 3 poles (1286.6279, 211.9774) (1286.6353, 212.0019) (1286.6507, 212.0527) (1286.6737, 212.1318) (1286.6955, 212.217) (1286.7175, 212.3083) (1286.7406, 212.4054) (1286.7621, 212.5089) (1286.7854, 212.6181) (1286.7994, 212.6932) (1286.8066, 212.7318) knots 0 0 0 0 0.098849 0.205167 0.318538 0.439221 0.568247 0.704448 0.848199 1 1 1 1
  spline B919 degree 3 poles (1286.5383, 213.0476) (1286.5258, 212.9909) (1286.5017, 212.8807) (1286.4679, 212.7202) (1286.4342, 212.5703) (1286.404, 212.4303) (1286.3751, 212.3007) (1286.3495, 212.1807) (1286.3245, 212.0713) (1286.3026, 211.9718) (1286.2825, 211.8825) (1286.264, 211.8036) (1286.249, 211.7345) (1286.2341, 211.676) (1286.2228, 211.6273) (1286.213, 211.5888) (1286.2053, 211.5605) (1286.2008, 211.5449) (1286.1991, 211.5388) knots 0 0 0 0 0.112653 0.218791 0.318182 0.410647 0.496685 0.575798 0.648575 0.714426 0.773441 0.826031 0.871694 0.910621 0.943026 0.968604 0.987765 1 1 1 1
  spline B920 degree 3 poles (1286.5025, 211.5038) (1286.5146, 211.5194) (1286.5384, 211.5501) (1286.5783, 211.5915) (1286.6202, 211.6292) (1286.665, 211.6621) (1286.7121, 211.6912) (1286.7621, 211.715) (1286.8146, 211.7346) (1286.8862, 211.755) (1286.9755, 211.7704) (1287.0795, 211.7776) (1287.1781, 211.7712) (1287.271, 211.7522) (1287.3571, 211.7185) (1287.4361, 211.6722) (1287.5064, 211.6116) (1287.5687, 211.5398) (1287.6204, 211.4564) (1287.6579, 211.3628) (1287.6829, 211.2609) (1287.6929, 211.1527) (1287.6916, 211.0432) (1287.6796, 210.9368) (1287.6559, 210.8358) (1287.6219, 210.7404) (1287.575, 210.6516) (1287.5138, 210.5717) (1287.4393, 210.5007) (1287.3671, 210.4502) (1287.3031, 210.4154) (1287.2503, 210.3948) (1287.1939, 210.3791) (1287.134, 210.3689) (1287.0705, 210.3635) (1287.0036, 210.3648) (1286.9331, 210.37) (1286.86, 210.3796) (1286.7864, 210.3977) (1286.7178, 210.4319) (1286.6551, 210.4791) (1286.5984, 210.5393) (1286.5466, 210.6121) (1286.5024, 210.6991) (1286.4626, 210.7982) (1286.4419, 210.8698) (1286.4311, 210.9073) knots 0 0 0 0 0.016032 0.0316 0.046691 0.061799 0.076657 0.091699 0.106744 0.122126 0.152176 0.180228 0.206699 0.232255 0.257008 0.281559 0.306292 0.332133 0.358619 0.385628 0.413728 0.443636 0.473748 0.502644 0.530492 0.557841 0.584782 0.611793 0.639317 0.668138 0.683105 0.698441 0.714162 0.730605 0.747743 0.76588 0.784949 0.805219 0.825806 0.846201 0.867085 0.889253 0.913243 0.939469 0.968309 1 1 1 1
  spline B921 degree 3 poles (1302.3185, 210.8371) (1302.325, 210.8058) (1302.3377, 210.7446) (1302.3639, 210.6564) (1302.3953, 210.5738) (1302.4336, 210.4974) (1302.476, 210.4261) (1302.5255, 210.3616) (1302.5793, 210.3019) (1302.6393, 210.249) (1302.703, 210.2015) (1302.7699, 210.1597) (1302.84, 210.1249) (1302.9121, 210.0941) (1302.988, 210.0722) (1303.066, 210.054) (1303.1471, 210.0434) (1303.2301, 210.038) (1303.3133, 210.0394) (1303.3951, 210.0469) (1303.4745, 210.0622) (1303.5523, 210.0831) (1303.627, 210.1132) (1303.7003, 210.1479) (1303.7707, 210.1907) (1303.8382, 210.2397) (1303.9019, 210.2936) (1303.9585, 210.353) (1304.0083, 210.4163) (1304.0506, 210.4837) (1304.0868, 210.5549) (1304.1153, 210.6305) (1304.1367, 210.7104) (1304.1512, 210.7929) (1304.1595, 210.8752) (1304.162, 210.9547) (1304.1599, 211.0301) (1304.1511, 211.1015) (1304.1381, 211.1689) (1304.1182, 211.2322) (1304.093, 211.2912) (1304.0623, 211.3464) (1304.0259, 211.3968) (1303.9873, 211.445) (1303.9447, 211.4898) (1303.8976, 211.5301) (1303.8484, 211.5694) (1303.7941, 211.6032) (1303.737, 211.6348) (1303.6968, 211.6526) (1303.6765, 211.6616) knots 0 0 0 0 0.025876 0.050575 0.074453 0.09736 0.119713 0.141499 0.163105 0.184723 0.206159 0.227431 0.248455 0.269532 0.290786 0.312362 0.334317 0.356989 0.379621 0.401648 0.423426 0.445088 0.466751 0.488561 0.510673 0.53341 0.556052 0.578136 0.599752 0.621117 0.642533 0.664296 0.686466 0.709451 0.73202 0.753432 0.773793 0.793048 0.81166 0.829303 0.84667 0.863554 0.880296 0.897008 0.913509 0.930291 0.947169 0.964443 0.982027 1 1 1 1
  spline B922 degree 3 poles (1303.6765, 211.6616) (1303.7036, 211.6793) (1303.7564, 211.7136) (1303.8292, 211.7693) (1303.8935, 211.8276) (1303.9496, 211.8877) (1303.9969, 211.9508) (1304.0361, 212.0158) (1304.067, 212.0831) (1304.089, 212.1522) (1304.1031, 212.2216) (1304.1142, 212.2899) (1304.1185, 212.3568) (1304.1179, 212.4224) (1304.1125, 212.4867) (1304.1, 212.5495) (1304.0845, 212.6113) (1304.0619, 212.6708) (1304.0359, 212.7282) (1304.0034, 212.7814) (1303.9681, 212.8318) (1303.9271, 212.8775) (1303.8826, 212.9198) (1303.833, 212.9579) (1303.7792, 212.992) (1303.7213, 213.0228) (1303.6598, 213.0483) (1303.5956, 213.0701) (1303.5289, 213.0867) (1303.4597, 213.0994) (1303.388, 213.106) (1303.3138, 213.1097) (1303.237, 213.1073) (1303.1586, 213.1011) (1303.081, 213.0898) (1303.0067, 213.0729) (1302.9362, 213.0509) (1302.8705, 213.0222) (1302.8084, 212.9888) (1302.7508, 212.9498) (1302.6969, 212.9055) (1302.6319, 212.8374) (1302.5569, 212.7431) (1302.4788, 212.6168) (1302.4087, 212.4784) (1302.3727, 212.3792) (1302.3543, 212.3283) knots 0 0 0 0 0.028136 0.054763 0.079725 0.10361 0.126237 0.148227 0.169575 0.190566 0.211203 0.23123 0.250697 0.269554 0.288299 0.306716 0.325239 0.343734 0.36204 0.380052 0.397895 0.415527 0.433401 0.451279 0.469848 0.488827 0.508263 0.527762 0.547793 0.568099 0.588944 0.610461 0.632718 0.6558 0.678867 0.700915 0.722085 0.743031 0.763197 0.783436 0.803523 0.823792 0.865255 0.908208 0.952902 1 1 1 1
  spline B923 degree 3 poles (1302.6759, 212.2757) (1302.6877, 212.3079) (1302.7105, 212.3698) (1302.7511, 212.456) (1302.7944, 212.5326) (1302.8413, 212.5991) (1302.8907, 212.6565) (1302.9437, 212.7037) (1302.9998, 212.7417) (1303.0595, 212.7677) (1303.1193, 212.7866) (1303.1786, 212.7987) (1303.2371, 212.806) (1303.2948, 212.8045) (1303.3519, 212.7996) (1303.4076, 212.7857) (1303.4629, 212.7672) (1303.5163, 212.7417) (1303.5667, 212.712) (1303.6113, 212.6764) (1303.6503, 212.6368) (1303.6819, 212.5918) (1303.7094, 212.5437) (1303.7285, 212.4902) (1303.7421, 212.4329) (1303.7498, 212.3723) (1303.751, 212.3111) (1303.7463, 212.2518) (1303.737, 212.1952) (1303.7205, 212.1418) (1303.6984, 212.0913) (1303.6699, 212.0444) (1303.6369, 211.9995) (1303.5967, 211.9587) (1303.551, 211.9204) (1303.4981, 211.8871) (1303.4392, 211.8569) (1303.3738, 211.8311) (1303.3023, 211.8092) (1303.2243, 211.7912) (1303.1402, 211.7759) (1303.0816, 211.77) (1303.0515, 211.7669) knots 0 0 0 0 0.039409 0.075647 0.109149 0.140173 0.168879 0.195808 0.221446 0.246247 0.270216 0.293316 0.315571 0.337687 0.359421 0.381119 0.403436 0.426223 0.448852 0.470429 0.491516 0.512343 0.533365 0.554829 0.577309 0.600857 0.624716 0.647395 0.669088 0.69039 0.711305 0.732144 0.753265 0.775056 0.797645 0.821563 0.846678 0.873441 0.90205 0.932428 0.965232 1 1 1 1
  spline B924 degree 3 poles (1303.0515, 211.5388) (1303.0816, 211.5343) (1303.1401, 211.5255) (1303.2243, 211.5089) (1303.302, 211.489) (1303.3737, 211.4682) (1303.4387, 211.4433) (1303.4974, 211.4165) (1303.5506, 211.3887) (1303.5964, 211.356) (1303.6375, 211.3217) (1303.6724, 211.2829) (1303.7033, 211.2417) (1303.7297, 211.1972) (1303.7501, 211.149) (1303.7667, 211.0977) (1303.7781, 211.0432) (1303.7853, 210.9863) (1303.7873, 210.9287) (1303.7838, 210.8717) (1303.7764, 210.8161) (1303.7626, 210.7625) (1303.7441, 210.7106) (1303.7215, 210.66) (1303.6926, 210.6116) (1303.6597, 210.5651) (1303.6233, 210.5216) (1303.5825, 210.4837) (1303.5389, 210.4508) (1303.4918, 210.4243) (1303.4419, 210.4026) (1303.389, 210.3862) (1303.333, 210.3759) (1303.2748, 210.3719) (1303.2166, 210.3715) (1303.1598, 210.3766) (1303.1055, 210.3874) (1303.0534, 210.4018) (1303.0043, 210.4226) (1302.9573, 210.4469) (1302.9134, 210.4774) (1302.8584, 210.5241) (1302.7962, 210.591) (1302.7309, 210.6803) (1302.6787, 210.781) (1302.6532, 210.853) (1302.6402, 210.8897) knots 0 0 0 0 0.032802 0.063703 0.092308 0.119076 0.144011 0.167063 0.188548 0.208464 0.227476 0.246118 0.264439 0.282827 0.301619 0.320711 0.340734 0.361406 0.382395 0.402707 0.422715 0.442671 0.462207 0.481922 0.502189 0.522755 0.543258 0.563047 0.582533 0.601845 0.621158 0.640916 0.661306 0.682346 0.703557 0.723921 0.743623 0.763025 0.781941 0.800917 0.81986 0.839378 0.878456 0.917854 0.958097 1 1 1 1
  spline B925 degree 3 poles (1327.4363, 213.1002) (1327.4119, 213.0668) (1327.3632, 213.0001) (1327.2839, 212.9042) (1327.1996, 212.8116) (1327.1106, 212.7219) (1327.0167, 212.6356) (1326.9169, 212.5536) (1326.8134, 212.473) (1326.7406, 212.4234) (1326.704, 212.3985) knots 0 0 0 0 0.121557 0.242855 0.365979 0.489864 0.614317 0.740997 0.869571 1 1 1 1
  spline B926 degree 3 poles (1326.704, 212.0652) (1326.7613, 212.1) (1326.8727, 212.1678) (1327.0279, 212.2765) (1327.1684, 212.3867) (1327.2525, 212.4655) (1327.2933, 212.5037) knots 0 0 0 0 0.273515 0.530811 0.771994 1 1 1 1
  spline B927 degree 3 poles (1310.9237, 210.3985) (1310.953, 210.4316) (1311.0102, 210.4965) (1311.0945, 210.5921) (1311.174, 210.6851) (1311.2508, 210.7742) (1311.3245, 210.8595) (1311.3928, 210.9427) (1311.4598, 211.0206) (1311.521, 211.0971) (1311.5798, 211.1692) (1311.635, 211.2379) (1311.6863, 211.3035) (1311.7339, 211.3658) (1311.777, 211.4254) (1311.8187, 211.48) (1311.8545, 211.5329) (1311.8984, 211.5968) (1311.9474, 211.6732) (1311.9992, 211.7626) (1312.0445, 211.8488) (1312.0828, 211.9316) (1312.1144, 212.0111) (1312.1388, 212.0875) (1312.1556, 212.1608) (1312.1694, 212.252) (1312.1728, 212.3598) (1312.1644, 212.4821) (1312.1381, 212.5947) (1312.0971, 212.6965) (1312.0439, 212.7863) (1311.985, 212.8658) (1311.9187, 212.9333) (1311.8458, 212.9873) (1311.7702, 213.0303) (1311.6957, 213.0655) (1311.6224, 213.093) (1311.549, 213.1105) (1311.4739, 213.121) (1311.3955, 213.1251) (1311.3126, 213.1246) (1311.2562, 213.1201) (1311.2272, 213.1178) knots 0 0 0 0 0.035373 0.069278 0.101977 0.133322 0.163445 0.192123 0.219558 0.245685 0.270458 0.294013 0.316242 0.33715 0.35674 0.375081 0.392153 0.407876 0.437114 0.464767 0.490588 0.515022 0.537749 0.559022 0.579124 0.597879 0.632752 0.665274 0.695719 0.724885 0.752775 0.779021 0.803906 0.828176 0.851399 0.873424 0.8941 0.913904 0.933689 0.9547 0.976718 1 1 1 1
  spline B928 degree 3 poles (1311.2272, 213.1178) (1311.2022, 213.1158) (1311.1529, 213.1119) (1311.0807, 213.099) (1311.0107, 213.0827) (1310.9436, 213.0594) (1310.8786, 213.0319) (1310.8166, 212.998) (1310.7564, 212.9606) (1310.6992, 212.9167) (1310.6439, 212.8671) (1310.5922, 212.81) (1310.5418, 212.7472) (1310.4953, 212.6762) (1310.4503, 212.5992) (1310.4092, 212.5148) (1310.369, 212.4245) (1310.3457, 212.3609) (1310.3337, 212.3283) knots 0 0 0 0 0.058881 0.116278 0.172401 0.227846 0.283327 0.338283 0.393714 0.450086 0.507822 0.568061 0.631184 0.69734 0.767451 0.840846 0.918214 1 1 1 1
  spline B929 degree 3 poles (1310.6735, 212.2757) (1310.689, 212.3145) (1310.7187, 212.3895) (1310.7791, 212.4905) (1310.8496, 212.5764) (1310.9303, 212.6454) (1311.0164, 212.6998) (1311.1052, 212.7419) (1311.1966, 212.7709) (1311.2888, 212.7867) (1311.38, 212.7884) (1311.4668, 212.7714) (1311.5485, 212.7394) (1311.6218, 212.6901) (1311.6859, 212.6301) (1311.736, 212.5598) (1311.7727, 212.4826) (1311.7899, 212.4123) (1311.7957, 212.3529) (1311.7964, 212.3055) (1311.7925, 212.2559) (1311.7834, 212.2044) (1311.7722, 212.1504) (1311.7557, 212.0944) (1311.7345, 212.0365) (1311.7098, 211.9754) (1311.6787, 211.9098) (1311.6392, 211.8394) (1311.593, 211.7619) (1311.5392, 211.6781) (1311.4765, 211.5889) (1311.4067, 211.4928) (1311.3289, 211.3907) (1311.2452, 211.2844) (1311.1604, 211.178) (1311.0765, 211.0777) (1310.997, 210.9842) (1310.9213, 210.8982) (1310.8499, 210.8193) (1310.7822, 210.7482) (1310.718, 210.6847) (1310.6574, 210.628) (1310.6012, 210.5749) (1310.5533, 210.5194) (1310.5112, 210.4627) (1310.4759, 210.4041) (1310.4477, 210.3435) (1310.4272, 210.2812) (1310.4113, 210.2179) (1310.4072, 210.1746) (1310.4052, 210.1529) knots 0 0 0 0 0.02948 0.056933 0.082798 0.107648 0.131593 0.154596 0.176909 0.1991 0.220526 0.240936 0.261199 0.282082 0.302975 0.322936 0.342721 0.363062 0.373676 0.384849 0.396516 0.408769 0.421767 0.435473 0.449947 0.465322 0.482094 0.501136 0.522343 0.545818 0.571545 0.599371 0.629735 0.662217 0.694986 0.725847 0.754615 0.781724 0.80675 0.829806 0.851125 0.870503 0.888469 0.905716 0.922245 0.938308 0.953988 0.96933 0.984586 1 1 1 1
  spline B930 degree 3 poles (1278.1663, 211.1093) (1278.1646, 211.0664) (1278.1612, 210.9798) (1278.1755, 210.8483) (1278.2031, 210.7153) (1278.2369, 210.6041) (1278.2724, 210.5168) (1278.3043, 210.4541) (1278.3415, 210.3953) (1278.3839, 210.3405) (1278.4316, 210.2898) (1278.4838, 210.2427) (1278.5413, 210.1997) (1278.6035, 210.1609) (1278.67, 210.1265) (1278.7398, 210.0965) (1278.8134, 210.0726) (1278.8899, 210.0528) (1278.9702, 210.0394) (1279.0538, 210.0312) (1279.1405, 210.027) (1279.2293, 210.0293) (1279.317, 210.036) (1279.4011, 210.0487) (1279.4805, 210.0648) (1279.5546, 210.0881) (1279.624, 210.1155) (1279.6882, 210.1492) (1279.7477, 210.1873) (1279.8185, 210.2453) (1279.8963, 210.3239) (1279.9768, 210.4243) (1280.0411, 210.531) (1280.0891, 210.6428) (1280.123, 210.7576) (1280.1468, 210.8737) (1280.159, 210.9912) (1280.1606, 211.1089) (1280.1499, 211.2248) (1280.1298, 211.3374) (1280.0963, 211.4451) (1280.0613, 211.5323) (1280.0236, 211.5983) (1279.9908, 211.6475) (1279.9505, 211.6939) (1279.9056, 211.74) (1279.854, 211.7836) (1279.7972, 211.827) (1279.734, 211.868) (1279.6664, 211.909) (1279.592, 211.9444) (1279.5106, 211.9701) (1279.4233, 211.9877) (1279.3299, 211.9966) (1279.2302, 211.9964) (1279.1249, 211.9868) (1279.0133, 211.9693) (1278.9377, 211.9515) (1278.8986, 211.9423) knots 0 0 0 0 0.025119 0.050741 0.077161 0.104644 0.118637 0.132309 0.145822 0.159295 0.172846 0.186499 0.200452 0.214812 0.229393 0.244283 0.259245 0.27469 0.290518 0.306838 0.323852 0.341361 0.358795 0.375335 0.391158 0.406164 0.420791 0.434805 0.448562 0.462093 0.488283 0.513205 0.53733 0.560965 0.584281 0.607317 0.630276 0.653364 0.67616 0.698352 0.720222 0.742108 0.753185 0.76469 0.77666 0.789128 0.80235 0.816202 0.830943 0.84641 0.862526 0.879053 0.896268 0.91462 0.933901 0.954527 0.976487 1 1 1 1
  spline B931 degree 3 poles (1278.5055, 211.9774) (1278.4802, 211.9355) (1278.4322, 211.8558) (1278.3661, 211.7409) (1278.3112, 211.6365) (1278.2636, 211.5405) (1278.2257, 211.4446) (1278.1971, 211.3416) (1278.1773, 211.2288) (1278.1701, 211.1501) (1278.1663, 211.1093) knots 0 0 0 0 0.155661 0.296002 0.421379 0.530722 0.636482 0.748767 0.869802 1 1 1 1
  spline B932 degree 3 poles (1262.0105, 210.9423) (1262.0109, 210.9081) (1262.0118, 210.8415) (1262.0203, 210.7442) (1262.0347, 210.6527) (1262.0536, 210.566) (1262.0808, 210.4845) (1262.1179, 210.4084) (1262.1661, 210.3382) (1262.2241, 210.2742) (1262.2903, 210.216) (1262.3655, 210.1664) (1262.4481, 210.1242) (1262.5389, 210.0898) (1262.6375, 210.0622) (1262.7453, 210.0441) (1262.8619, 210.0323) (1262.9839, 210.0289) (1263.1048, 210.0323) (1263.2177, 210.0439) (1263.3202, 210.0619) (1263.4113, 210.0897) (1263.4928, 210.1224) (1263.5643, 210.1622) (1263.6281, 210.2057) (1263.6821, 210.2575) (1263.7306, 210.3143) (1263.7764, 210.3772) (1263.8192, 210.4469) (1263.8625, 210.5224) (1263.8979, 210.6091) (1263.9232, 210.7087) (1263.937, 210.8213) (1263.9424, 210.943) (1263.9357, 211.0668) (1263.9127, 211.185) (1263.8729, 211.2931) (1263.8279, 211.376) (1263.7815, 211.4352) (1263.7418, 211.4769) (1263.6964, 211.5157) (1263.6451, 211.5511) (1263.5883, 211.5837) (1263.526, 211.6128) (1263.4585, 211.6398) (1263.4107, 211.6542) (1263.3861, 211.6616) knots 0 0 0 0 0.025462 0.049558 0.072548 0.094356 0.115448 0.13627 0.157138 0.178584 0.200393 0.222465 0.24545 0.269265 0.294515 0.321504 0.350487 0.381595 0.41222 0.440401 0.465964 0.489512 0.511112 0.531157 0.550241 0.568363 0.586641 0.605782 0.62612 0.647464 0.67044 0.695565 0.723681 0.754639 0.786114 0.815687 0.84382 0.871517 0.885406 0.89965 0.914276 0.929783 0.945949 0.962884 0.980894 1 1 1 1
  spline B933 degree 3 poles (1263.3861, 211.6616) (1263.4134, 211.6751) (1263.4662, 211.7011) (1263.5398, 211.746) (1263.6041, 211.7958) (1263.6616, 211.8485) (1263.7103, 211.9057) (1263.7511, 211.9668) (1263.7841, 212.0314) (1263.8074, 212.0996) (1263.8243, 212.1681) (1263.8379, 212.235) (1263.8452, 212.3) (1263.8496, 212.3627) (1263.8485, 212.4232) (1263.8415, 212.4813) (1263.8316, 212.5376) (1263.8107, 212.6082) (1263.7764, 212.69) (1263.7242, 212.7788) (1263.66, 212.8552) (1263.5848, 212.9173) (1263.5061, 212.968) (1263.4291, 213.0109) (1263.3537, 213.0431) (1263.2796, 213.0662) (1263.2042, 213.0821) (1263.1257, 213.0916) (1263.043, 213.0995) (1262.957, 213.1008) (1262.8704, 213.0988) (1262.786, 213.0903) (1262.705, 213.0765) (1262.6269, 213.0584) (1262.5521, 213.0305) (1262.4801, 212.9946) (1262.4127, 212.9465) (1262.3494, 212.8908) (1262.2917, 212.8287) (1262.24, 212.7641) (1262.1969, 212.6967) (1262.1611, 212.6269) (1262.1329, 212.5526) (1262.116, 212.4715) (1262.1069, 212.3844) (1262.1073, 212.2928) (1262.1155, 212.2008) (1262.1315, 212.1122) (1262.1559, 212.0291) (1262.1872, 211.9498) (1262.2336, 211.8748) (1262.2972, 211.8042) (1262.3789, 211.7378) (1262.4419, 211.6994) (1262.4751, 211.6792) knots 0 0 0 0 0.021339 0.041329 0.060294 0.078357 0.095927 0.112911 0.129764 0.146681 0.163303 0.179246 0.194551 0.209167 0.223302 0.236911 0.250204 0.263333 0.288534 0.312249 0.335324 0.358185 0.380354 0.400958 0.419953 0.437784 0.455338 0.473884 0.493255 0.513622 0.534145 0.553998 0.573108 0.59172 0.610181 0.628938 0.648034 0.668061 0.688057 0.707422 0.726011 0.744088 0.762406 0.781542 0.802015 0.823744 0.845715 0.866727 0.886828 0.906383 0.926373 0.94833 0.972728 1 1 1 1
  spline B934 degree 3 poles (1262.4751, 211.6792) (1262.4548, 211.6689) (1262.415, 211.6486) (1262.359, 211.614) (1262.3077, 211.5769) (1262.2602, 211.538) (1262.2183, 211.4953) (1262.1797, 211.4515) (1262.1461, 211.4046) (1262.108, 211.3397) (1262.0696, 211.2554) (1262.0352, 211.1522) (1262.0142, 211.0476) (1262.0117, 210.9773) (1262.0105, 210.9423) knots 0 0 0 0 0.074163 0.145434 0.214162 0.280285 0.345139 0.408654 0.470329 0.532642 0.653859 0.771212 0.886194 1 1 1 1
  spline B935 degree 3 poles (1249.8447, 211.3925) (1249.8474, 211.4551) (1249.8509, 211.5938) (1249.8462, 211.8042) (1249.8301, 212.019) (1249.8051, 212.1885) (1249.7784, 212.3167) (1249.7529, 212.4072) (1249.7226, 212.4937) (1249.6863, 212.5759) (1249.6467, 212.6546) (1249.6005, 212.7285) (1249.5501, 212.7986) (1249.495, 212.864) (1249.4366, 212.9239) (1249.3738, 212.9751) (1249.3092, 213.0192) (1249.2419, 213.0552) (1249.1722, 213.0832) (1249.1, 213.1038) (1249.0251, 213.1153) (1248.9487, 213.1188) (1248.8728, 213.1163) (1248.799, 213.1076) (1248.7282, 213.0945) (1248.6609, 213.0743) (1248.5959, 213.0508) (1248.5345, 213.0201) (1248.4762, 212.9839) (1248.4027, 212.9292) (1248.3181, 212.8508) (1248.2293, 212.7438) (1248.1521, 212.6253) (1248.0985, 212.5171) (1248.0624, 212.4231) (1248.0378, 212.3459) (1248.0165, 212.2625) (1247.9983, 212.1734) (1247.9836, 212.0782) (1247.9712, 211.977) (1247.9622, 211.8697) (1247.9586, 211.7962) (1247.9571, 211.7585) knots 0 0 0 0 0.023197 0.051343 0.07788 0.102846 0.114733 0.126306 0.137615 0.148637 0.159536 0.170192 0.180873 0.191455 0.201829 0.211796 0.221379 0.23074 0.239985 0.249147 0.258479 0.267951 0.277416 0.286534 0.295433 0.304034 0.312507 0.321004 0.329391 0.337873 0.354893 0.371911 0.389233 0.407123 0.416488 0.426502 0.437099 0.448309 0.460158 0.472757 0.486032 0.5 0.5 0.5 0.5
  spline B936 degree 3 poles (1247.9571, 211.7585) (1247.9557, 211.7208) (1247.9537, 211.6474) (1247.952, 211.5401) (1247.9535, 211.4387) (1247.9567, 211.3434) (1247.9616, 211.2543) (1247.9694, 211.1713) (1247.9797, 211.0944) (1247.9962, 210.9998) (1248.0224, 210.8869) (1248.0628, 210.7557) (1248.1118, 210.6275) (1248.1599, 210.5237) (1248.2045, 210.4431) (1248.2443, 210.3858) (1248.29, 210.332) (1248.3409, 210.2808) (1248.3979, 210.2336) (1248.4596, 210.1884) (1248.5277, 210.1471) (1248.5999, 210.1084) (1248.675, 210.0753) (1248.7512, 210.0506) (1248.8273, 210.0336) (1248.9037, 210.027) (1248.9802, 210.0271) (1249.0565, 210.0375) (1249.1331, 210.0547) (1249.2085, 210.0816) (1249.2814, 210.1153) (1249.3509, 210.1546) (1249.4145, 210.2016) (1249.4749, 210.2527) (1249.5297, 210.3109) (1249.5787, 210.3758) (1249.6249, 210.4454) (1249.6649, 210.5218) (1249.7004, 210.6042) (1249.7331, 210.6916) (1249.7607, 210.7854) (1249.7856, 210.8843) (1249.8056, 210.9896) (1249.8214, 211.1004) (1249.8348, 211.217) (1249.8411, 211.315) (1249.844, 211.3741) (1249.8447, 211.3925) knots 0.5 0.5 0.5 0.5 0.513955 0.527184 0.539691 0.551482 0.562484 0.572711 0.582337 0.591207 0.608242 0.625181 0.642005 0.659005 0.667477 0.676061 0.684765 0.693608 0.702713 0.712126 0.721915 0.732172 0.742404 0.752266 0.761779 0.7712 0.78058 0.790036 0.799663 0.809601 0.819574 0.829378 0.83908 0.848801 0.858612 0.868618 0.878868 0.889483 0.900505 0.912046 0.924017 0.936655 0.9498 0.963654 0.978093 0.993201 1 1 1 1
  spline B937 degree 3 poles (1240.8886, 213.1002) (1240.8643, 213.0668) (1240.8156, 213.0001) (1240.7363, 212.9042) (1240.6519, 212.8116) (1240.563, 212.7219) (1240.4691, 212.6356) (1240.3693, 212.5536) (1240.2658, 212.473) (1240.193, 212.4234) (1240.1563, 212.3985) knots 0 0 0 0 0.121557 0.242856 0.365979 0.489864 0.614317 0.740997 0.869571 1 1 1 1
  spline B938 degree 3 poles (1240.1563, 212.0652) (1240.2137, 212.1) (1240.325, 212.1678) (1240.4803, 212.2765) (1240.6208, 212.3867) (1240.7048, 212.4655) (1240.7457, 212.5037) knots 0 0 0 0 0.273515 0.530811 0.771994 1 1 1 1
  spline B939 degree 3 poles (1232.427, 210.3985) (1232.4563, 210.4316) (1232.5135, 210.4965) (1232.5978, 210.5921) (1232.6773, 210.6851) (1232.7542, 210.7742) (1232.8278, 210.8595) (1232.8962, 210.9427) (1232.9632, 211.0206) (1233.0243, 211.0971) (1233.0831, 211.1692) (1233.1383, 211.2379) (1233.1896, 211.3035) (1233.2372, 211.3658) (1233.2803, 211.4254) (1233.322, 211.48) (1233.3578, 211.5329) (1233.4017, 211.5968) (1233.4507, 211.6732) (1233.5026, 211.7626) (1233.5478, 211.8488) (1233.5861, 211.9316) (1233.6177, 212.0111) (1233.6421, 212.0875) (1233.6589, 212.1608) (1233.6727, 212.252) (1233.6761, 212.3598) (1233.6677, 212.4821) (1233.6414, 212.5947) (1233.6004, 212.6965) (1233.5472, 212.7863) (1233.4883, 212.8658) (1233.422, 212.9333) (1233.3492, 212.9873) (1233.2735, 213.0303) (1233.199, 213.0655) (1233.1257, 213.093) (1233.0523, 213.1105) (1232.9773, 213.121) (1232.8988, 213.1251) (1232.8159, 213.1246) (1232.7595, 213.1201) (1232.7305, 213.1178) knots 0 0 0 0 0.035373 0.069278 0.101977 0.133322 0.163445 0.192123 0.219558 0.245685 0.270458 0.294013 0.316242 0.33715 0.35674 0.375081 0.392153 0.407876 0.437114 0.464767 0.490588 0.515022 0.537749 0.559022 0.579124 0.597879 0.632752 0.665274 0.695719 0.724885 0.752775 0.779021 0.803906 0.828176 0.851399 0.873424 0.8941 0.913904 0.933689 0.9547 0.976718 1 1 1 1
  spline B940 degree 3 poles (1232.7305, 213.1178) (1232.7055, 213.1158) (1232.6562, 213.1119) (1232.584, 213.099) (1232.514, 213.0827) (1232.4469, 213.0594) (1232.3819, 213.0319) (1232.32, 212.998) (1232.2597, 212.9606) (1232.2025, 212.9167) (1232.1472, 212.8671) (1232.0956, 212.81) (1232.0451, 212.7472) (1231.9986, 212.6762) (1231.9536, 212.5992) (1231.9125, 212.5148) (1231.8723, 212.4245) (1231.849, 212.3609) (1231.837, 212.3283) knots 0 0 0 0 0.058881 0.116278 0.172401 0.227846 0.283327 0.338283 0.393714 0.450086 0.507822 0.568061 0.631184 0.69734 0.767451 0.840846 0.918214 1 1 1 1
  spline B941 degree 3 poles (1232.1769, 212.2757) (1232.1923, 212.3145) (1232.222, 212.3895) (1232.2824, 212.4905) (1232.3529, 212.5764) (1232.4337, 212.6454) (1232.5198, 212.6998) (1232.6085, 212.7419) (1232.6999, 212.7709) (1232.7922, 212.7867) (1232.8833, 212.7884) (1232.9701, 212.7714) (1233.0518, 212.7394) (1233.1251, 212.6901) (1233.1892, 212.6301) (1233.2393, 212.5598) (1233.276, 212.4826) (1233.2932, 212.4123) (1233.2991, 212.3529) (1233.2998, 212.3055) (1233.2958, 212.2559) (1233.2868, 212.2044) (1233.2755, 212.1504) (1233.259, 212.0944) (1233.2378, 212.0365) (1233.2131, 211.9754) (1233.182, 211.9098) (1233.1425, 211.8394) (1233.0964, 211.7619) (1233.0425, 211.6781) (1232.9798, 211.5889) (1232.91, 211.4928) (1232.8322, 211.3907) (1232.7485, 211.2844) (1232.6637, 211.178) (1232.5798, 211.0777) (1232.5003, 210.9842) (1232.4246, 210.8982) (1232.3532, 210.8193) (1232.2855, 210.7482) (1232.2214, 210.6847) (1232.1607, 210.628) (1232.1045, 210.5749) (1232.0566, 210.5194) (1232.0145, 210.4627) (1231.9792, 210.4041) (1231.951, 210.3435) (1231.9305, 210.2812) (1231.9146, 210.2179) (1231.9106, 210.1746) (1231.9085, 210.1529) knots 0 0 0 0 0.02948 0.056933 0.082798 0.107648 0.131593 0.154596 0.176909 0.1991 0.220526 0.240936 0.261199 0.282082 0.302975 0.322936 0.342721 0.363062 0.373676 0.384849 0.396516 0.408769 0.421767 0.435473 0.449947 0.465322 0.482094 0.501136 0.522343 0.545818 0.571545 0.599371 0.629735 0.662217 0.694986 0.725847 0.754615 0.781724 0.80675 0.829806 0.851125 0.870503 0.888469 0.905716 0.922245 0.938308 0.953988 0.96933 0.984586 1 1 1 1
  spline B942 degree 3 poles (1345.1235, 213.1002) (1345.0991, 213.0668) (1345.0504, 213.0001) (1344.9711, 212.9042) (1344.8867, 212.8116) (1344.7978, 212.7219) (1344.7039, 212.6356) (1344.6041, 212.5536) (1344.5006, 212.473) (1344.4278, 212.4234) (1344.3912, 212.3985) knots 0 0 0 0 0.121557 0.242856 0.365979 0.489864 0.614317 0.740997 0.869571 1 1 1 1
  spline B943 degree 3 poles (1344.3912, 212.0652) (1344.4485, 212.1) (1344.5599, 212.1678) (1344.7151, 212.2765) (1344.8556, 212.3867) (1344.9397, 212.4655) (1344.9805, 212.5037) knots 0 0 0 0 0.273515 0.530811 0.771994 1 1 1 1
  spline B944 degree 3 poles (1360.2604, 210.8371) (1360.2669, 210.8058) (1360.2796, 210.7446) (1360.3058, 210.6564) (1360.3372, 210.5738) (1360.3755, 210.4974) (1360.4179, 210.4261) (1360.4674, 210.3616) (1360.5212, 210.3019) (1360.5812, 210.249) (1360.645, 210.2015) (1360.7118, 210.1597) (1360.7819, 210.1249) (1360.854, 210.0941) (1360.9299, 210.0722) (1361.0079, 210.054) (1361.089, 210.0434) (1361.172, 210.038) (1361.2552, 210.0394) (1361.337, 210.0469) (1361.4164, 210.0622) (1361.4942, 210.0831) (1361.5689, 210.1132) (1361.6422, 210.1479) (1361.7127, 210.1907) (1361.7801, 210.2397) (1361.8438, 210.2936) (1361.9004, 210.353) (1361.9502, 210.4163) (1361.9925, 210.4837) (1362.0287, 210.5549) (1362.0572, 210.6305) (1362.0786, 210.7104) (1362.0931, 210.7929) (1362.1014, 210.8752) (1362.1039, 210.9547) (1362.1018, 211.0301) (1362.0931, 211.1015) (1362.08, 211.1689) (1362.0601, 211.2322) (1362.0349, 211.2912) (1362.0042, 211.3464) (1361.9678, 211.3968) (1361.9292, 211.445) (1361.8866, 211.4898) (1361.8395, 211.5301) (1361.7903, 211.5694) (1361.736, 211.6032) (1361.6789, 211.6348) (1361.6387, 211.6526) (1361.6184, 211.6616) knots 0 0 0 0 0.025876 0.050575 0.074453 0.09736 0.119713 0.141499 0.163105 0.184723 0.206159 0.227431 0.248455 0.269532 0.290786 0.312362 0.334317 0.356989 0.379621 0.401648 0.423426 0.445088 0.466751 0.488561 0.510673 0.53341 0.556052 0.578136 0.599752 0.621117 0.642533 0.664296 0.686466 0.709451 0.73202 0.753432 0.773793 0.793048 0.81166 0.829303 0.84667 0.863554 0.880296 0.897008 0.913509 0.930291 0.947169 0.964443 0.982027 1 1 1 1
  spline B945 degree 3 poles (1361.6184, 211.6616) (1361.6455, 211.6793) (1361.6983, 211.7136) (1361.7711, 211.7693) (1361.8354, 211.8276) (1361.8915, 211.8877) (1361.9388, 211.9508) (1361.978, 212.0158) (1362.0089, 212.0831) (1362.0309, 212.1522) (1362.045, 212.2216) (1362.0561, 212.2899) (1362.0604, 212.3568) (1362.0598, 212.4224) (1362.0544, 212.4867) (1362.042, 212.5495) (1362.0264, 212.6113) (1362.0038, 212.6708) (1361.9778, 212.7282) (1361.9453, 212.7814) (1361.91, 212.8318) (1361.869, 212.8775) (1361.8245, 212.9198) (1361.7749, 212.9579) (1361.7211, 212.992) (1361.6633, 213.0228) (1361.6017, 213.0483) (1361.5376, 213.0701) (1361.4708, 213.0867) (1361.4016, 213.0994) (1361.3299, 213.106) (1361.2557, 213.1097) (1361.1789, 213.1073) (1361.1005, 213.1011) (1361.0229, 213.0898) (1360.9486, 213.0729) (1360.8781, 213.0509) (1360.8125, 213.0222) (1360.7503, 212.9888) (1360.6927, 212.9498) (1360.6388, 212.9055) (1360.5738, 212.8374) (1360.4988, 212.7431) (1360.4207, 212.6168) (1360.3506, 212.4784) (1360.3146, 212.3792) (1360.2962, 212.3283) knots 0 0 0 0 0.028136 0.054763 0.079725 0.10361 0.126237 0.148227 0.169575 0.190566 0.211203 0.23123 0.250697 0.269554 0.288299 0.306716 0.325239 0.343734 0.36204 0.380052 0.397895 0.415527 0.433401 0.451279 0.469848 0.488827 0.508263 0.527762 0.547793 0.568099 0.588944 0.610461 0.632718 0.6558 0.678867 0.700915 0.722085 0.743031 0.763197 0.783436 0.803523 0.823792 0.865255 0.908208 0.952902 1 1 1 1
  spline B946 degree 3 poles (1360.6178, 212.2757) (1360.6297, 212.3079) (1360.6524, 212.3698) (1360.693, 212.456) (1360.7363, 212.5326) (1360.7832, 212.5991) (1360.8326, 212.6565) (1360.8856, 212.7037) (1360.9417, 212.7417) (1361.0014, 212.7677) (1361.0612, 212.7866) (1361.1205, 212.7987) (1361.179, 212.806) (1361.2367, 212.8045) (1361.2938, 212.7996) (1361.3495, 212.7857) (1361.4049, 212.7672) (1361.4582, 212.7417) (1361.5086, 212.712) (1361.5533, 212.6764) (1361.5922, 212.6368) (1361.6238, 212.5918) (1361.6513, 212.5437) (1361.6704, 212.4902) (1361.684, 212.4329) (1361.6917, 212.3723) (1361.6929, 212.3111) (1361.6883, 212.2518) (1361.6789, 212.1952) (1361.6624, 212.1418) (1361.6403, 212.0913) (1361.6118, 212.0444) (1361.5788, 211.9995) (1361.5386, 211.9587) (1361.4929, 211.9204) (1361.44, 211.8871) (1361.3811, 211.8569) (1361.3157, 211.8311) (1361.2442, 211.8092) (1361.1662, 211.7912) (1361.0821, 211.7759) (1361.0235, 211.77) (1360.9934, 211.7669) knots 0 0 0 0 0.039409 0.075647 0.109149 0.140173 0.168879 0.195808 0.221446 0.246247 0.270216 0.293316 0.315571 0.337687 0.359421 0.381119 0.403436 0.426223 0.448852 0.470429 0.491516 0.512343 0.533365 0.554829 0.577309 0.600857 0.624716 0.647395 0.669088 0.69039 0.711305 0.732144 0.753265 0.775056 0.797645 0.821563 0.846678 0.873441 0.90205 0.932428 0.965232 1 1 1 1
  spline B947 degree 3 poles (1360.9934, 211.5388) (1361.0235, 211.5343) (1361.0821, 211.5255) (1361.1662, 211.5089) (1361.2439, 211.489) (1361.3157, 211.4682) (1361.3806, 211.4433) (1361.4393, 211.4165) (1361.4925, 211.3887) (1361.5383, 211.356) (1361.5794, 211.3217) (1361.6143, 211.2829) (1361.6452, 211.2417) (1361.6717, 211.1972) (1361.692, 211.149) (1361.7086, 211.0977) (1361.72, 211.0432) (1361.7272, 210.9863) (1361.7292, 210.9287) (1361.7257, 210.8717) (1361.7183, 210.8161) (1361.7045, 210.7625) (1361.686, 210.7106) (1361.6634, 210.66) (1361.6345, 210.6116) (1361.6016, 210.5651) (1361.5652, 210.5216) (1361.5244, 210.4837) (1361.4808, 210.4508) (1361.4337, 210.4243) (1361.3838, 210.4026) (1361.3309, 210.3862) (1361.2749, 210.3759) (1361.2167, 210.3719) (1361.1585, 210.3715) (1361.1017, 210.3766) (1361.0474, 210.3874) (1360.9954, 210.4018) (1360.9462, 210.4226) (1360.8992, 210.4469) (1360.8553, 210.4774) (1360.8003, 210.5241) (1360.7381, 210.591) (1360.6728, 210.6803) (1360.6206, 210.781) (1360.5951, 210.853) (1360.5821, 210.8897) knots 0 0 0 0 0.032802 0.063703 0.092308 0.119076 0.144011 0.167063 0.188548 0.208464 0.227476 0.246118 0.264439 0.282827 0.301619 0.320711 0.340734 0.361406 0.382395 0.402707 0.422715 0.442671 0.462207 0.481922 0.502189 0.522755 0.543258 0.563047 0.582533 0.601845 0.621158 0.640916 0.661306 0.682346 0.703557 0.723921 0.743623 0.763025 0.781941 0.800917 0.81986 0.839378 0.878456 0.917854 0.958097 1 1 1 1
  spline B948 degree 3 poles (1376.2551, 210.8195) (1376.2628, 210.7856) (1376.2777, 210.7197) (1376.3083, 210.626) (1376.3415, 210.5392) (1376.3803, 210.4602) (1376.4251, 210.3898) (1376.4732, 210.326) (1376.5262, 210.2697) (1376.5849, 210.2226) (1376.6453, 210.1811) (1376.707, 210.1446) (1376.7697, 210.1134) (1376.833, 210.0866) (1376.8971, 210.0642) (1376.9625, 210.0483) (1377.0284, 210.0364) (1377.116, 210.0272) (1377.2228, 210.0256) (1377.3458, 210.0341) (1377.4613, 210.0552) (1377.5684, 210.0895) (1377.6669, 210.133) (1377.759, 210.1812) (1377.8419, 210.2383) (1377.9184, 210.3006) (1377.9859, 210.3713) (1378.0442, 210.4509) (1378.0939, 210.5392) (1378.133, 210.6352) (1378.1644, 210.7345) (1378.1886, 210.834) (1378.2049, 210.9323) (1378.2136, 211.0292) (1378.2137, 211.1239) (1378.2091, 211.2158) (1378.1965, 211.3044) (1378.1778, 211.3904) (1378.1511, 211.4742) (1378.1185, 211.5577) (1378.0794, 211.6412) (1378.0349, 211.7249) (1377.9787, 211.8049) (1377.9057, 211.8751) (1377.8196, 211.9377) (1377.72, 211.9887) (1377.6131, 212.0312) (1377.5018, 212.062) (1377.3889, 212.0842) (1377.2731, 212.094) (1377.1531, 212.0907) (1377.0296, 212.0687) (1376.9012, 212.0324) (1376.8172, 211.9962) (1376.7736, 211.9774) knots 0 0 0 0 0.020599 0.039992 0.058312 0.075639 0.092012 0.107664 0.122909 0.137676 0.152159 0.166307 0.180076 0.193587 0.207015 0.220239 0.233401 0.24669 0.272353 0.296539 0.319637 0.341709 0.362968 0.383344 0.403199 0.422516 0.441662 0.460933 0.480808 0.501512 0.522245 0.542439 0.562074 0.581262 0.599993 0.618111 0.635728 0.652941 0.670145 0.687775 0.706027 0.724743 0.743863 0.763639 0.784399 0.806722 0.829759 0.852421 0.875016 0.897805 0.921166 0.945885 0.971913 1 1 1 1
  spline B949 degree 3 poles (1376.7736, 211.9774) (1376.781, 212.0019) (1376.7964, 212.0527) (1376.8194, 212.1318) (1376.8412, 212.217) (1376.8632, 212.3083) (1376.8863, 212.4054) (1376.9078, 212.5089) (1376.9311, 212.6181) (1376.9451, 212.6932) (1376.9523, 212.7318) knots 0 0 0 0 0.098849 0.205167 0.318538 0.439221 0.568247 0.704448 0.848199 1 1 1 1
  spline B950 degree 3 poles (1376.6839, 213.0476) (1376.6715, 212.9909) (1376.6474, 212.8807) (1376.6135, 212.7202) (1376.5799, 212.5703) (1376.5496, 212.4303) (1376.5208, 212.3007) (1376.4952, 212.1807) (1376.4701, 212.0713) (1376.4483, 211.9718) (1376.4281, 211.8825) (1376.4097, 211.8036) (1376.3947, 211.7345) (1376.3798, 211.676) (1376.3685, 211.6273) (1376.3587, 211.5888) (1376.351, 211.5605) (1376.3465, 211.5449) (1376.3448, 211.5388) knots 0 0 0 0 0.112653 0.218791 0.318182 0.410647 0.496685 0.575798 0.648575 0.714426 0.773441 0.826031 0.871694 0.910621 0.943026 0.968604 0.987765 1 1 1 1
  spline B951 degree 3 poles (1376.6482, 211.5038) (1376.6603, 211.5194) (1376.6841, 211.5501) (1376.724, 211.5915) (1376.7659, 211.6292) (1376.8106, 211.6621) (1376.8578, 211.6912) (1376.9078, 211.715) (1376.9603, 211.7346) (1377.0319, 211.755) (1377.1212, 211.7704) (1377.2252, 211.7776) (1377.3238, 211.7712) (1377.4167, 211.7522) (1377.5028, 211.7185) (1377.5818, 211.6722) (1377.6521, 211.6116) (1377.7144, 211.5398) (1377.7661, 211.4564) (1377.8036, 211.3628) (1377.8286, 211.2609) (1377.8386, 211.1527) (1377.8373, 211.0432) (1377.8252, 210.9368) (1377.8016, 210.8358) (1377.7676, 210.7404) (1377.7207, 210.6516) (1377.6595, 210.5717) (1377.5849, 210.5007) (1377.5128, 210.4502) (1377.4488, 210.4154) (1377.3959, 210.3948) (1377.3396, 210.3791) (1377.2797, 210.3689) (1377.2162, 210.3635) (1377.1493, 210.3648) (1377.0788, 210.37) (1377.0057, 210.3796) (1376.9321, 210.3977) (1376.8635, 210.4319) (1376.8008, 210.4791) (1376.744, 210.5393) (1376.6922, 210.6121) (1376.6481, 210.6991) (1376.6082, 210.7982) (1376.5876, 210.8698) (1376.5767, 210.9073) knots 0 0 0 0 0.016032 0.0316 0.046691 0.061799 0.076657 0.091699 0.106744 0.122126 0.152176 0.180228 0.206699 0.232255 0.257008 0.281559 0.306292 0.332133 0.358619 0.385628 0.413728 0.443636 0.473748 0.502644 0.530492 0.557841 0.584782 0.611793 0.639317 0.668138 0.683105 0.698441 0.714162 0.730605 0.747743 0.76588 0.784949 0.805219 0.825806 0.846201 0.867085 0.889253 0.913243 0.939469 0.968309 1 1 1 1
  spline B952 degree 3 poles (1393.2862, 210.0827) (1393.3103, 210.1941) (1393.359, 210.4183) (1393.4537, 210.7519) (1393.5654, 211.0856) (1393.6959, 211.4191) (1393.8436, 211.7527) (1394.009, 212.0864) (1394.192, 212.4201) (1394.3262, 212.6388) (1394.394, 212.7494) knots 0 0 0 0 0.117755 0.236999 0.358088 0.481311 0.606856 0.734965 0.865975 1 1 1 1
  spline B953 degree 3 poles (1394.0191, 212.7318) (1393.9538, 212.6225) (1393.8244, 212.4058) (1393.6456, 212.0758) (1393.4826, 211.7451) (1393.3341, 211.414) (1393.2006, 211.0824) (1393.0826, 210.7502) (1392.9778, 210.4179) (1392.9212, 210.1941) (1392.893, 210.0827) knots 0 0 0 0 0.132219 0.261895 0.389489 0.514883 0.638461 0.760417 0.880737 1 1 1 1
  spline B954 degree 3 number of poles 75 (1409.3523, 210.0301) -> (1409.6025, 211.2055)
  spline B955 degree 3 poles (1409.6025, 211.2055) (1409.5809, 211.1611) (1409.5368, 211.0705) (1409.4684, 210.9327) (1409.3938, 210.7919) (1409.316, 210.6468) (1409.2334, 210.4981) (1409.1463, 210.3454) (1409.0547, 210.1887) (1408.9914, 210.0835) (1408.9592, 210.0301) knots 0 0 0 0 0.110561 0.225453 0.344271 0.467022 0.593952 0.72508 0.860425 1 1 1 1
  spline B956 degree 3 poles (1418.4871, 211.3925) (1418.4898, 211.4551) (1418.4933, 211.5938) (1418.4886, 211.8042) (1418.4725, 212.019) (1418.4474, 212.1885) (1418.4208, 212.3167) (1418.3953, 212.4072) (1418.365, 212.4937) (1418.3287, 212.5759) (1418.2891, 212.6546) (1418.2428, 212.7285) (1418.1925, 212.7986) (1418.1373, 212.864) (1418.0789, 212.9239) (1418.0162, 212.9751) (1417.9516, 213.0192) (1417.8843, 213.0552) (1417.8145, 213.0832) (1417.7423, 213.1038) (1417.6674, 213.1153) (1417.5911, 213.1188) (1417.5152, 213.1163) (1417.4414, 213.1076) (1417.3706, 213.0945) (1417.3033, 213.0743) (1417.2383, 213.0508) (1417.1769, 213.0201) (1417.1185, 212.9839) (1417.045, 212.9292) (1416.9605, 212.8508) (1416.8717, 212.7438) (1416.7945, 212.6253) (1416.7408, 212.5171) (1416.7047, 212.4231) (1416.6801, 212.3459) (1416.6588, 212.2625) (1416.6407, 212.1734) (1416.626, 212.0782) (1416.6136, 211.977) (1416.6046, 211.8697) (1416.6009, 211.7962) (1416.5995, 211.7585) knots 0 0 0 0 0.023197 0.051343 0.07788 0.102846 0.114733 0.126306 0.137615 0.148637 0.159536 0.170192 0.180873 0.191455 0.201829 0.211796 0.221379 0.23074 0.239985 0.249147 0.258479 0.267951 0.277416 0.286534 0.295433 0.304034 0.312507 0.321004 0.329391 0.337873 0.354893 0.371911 0.389233 0.407123 0.416488 0.426502 0.437099 0.448309 0.460158 0.472757 0.486032 0.5 0.5 0.5 0.5
  spline B957 degree 3 poles (1416.5995, 211.7585) (1416.598, 211.7208) (1416.5961, 211.6474) (1416.5944, 211.5401) (1416.5959, 211.4387) (1416.599, 211.3434) (1416.604, 211.2543) (1416.6118, 211.1713) (1416.6221, 211.0944) (1416.6385, 210.9998) (1416.6648, 210.8869) (1416.7051, 210.7557) (1416.7542, 210.6275) (1416.8022, 210.5237) (1416.8468, 210.4431) (1416.8866, 210.3858) (1416.9324, 210.332) (1416.9832, 210.2808) (1417.0402, 210.2336) (1417.102, 210.1884) (1417.1701, 210.1471) (1417.2422, 210.1084) (1417.3173, 210.0753) (1417.3935, 210.0506) (1417.4697, 210.0336) (1417.546, 210.027) (1417.6225, 210.0271) (1417.6989, 210.0375) (1417.7755, 210.0547) (1417.8508, 210.0816) (1417.9238, 210.1153) (1417.9932, 210.1546) (1418.0568, 210.2016) (1418.1172, 210.2527) (1418.1721, 210.3109) (1418.2211, 210.3758) (1418.2673, 210.4454) (1418.3073, 210.5218) (1418.3427, 210.6042) (1418.3755, 210.6916) (1418.4031, 210.7854) (1418.4279, 210.8843) (1418.4479, 210.9896) (1418.4637, 211.1004) (1418.4772, 211.217) (1418.4835, 211.315) (1418.4863, 211.3741) (1418.4871, 211.3925) knots 0.5 0.5 0.5 0.5 0.513955 0.527184 0.539691 0.551482 0.562484 0.572711 0.582337 0.591207 0.608242 0.625181 0.642005 0.659005 0.667477 0.676061 0.684765 0.693608 0.702713 0.712126 0.721915 0.732172 0.742404 0.752266 0.761779 0.7712 0.78058 0.790036 0.799663 0.809601 0.819574 0.829378 0.83908 0.848801 0.858612 0.868618 0.878868 0.889483 0.900505 0.912046 0.924017 0.936655 0.9498 0.963654 0.978093 0.993201 1 1 1 1
  spline B958 degree 3 poles (1425.6329, 213.1002) (1425.6085, 213.0668) (1425.5598, 213.0001) (1425.4805, 212.9042) (1425.3962, 212.8116) (1425.3072, 212.7219) (1425.2133, 212.6356) (1425.1136, 212.5536) (1425.0101, 212.473) (1424.9372, 212.4234) (1424.9006, 212.3985) knots 0 0 0 0 0.121557 0.242856 0.365979 0.489864 0.614317 0.740997 0.869571 1 1 1 1
  spline B959 degree 3 poles (1424.9006, 212.0652) (1424.9579, 212.1) (1425.0693, 212.1678) (1425.2246, 212.2765) (1425.365, 212.3867) (1425.4491, 212.4655) (1425.4899, 212.5037) knots 0 0 0 0 0.273515 0.530811 0.771994 1 1 1 1
  spline B960 degree 3 poles (1433.2732, 210.3985) (1433.3024, 210.4316) (1433.3597, 210.4965) (1433.444, 210.5921) (1433.5234, 210.6851) (1433.6003, 210.7742) (1433.6739, 210.8595) (1433.7423, 210.9427) (1433.8093, 211.0206) (1433.8704, 211.0971) (1433.9292, 211.1692) (1433.9844, 211.2379) (1434.0357, 211.3035) (1434.0834, 211.3658) (1434.1264, 211.4254) (1434.1681, 211.48) (1434.2039, 211.5329) (1434.2478, 211.5968) (1434.2969, 211.6732) (1434.3487, 211.7626) (1434.394, 211.8488) (1434.4323, 211.9316) (1434.4638, 212.0111) (1434.4883, 212.0875) (1434.5051, 212.1608) (1434.5189, 212.252) (1434.5222, 212.3598) (1434.5139, 212.4821) (1434.4875, 212.5947) (1434.4465, 212.6965) (1434.3934, 212.7863) (1434.3345, 212.8658) (1434.2682, 212.9333) (1434.1953, 212.9873) (1434.1197, 213.0303) (1434.0451, 213.0655) (1433.9719, 213.093) (1433.8985, 213.1105) (1433.8234, 213.121) (1433.745, 213.1251) (1433.662, 213.1246) (1433.6056, 213.1201) (1433.5766, 213.1178) knots 0 0 0 0 0.035373 0.069278 0.101977 0.133322 0.163445 0.192123 0.219558 0.245685 0.270458 0.294013 0.316242 0.33715 0.35674 0.375081 0.392153 0.407876 0.437114 0.464767 0.490588 0.515022 0.537749 0.559022 0.579124 0.597879 0.632752 0.665274 0.695719 0.724885 0.752775 0.779021 0.803906 0.828176 0.851399 0.873424 0.8941 0.913904 0.933689 0.9547 0.976718 1 1 1 1
  spline B961 degree 3 poles (1433.5766, 213.1178) (1433.5516, 213.1158) (1433.5024, 213.1119) (1433.4302, 213.099) (1433.3602, 213.0827) (1433.293, 213.0594) (1433.228, 213.0319) (1433.1661, 212.998) (1433.1058, 212.9606) (1433.0486, 212.9167) (1432.9934, 212.8671) (1432.9417, 212.81) (1432.8912, 212.7472) (1432.8447, 212.6762) (1432.7997, 212.5992) (1432.7586, 212.5148) (1432.7185, 212.4245) (1432.6951, 212.3609) (1432.6832, 212.3283) knots 0 0 0 0 0.058881 0.116278 0.172401 0.227846 0.283327 0.338283 0.393714 0.450086 0.507822 0.568061 0.631184 0.69734 0.767451 0.840846 0.918214 1 1 1 1
  spline B962 degree 3 poles (1433.023, 212.2757) (1433.0384, 212.3145) (1433.0682, 212.3895) (1433.1286, 212.4905) (1433.199, 212.5764) (1433.2798, 212.6454) (1433.3659, 212.6998) (1433.4547, 212.7419) (1433.546, 212.7709) (1433.6383, 212.7867) (1433.7294, 212.7884) (1433.8162, 212.7714) (1433.8979, 212.7394) (1433.9712, 212.6901) (1434.0354, 212.6301) (1434.0854, 212.5598) (1434.1222, 212.4826) (1434.1393, 212.4123) (1434.1452, 212.3529) (1434.1459, 212.3055) (1434.1419, 212.2559) (1434.1329, 212.2044) (1434.1216, 212.1504) (1434.1051, 212.0944) (1434.0839, 212.0365) (1434.0592, 211.9754) (1434.0281, 211.9098) (1433.9886, 211.8394) (1433.9425, 211.7619) (1433.8886, 211.6781) (1433.8259, 211.5889) (1433.7561, 211.4928) (1433.6784, 211.3907) (1433.5947, 211.2844) (1433.5098, 211.178) (1433.426, 211.0777) (1433.3464, 210.9842) (1433.2708, 210.8982) (1433.1993, 210.8193) (1433.1316, 210.7482) (1433.0675, 210.6847) (1433.0069, 210.628) (1432.9507, 210.5749) (1432.9027, 210.5194) (1432.8607, 210.4627) (1432.8253, 210.4041) (1432.7971, 210.3435) (1432.7767, 210.2812) (1432.7608, 210.2179) (1432.7567, 210.1746) (1432.7546, 210.1529) knots 0 0 0 0 0.02948 0.056933 0.082798 0.107648 0.131593 0.154596 0.176909 0.1991 0.220526 0.240936 0.261199 0.282082 0.302975 0.322936 0.342721 0.363062 0.373676 0.384849 0.396516 0.408769 0.421767 0.435473 0.449947 0.465322 0.482094 0.501136 0.522343 0.545818 0.571545 0.599371 0.629735 0.662217 0.694986 0.725847 0.754615 0.781724 0.80675 0.829806 0.851125 0.870503 0.888469 0.905716 0.922245 0.938308 0.953988 0.96933 0.984586 1 1 1 1
  spline B963 degree 3 poles (1440.7698, 210.8371) (1440.7763, 210.8058) (1440.789, 210.7446) (1440.8153, 210.6564) (1440.8466, 210.5738) (1440.8849, 210.4974) (1440.9273, 210.4261) (1440.9768, 210.3616) (1441.0306, 210.3019) (1441.0906, 210.249) (1441.1544, 210.2015) (1441.2212, 210.1597) (1441.2914, 210.1249) (1441.3634, 210.0941) (1441.4393, 210.0722) (1441.5173, 210.054) (1441.5985, 210.0434) (1441.6814, 210.038) (1441.7646, 210.0394) (1441.8464, 210.0469) (1441.9259, 210.0622) (1442.0036, 210.0831) (1442.0783, 210.1132) (1442.1516, 210.1479) (1442.2221, 210.1907) (1442.2896, 210.2397) (1442.3532, 210.2936) (1442.4098, 210.353) (1442.4596, 210.4163) (1442.5019, 210.4837) (1442.5381, 210.5549) (1442.5666, 210.6305) (1442.588, 210.7104) (1442.6025, 210.7929) (1442.6108, 210.8752) (1442.6134, 210.9547) (1442.6113, 211.0301) (1442.6025, 211.1015) (1442.5894, 211.1689) (1442.5695, 211.2322) (1442.5443, 211.2912) (1442.5137, 211.3464) (1442.4772, 211.3968) (1442.4386, 211.445) (1442.3961, 211.4898) (1442.3489, 211.5301) (1442.2997, 211.5694) (1442.2454, 211.6032) (1442.1883, 211.6348) (1442.1482, 211.6526) (1442.1279, 211.6616) knots 0 0 0 0 0.025876 0.050575 0.074453 0.09736 0.119713 0.141499 0.163105 0.184723 0.206159 0.227431 0.248455 0.269532 0.290786 0.312362 0.334317 0.356989 0.379621 0.401648 0.423426 0.445088 0.466751 0.488561 0.510673 0.53341 0.556052 0.578136 0.599752 0.621117 0.642533 0.664296 0.686466 0.709451 0.73202 0.753432 0.773793 0.793048 0.81166 0.829303 0.84667 0.863554 0.880296 0.897008 0.913509 0.930291 0.947169 0.964443 0.982027 1 1 1 1
  spline B964 degree 3 poles (1442.1279, 211.6616) (1442.155, 211.6793) (1442.2077, 211.7136) (1442.2806, 211.7693) (1442.3448, 211.8276) (1442.401, 211.8877) (1442.4482, 211.9508) (1442.4874, 212.0158) (1442.5183, 212.0831) (1442.5403, 212.1522) (1442.5545, 212.2216) (1442.5655, 212.2899) (1442.5699, 212.3568) (1442.5692, 212.4224) (1442.5638, 212.4867) (1442.5514, 212.5495) (1442.5358, 212.6113) (1442.5132, 212.6708) (1442.4872, 212.7282) (1442.4547, 212.7814) (1442.4194, 212.8318) (1442.3784, 212.8775) (1442.3339, 212.9198) (1442.2843, 212.9579) (1442.2306, 212.992) (1442.1727, 213.0228) (1442.1112, 213.0483) (1442.047, 213.0701) (1441.9802, 213.0867) (1441.911, 213.0994) (1441.8393, 213.106) (1441.7651, 213.1097) (1441.6883, 213.1073) (1441.6099, 213.1011) (1441.5323, 213.0898) (1441.458, 213.0729) (1441.3876, 213.0509) (1441.3219, 213.0222) (1441.2597, 212.9888) (1441.2021, 212.9498) (1441.1482, 212.9055) (1441.0832, 212.8374) (1441.0082, 212.7431) (1440.9301, 212.6168) (1440.86, 212.4784) (1440.824, 212.3792) (1440.8056, 212.3283) knots 0 0 0 0 0.028136 0.054763 0.079725 0.10361 0.126237 0.148227 0.169575 0.190566 0.211203 0.23123 0.250697 0.269554 0.288299 0.306716 0.325239 0.343734 0.36204 0.380052 0.397895 0.415527 0.433401 0.451279 0.469848 0.488827 0.508263 0.527762 0.547793 0.568099 0.588944 0.610461 0.632718 0.6558 0.678867 0.700915 0.722085 0.743031 0.763197 0.783436 0.803523 0.823792 0.865255 0.908208 0.952902 1 1 1 1
  spline B965 degree 3 poles (1441.1272, 212.2757) (1441.1391, 212.3079) (1441.1618, 212.3698) (1441.2024, 212.456) (1441.2457, 212.5326) (1441.2926, 212.5991) (1441.342, 212.6565) (1441.395, 212.7037) (1441.4512, 212.7417) (1441.5108, 212.7677) (1441.5707, 212.7866) (1441.6299, 212.7987) (1441.6884, 212.806) (1441.7461, 212.8045) (1441.8032, 212.7996) (1441.859, 212.7857) (1441.9143, 212.7672) (1441.9677, 212.7417) (1442.0181, 212.712) (1442.0627, 212.6764) (1442.1016, 212.6368) (1442.1332, 212.5918) (1442.1607, 212.5437) (1442.1798, 212.4902) (1442.1934, 212.4329) (1442.2011, 212.3723) (1442.2023, 212.3111) (1442.1977, 212.2518) (1442.1883, 212.1952) (1442.1718, 212.1418) (1442.1498, 212.0913) (1442.1213, 212.0444) (1442.0882, 211.9995) (1442.0481, 211.9587) (1442.0023, 211.9204) (1441.9494, 211.8871) (1441.8905, 211.8569) (1441.8252, 211.8311) (1441.7536, 211.8092) (1441.6756, 211.7912) (1441.5916, 211.7759) (1441.533, 211.77) (1441.5028, 211.7669) knots 0 0 0 0 0.039409 0.075647 0.109149 0.140173 0.168879 0.195808 0.221446 0.246247 0.270216 0.293316 0.315571 0.337687 0.359421 0.381119 0.403436 0.426223 0.448852 0.470429 0.491516 0.512343 0.533365 0.554829 0.577309 0.600857 0.624716 0.647395 0.669088 0.69039 0.711305 0.732144 0.753265 0.775056 0.797645 0.821563 0.846678 0.873441 0.90205 0.932428 0.965232 1 1 1 1
  spline B966 degree 3 poles (1441.5028, 211.5388) (1441.5329, 211.5343) (1441.5915, 211.5255) (1441.6757, 211.5089) (1441.7534, 211.489) (1441.8251, 211.4682) (1441.89, 211.4433) (1441.9488, 211.4165) (1442.0019, 211.3887) (1442.0477, 211.356) (1442.0889, 211.3217) (1442.1237, 211.2829) (1442.1547, 211.2417) (1442.1811, 211.1972) (1442.2015, 211.149) (1442.2181, 211.0977) (1442.2294, 211.0432) (1442.2366, 210.9863) (1442.2386, 210.9287) (1442.2351, 210.8717) (1442.2278, 210.8161) (1442.2139, 210.7625) (1442.1954, 210.7106) (1442.1728, 210.66) (1442.1439, 210.6116) (1442.111, 210.5651) (1442.0746, 210.5216) (1442.0338, 210.4837) (1441.9903, 210.4508) (1441.9431, 210.4243) (1441.8933, 210.4026) (1441.8404, 210.3862) (1441.7843, 210.3759) (1441.7262, 210.3719) (1441.6679, 210.3715) (1441.6111, 210.3766) (1441.5568, 210.3874) (1441.5048, 210.4018) (1441.4557, 210.4226) (1441.4087, 210.4469) (1441.3647, 210.4774) (1441.3098, 210.5241) (1441.2475, 210.591) (1441.1822, 210.6803) (1441.13, 210.781) (1441.1045, 210.853) (1441.0915, 210.8897) knots 0 0 0 0 0.032802 0.063703 0.092308 0.119076 0.144011 0.167063 0.188548 0.208464 0.227476 0.246118 0.264439 0.282827 0.301619 0.320711 0.340735 0.361406 0.382395 0.402707 0.422715 0.442671 0.462207 0.481922 0.502189 0.522755 0.543258 0.563047 0.582533 0.601845 0.621158 0.640916 0.661306 0.682346 0.703557 0.723921 0.743623 0.763025 0.781941 0.800917 0.81986 0.839378 0.878456 0.917854 0.958097 1 1 1 1
  spline B967 degree 3 poles (1342.2701, 210.9368) (1342.2479, 210.9156) (1342.2334, 210.9077) (1342.2145, 210.8979) knots 0.25082 0.25082 0.25082 0.25082 0.545652 0.545652 0.545652 0.545652
  spline B968 degree 3 poles (1342.2145, 210.8979) (1342.1939, 210.8873) (1342.1682, 210.8744) (1342.1424, 210.8658) knots 0.545652 0.545652 0.545652 0.545652 0.864595 0.864595 0.864595 0.864595
  spline B969 degree 3 poles (1342.1424, 210.8658) (1342.1133, 210.8562) (1342.0841, 210.8521) (1342.0544, 210.8529) knots 0.864595 0.864595 0.864595 0.864595 1.224079 1.224079 1.224079 1.224079
  spline B970 degree 3 poles (1342.0544, 210.8529) (1342.0141, 210.8541) (1341.9729, 210.8643) (1341.9371, 210.8831) knots 1.224078 1.224078 1.224078 1.224078 1.712263 1.712263 1.712263 1.712263
  spline B971 degree 3 poles (1341.9371, 210.8831) (1341.9215, 210.8912) (1341.9069, 210.901) (1341.8932, 210.9124) knots 1.712263 1.712263 1.712263 1.712263 1.925678 1.925678 1.925678 1.925678
  spline B972 degree 3 poles (1341.8932, 210.9124) (1341.8691, 210.9324) (1341.848, 210.9573) (1341.835, 210.9852) knots 1.925678 1.925678 1.925678 1.925678 2.302789 2.302789 2.302789 2.302789
  spline B973 degree 3 poles (1342.9195, 211.1467) (1342.9239, 211.1639) (1342.9278, 211.1805) (1342.9311, 211.1966) knots 0 0 0 0 0.247209 0.247209 0.247209 0.247209
  spline B974 degree 3 poles (1342.9311, 211.1966) (1342.9425, 211.2517) (1342.9454, 211.2981) (1342.9477, 211.3447) knots 0.247209 0.247209 0.247209 0.247209 0.810326 0.810326 0.810326 0.810326
  spline B975 degree 3 poles (1342.9477, 211.3447) (1342.9498, 211.3871) (1342.9512, 211.4295) (1342.9477, 211.4715) knots 0.810326 0.810326 0.810326 0.810326 1.323074 1.323074 1.323074 1.323074
  spline B976 degree 3 poles (1342.9477, 211.4715) (1342.9449, 211.5042) (1342.9391, 211.5366) (1342.9328, 211.5693) knots 1.323074 1.323074 1.323074 1.323074 1.72324 1.72324 1.72324 1.72324
  spline B977 degree 3 poles (1342.9328, 211.5693) (1342.926, 211.6045) (1342.9186, 211.6399) (1342.9039, 211.6719) knots 1.72324 1.72324 1.72324 1.72324 2.154597 2.154597 2.154597 2.154597
  spline B978 degree 3 poles (1342.9039, 211.6719) (1342.8925, 211.6969) (1342.8766, 211.7198) (1342.8611, 211.7434) knots 2.154597 2.154597 2.154597 2.154597 2.49133 2.49133 2.49133 2.49133
  spline B979 degree 3 poles (1342.8611, 211.7434) (1342.8257, 211.797) (1342.7922, 211.8538) (1342.7424, 211.8917) knots 2.49133 2.49133 2.49133 2.49133 3.259934 3.259934 3.259934 3.259934
  spline B980 degree 3 poles (1342.7424, 211.8917) (1342.7203, 211.9085) (1342.6951, 211.9215) (1342.6702, 211.935) knots 3.259934 3.259934 3.259934 3.259934 3.600232 3.600232 3.600232 3.600232
  spline B981 degree 3 poles (1342.6702, 211.935) (1342.6408, 211.9509) (1342.612, 211.9673) (1342.5813, 211.9794) knots 3.600232 3.600232 3.600232 3.600232 4.002056 4.002056 4.002056 4.002056
  spline B982 degree 3 poles (1342.5813, 211.9794) (1342.5442, 211.994) (1342.5045, 212.0023) (1342.4647, 212.0084) knots 4.002056 4.002056 4.002056 4.002056 4.487879 4.487879 4.487879 4.487879
  spline B983 degree 3 poles (1342.4647, 212.0084) (1342.4207, 212.0152) (1342.3768, 212.0194) (1342.3325, 212.0233) knots 4.48788 4.48788 4.48788 4.48788 5.026313 5.026313 5.026313 5.026313
  spline B984 degree 3 poles (1342.3325, 212.0233) (1342.2253, 212.0327) (1342.1163, 212.0406) (1342.0106, 212.0232) knots 5.026313 5.026313 5.026313 5.026313 6.328079 6.328079 6.328079 6.328079
  spline B985 degree 3 poles (1342.0106, 212.0232) (1341.9559, 212.0142) (1341.902, 211.9984) (1341.8498, 211.9793) knots 6.328079 6.328079 6.328079 6.328079 7.002356 7.002356 7.002356 7.002356
  spline B986 degree 3 poles (1341.8498, 211.9793) (1341.8249, 211.9702) (1341.8004, 211.9603) (1341.7761, 211.95) knots 7.002356 7.002356 7.002356 7.002356 7.322833 7.322833 7.322833 7.322833
  spline B987 degree 3 poles (1341.7761, 211.95) (1341.726, 211.9289) (1341.6766, 211.9059) (1341.6301, 211.8771) knots 7.322833 7.322833 7.322833 7.322833 7.983075 7.983075 7.983075 7.983075
  spline B988 degree 3 poles (1341.6301, 211.8771) (1341.5622, 211.835) (1341.5007, 211.7806) (1341.4545, 211.7159) knots 7.983075 7.983075 7.983075 7.983075 8.947105 8.947105 8.947105 8.947105
  spline B989 degree 3 poles (1341.4545, 211.7159) (1341.4253, 211.675) (1341.4023, 211.6299) (1341.3811, 211.5842) knots 8.947105 8.947105 8.947105 8.947105 9.556783 9.556783 9.556783 9.556783
  spline B990 degree 3 poles (1341.3811, 211.5842) (1341.359, 211.5363) (1341.3389, 211.4875) (1341.322, 211.4377) knots 9.556783 9.556783 9.556783 9.556783 10.195676 10.195676 10.195676 10.195676
  spline B991 degree 3 poles (1341.322, 211.4377) (1341.3043, 211.3851) (1341.2901, 211.3314) (1341.2786, 211.2768) knots 10.195676 10.195676 10.195676 10.195676 10.869827 10.869827 10.869827 10.869827
  spline B992 degree 3 poles (1341.2786, 211.2768) (1341.2716, 211.2433) (1341.2656, 211.2095) (1341.2643, 211.1757) knots 10.869827 10.869827 10.869827 10.869827 11.282752 11.282752 11.282752 11.282752
  spline B993 degree 3 poles (1341.2643, 211.1757) (1341.2616, 211.107) (1341.2782, 211.0384) (1341.2938, 210.9703) knots 11.282752 11.282752 11.282752 11.282752 12.122088 12.122088 12.122088 12.122088
  spline B994 degree 3 poles (1341.2938, 210.9703) (1341.3018, 210.9354) (1341.3095, 210.9006) (1341.3228, 210.8681) knots 12.122088 12.122088 12.122088 12.122088 12.551728 12.551728 12.551728 12.551728
  spline B995 degree 3 poles (1341.3228, 210.8681) (1341.3451, 210.8132) (1341.383, 210.7648) (1341.4253, 210.7211) knots 12.551728 12.551728 12.551728 12.551728 13.276397 13.276397 13.276397 13.276397
  spline B996 degree 3 poles (1341.4253, 210.7211) (1341.4647, 210.6804) (1341.5079, 210.6437) (1341.5568, 210.6183) knots 13.276397 13.276397 13.276397 13.276397 13.951563 13.951563 13.951563 13.951563
  spline B997 degree 3 poles (1341.5568, 210.6183) (1341.6148, 210.588) (1341.6809, 210.5736) (1341.7467, 210.561) knots 13.951563 13.951563 13.951563 13.951563 14.753591 14.753591 14.753591 14.753591
  spline B998 degree 3 poles (1341.7467, 210.561) (1341.83, 210.5452) (1341.913, 210.5324) (1341.9962, 210.5316) knots 14.753591 14.753591 14.753591 14.753591 15.769925 15.769925 15.769925 15.769925
  spline B999 degree 3 poles (1341.9962, 210.5316) (1342.0911, 210.5306) (1342.1864, 210.5452) (1342.2813, 210.5606) knots 15.769925 15.769925 15.769925 15.769925 16.928879 16.928879 16.928879 16.928879
  spline B1000 degree 3 poles (1342.2813, 210.5606) (1342.3285, 210.5682) (1342.3755, 210.576) (1342.4205, 210.5905) knots 16.928879 16.928879 16.928879 16.928879 17.5046 17.5046 17.5046 17.5046
  spline B1001 degree 3 poles (1342.4205, 210.5905) (1342.4546, 210.6015) (1342.4875, 210.6163) (1342.5199, 210.633) knots 17.504599 17.504599 17.504599 17.504599 17.942118 17.942118 17.942118 17.942118
  spline B1002 degree 3 poles (1342.5199, 210.633) (1342.584, 210.6659) (1342.6463, 210.7059) (1342.698, 210.7509) knots 17.942117 17.942117 17.942117 17.942117 18.80599 18.80599 18.80599 18.80599
  spline B1003 degree 3 poles (1342.698, 210.7509) (1342.728, 210.7771) (1342.7545, 210.8048) (1342.7856, 210.8385) knots 18.80599 18.80599 18.80599 18.80599 19.306749 19.306749 19.306749 19.306749
  spline B1004 degree 3 poles (1342.7856, 210.8385) (1342.8174, 210.873) (1342.854, 210.9136) (1342.8593, 210.9415) (1342.8593, 210.9415) (1342.8593, 210.9415) (1342.8593, 210.9415) knots 19.306749 19.306749 19.306749 19.306749 19.819127 19.819127 19.819127 19.819236 19.819236 19.819236 19.819236
  spline B1005 degree 3 poles (1342.3173, 210.9852) (1342.3135, 210.9825) (1342.289, 210.9548) (1342.2701, 210.9368) knots 0 0 0 0 0.25082 0.25082 0.25082 0.25082
  spline B1006 degree 3 poles (1341.835, 210.9852) (1341.8124, 211.0336) (1341.8142, 211.0913) (1341.8201, 211.1463) (1341.8201, 211.1463) (1341.8201, 211.1464) (1341.8201, 211.1464) knots 2.302789 2.302789 2.302789 2.302789 2.957072 2.957072 2.957072 2.957312 2.957312 2.957312 2.957312
  spline B1007 degree 3 poles (1446.8541, 212.133) (1446.8485, 212.151) (1446.838, 212.1849) (1446.8253, 212.2334) (1446.8149, 212.2764) (1446.8106, 212.3035) (1446.8087, 212.3161) knots 0 0 0 0 0.298832 0.564305 0.7973 1 1 1 1
  spline B1008 degree 3 poles (1446.8014, 212.3161) (1446.7999, 212.3058) (1446.7967, 212.2836) (1446.7897, 212.2486) (1446.7806, 212.2096) (1446.7694, 212.1667) (1446.7561, 212.12) (1446.7405, 212.0693) (1446.7231, 212.0145) (1446.7102, 211.9768) (1446.7036, 211.9572) knots 0 0 0 0 0.083843 0.180016 0.287521 0.406461 0.53691 0.678924 0.833643 1 1 1 1
  spline B1009 degree 3 poles (1447.5294, 211.5126) (1447.5328, 211.5015) (1447.5393, 211.4801) (1447.5489, 211.4498) (1447.5569, 211.4225) (1447.5638, 211.3985) (1447.5693, 211.3777) (1447.5742, 211.3603) (1447.5776, 211.346) (1447.5795, 211.3375) (1447.5804, 211.3338) knots 0 0 0 0 0.188143 0.359506 0.513418 0.647688 0.762336 0.860201 0.938484 1 1 1 1
  spline B1010 degree 3 poles (1447.5877, 211.3338) (1447.5881, 211.3414) (1447.5891, 211.3583) (1447.5938, 211.3855) (1447.6003, 211.4174) (1447.6089, 211.4539) (1447.6201, 211.4951) (1447.634, 211.5408) (1447.6497, 211.5914) (1447.6616, 211.6264) (1447.6678, 211.6447) knots 0 0 0 0 0.070812 0.157113 0.257707 0.374044 0.506551 0.655345 0.820102 1 1 1 1
  spline B1011 degree 3 poles (1408.8611, 211.995) (1408.8579, 212.0327) (1408.8517, 212.1073) (1408.8635, 212.219) (1408.8884, 212.3289) (1408.9237, 212.4165) (1408.9565, 212.4838) (1408.9852, 212.5297) (1409.015, 212.5718) (1409.0482, 212.609) (1409.0822, 212.6428) (1409.1201, 212.6703) (1409.1586, 212.6959) (1409.213, 212.7199) (1409.2777, 212.7448) (1409.3513, 212.7628) (1409.4173, 212.7726) (1409.4584, 212.7687) (1409.4777, 212.7669) knots 0 0 0 0 0.099955 0.197913 0.296297 0.397293 0.447322 0.494452 0.540469 0.583967 0.626164 0.667125 0.707869 0.748419 0.824293 0.891081 0.948861 1 1 1 1
  spline B1012 degree 3 poles (1409.4777, 212.7669) (1409.5071, 212.7654) (1409.5657, 212.7623) (1409.6514, 212.7386) (1409.7333, 212.6992) (1409.8097, 212.646) (1409.8781, 212.5818) (1409.9324, 212.5076) (1409.9732, 212.426) (1409.9987, 212.3359) (1410.0089, 212.2372) (1410.0065, 212.1294) (1409.9906, 212.012) (1409.9704, 211.9318) (1409.9598, 211.8897) knots 0 0 0 0 0.074711 0.148925 0.224622 0.305053 0.384983 0.462271 0.537955 0.615945 0.699161 0.78958 0.889682 1 1 1 1
  spline B1013 degree 3 poles (1409.9598, 211.8897) (1409.9424, 211.8569) (1409.9095, 211.7949) (1409.8544, 211.7118) (1409.798, 211.6441) (1409.739, 211.5901) (1409.6734, 211.549) (1409.599, 211.5189) (1409.5152, 211.4969) (1409.4395, 211.4866) (1409.3759, 211.4831) (1409.3277, 211.4874) (1409.2803, 211.4959) (1409.2336, 211.5091) (1409.1884, 211.5296) (1409.1432, 211.5531) (1409.0999, 211.5837) (1409.0573, 211.6176) (1409.0174, 211.6556) (1408.9813, 211.6966) (1408.9504, 211.7405) (1408.9222, 211.7859) (1408.9009, 211.8351) (1408.882, 211.8858) (1408.8693, 211.9395) (1408.8638, 211.9763) (1408.8611, 211.995) knots 0 0 0 0 0.072088 0.13635 0.193046 0.242774 0.290958 0.342422 0.398113 0.458831 0.490394 0.521614 0.55238 0.583918 0.615557 0.64848 0.682655 0.71825 0.754239 0.789406 0.824064 0.858392 0.893019 0.927868 0.96336 1 1 1 1
  spline B1014 degree 3 poles (1418.1328, 211.2967) (1418.1321, 211.2836) (1418.1279, 211.2163) (1418.1138, 211.0973) (1418.0832, 210.9421) (1418.0481, 210.8182) (1418.0129, 210.7251) (1417.9828, 210.6614) (1417.9494, 210.6034) (1417.9115, 210.5519) (1417.8703, 210.5067) (1417.8258, 210.4672) (1417.7774, 210.4338) (1417.7259, 210.4068) (1417.6727, 210.3864) (1417.6189, 210.3739) (1417.5653, 210.3691) (1417.512, 210.3732) (1417.4593, 210.3851) (1417.407, 210.405) (1417.3547, 210.4324) (1417.3037, 210.4684) (1417.2542, 210.5112) (1417.2082, 210.5615) (1417.1658, 210.6184) (1417.1272, 210.6822) (1417.0924, 210.7529) (1417.0614, 210.8306) (1417.0333, 210.9146) (1417.0097, 211.0053) (1416.9897, 211.1007) (1416.974, 211.2) (1416.9634, 211.3026) (1416.9557, 211.4085) (1416.9545, 211.5178) (1416.9559, 211.6303) (1416.9636, 211.746) (1416.9707, 211.8242) (1416.975, 211.8637) knots 0 0 0 0 0.006629 0.034142 0.06066 0.086712 0.099288 0.11107 0.122383 0.13314 0.143395 0.153348 0.163211 0.173128 0.18275 0.191988 0.20102 0.209935 0.218934 0.228312 0.238228 0.248793 0.259841 0.271336 0.283255 0.295716 0.309067 0.32315 0.338074 0.353967 0.370563 0.387452 0.404893 0.422824 0.441265 0.460255 0.479829 0.5 0.5 0.5 0.5
  spline B1015 degree 3 poles (1416.975, 211.8637) (1416.9793, 211.9026) (1416.9889, 211.978) (1417.0074, 212.0869) (1417.0301, 212.1877) (1417.0563, 212.2805) (1417.0847, 212.3659) (1417.1189, 212.4427) (1417.1558, 212.512) (1417.196, 212.5735) (1417.2398, 212.6266) (1417.2844, 212.6732) (1417.3311, 212.7123) (1417.3799, 212.7434) (1417.4301, 212.768) (1417.4823, 212.7843) (1417.5361, 212.7937) (1417.591, 212.7947) (1417.6451, 212.789) (1417.6974, 212.7765) (1417.7467, 212.7571) (1417.7931, 212.7304) (1417.8368, 212.6973) (1417.8771, 212.6563) (1417.9149, 212.6093) (1417.9615, 212.5376) (1418.0109, 212.4397) (1418.0582, 212.3152) (1418.0923, 212.184) (1418.1113, 212.0457) (1418.1217, 211.9009) (1418.1307, 211.749) (1418.1344, 211.5895) (1418.1372, 211.438) (1418.1351, 211.3394) (1418.1328, 211.2967) knots 0.5 0.5 0.5 0.5 0.519807 0.538519 0.555959 0.57215 0.587352 0.601505 0.614714 0.627073 0.638695 0.649561 0.659693 0.669466 0.678842 0.687936 0.697066 0.706398 0.71567 0.724588 0.733555 0.742404 0.751645 0.761269 0.771416 0.782192 0.804526 0.826826 0.849613 0.873019 0.897465 0.923187 0.950087 0.978296 1 1 1 1
  spline B1016 degree 3 poles (1401.9361, 212.3163) (1401.9353, 212.2997) (1401.9323, 212.2662) (1401.9235, 212.2166) (1401.9096, 212.1685) (1401.8921, 212.1217) (1401.8693, 212.0772) (1401.8424, 212.0345) (1401.8113, 211.9943) (1401.776, 211.9572) (1401.7358, 211.9253) (1401.6919, 211.8973) (1401.643, 211.8759) (1401.5905, 211.8578) (1401.5338, 211.8457) (1401.4729, 211.8388) (1401.4092, 211.8362) (1401.3456, 211.8389) (1401.2849, 211.8456) (1401.2286, 211.8579) (1401.1771, 211.8756) (1401.1296, 211.8975) (1401.0872, 211.9253) (1401.0483, 211.9569) (1401.0053, 212.0065) (1400.9605, 212.0722) (1400.9198, 212.1552) (1400.8959, 212.2411) (1400.8909, 212.2993) (1400.8907, 212.3283) knots 0 0 0 0 0.015616 0.03152 0.047152 0.062588 0.078311 0.093928 0.109862 0.125958 0.141858 0.157928 0.174662 0.19182 0.209916 0.228947 0.249284 0.269622 0.288653 0.306551 0.323516 0.339697 0.355423 0.371009 0.386552 0.41682 0.445451 0.472863 0.5 0.5 0.5 0.5
  spline B1017 degree 3 poles (1400.8907, 212.3283) (1400.8905, 212.3568) (1400.8946, 212.4126) (1400.9149, 212.4935) (1400.9496, 212.5683) (1400.9881, 212.6262) (1401.0266, 212.6678) (1401.0611, 212.6954) (1401.1, 212.7192) (1401.1438, 212.7397) (1401.1923, 212.7561) (1401.2454, 212.77) (1401.3032, 212.7795) (1401.3645, 212.7849) (1401.4263, 212.7877) (1401.486, 212.7865) (1401.5425, 212.7813) (1401.5955, 212.7724) (1401.6455, 212.7593) (1401.692, 212.7425) (1401.7357, 212.7225) (1401.7751, 212.6975) (1401.8114, 212.6698) (1401.8424, 212.6374) (1401.8704, 212.6025) (1401.8921, 212.5628) (1401.9108, 212.5206) (1401.9234, 212.4743) (1401.9327, 212.4248) (1401.9369, 212.3724) (1401.937, 212.3358) (1401.9361, 212.3171) (1401.9361, 212.3163) knots 0.5 0.5 0.5 0.5 0.526699 0.552279 0.577741 0.603781 0.617152 0.630735 0.64506 0.659878 0.676009 0.693013 0.711355 0.730949 0.750677 0.769377 0.786929 0.803834 0.819804 0.83536 0.850178 0.864783 0.87897 0.892909 0.906811 0.920825 0.935208 0.950002 0.965706 0.98243 0.999297 1 1 1 1
  spline B1018 degree 3 poles (1254.3079, 211.995) (1254.3047, 212.0327) (1254.2985, 212.1073) (1254.3103, 212.219) (1254.3351, 212.3289) (1254.3705, 212.4165) (1254.4033, 212.4838) (1254.4319, 212.5297) (1254.4618, 212.5718) (1254.4949, 212.609) (1254.5289, 212.6428) (1254.5669, 212.6703) (1254.6054, 212.6959) (1254.6598, 212.7199) (1254.7245, 212.7448) (1254.7981, 212.7628) (1254.8641, 212.7726) (1254.9052, 212.7687) (1254.9245, 212.7669) knots 0 0 0 0 0.099955 0.197913 0.296297 0.397293 0.447322 0.494452 0.540469 0.583967 0.626164 0.667125 0.707869 0.748419 0.824293 0.891081 0.948861 1 1 1 1
  spline B1019 degree 3 poles (1254.9245, 212.7669) (1254.9539, 212.7654) (1255.0124, 212.7623) (1255.0982, 212.7386) (1255.1801, 212.6992) (1255.2565, 212.646) (1255.3249, 212.5818) (1255.3792, 212.5076) (1255.42, 212.426) (1255.4454, 212.3359) (1255.4557, 212.2372) (1255.4533, 212.1294) (1255.4374, 212.012) (1255.4172, 211.9318) (1255.4066, 211.8897) knots 0 0 0 0 0.074711 0.148925 0.224622 0.305053 0.384983 0.462271 0.537955 0.615945 0.699161 0.78958 0.889682 1 1 1 1
  spline B1020 degree 3 poles (1255.4066, 211.8897) (1255.3892, 211.8569) (1255.3563, 211.7949) (1255.3012, 211.7118) (1255.2448, 211.6441) (1255.1858, 211.5901) (1255.1202, 211.549) (1255.0458, 211.5189) (1254.9619, 211.4969) (1254.8863, 211.4866) (1254.8226, 211.4831) (1254.7745, 211.4874) (1254.7271, 211.4959) (1254.6803, 211.5091) (1254.6352, 211.5296) (1254.59, 211.5531) (1254.5467, 211.5837) (1254.5041, 211.6176) (1254.4642, 211.6556) (1254.4281, 211.6966) (1254.3972, 211.7405) (1254.369, 211.7859) (1254.3476, 211.8351) (1254.3288, 211.8858) (1254.3161, 211.9395) (1254.3106, 211.9763) (1254.3079, 211.995) knots 0 0 0 0 0.072088 0.13635 0.193046 0.242774 0.290958 0.342422 0.398113 0.458831 0.490394 0.521614 0.55238 0.583918 0.615557 0.64848 0.682655 0.71825 0.754239 0.789406 0.824064 0.858392 0.893019 0.927868 0.96336 1 1 1 1
  spline B1021 degree 3 poles (1262.4394, 212.3283) (1262.4392, 212.3568) (1262.4433, 212.4126) (1262.4636, 212.4935) (1262.4982, 212.5683) (1262.5368, 212.6262) (1262.5753, 212.6678) (1262.6097, 212.6954) (1262.6487, 212.7192) (1262.6924, 212.7397) (1262.7409, 212.7561) (1262.7941, 212.77) (1262.8519, 212.7795) (1262.9132, 212.7849) (1262.975, 212.7877) (1263.0347, 212.7865) (1263.0911, 212.7813) (1263.1442, 212.7724) (1263.1942, 212.7593) (1263.2407, 212.7425) (1263.2844, 212.7225) (1263.3237, 212.6975) (1263.36, 212.6698) (1263.3911, 212.6374) (1263.4191, 212.6025) (1263.4408, 212.5628) (1263.4595, 212.5206) (1263.4721, 212.4743) (1263.4814, 212.4248) (1263.4856, 212.3724) (1263.4856, 212.3358) (1263.4848, 212.3171) (1263.4848, 212.3163) knots 0.5 0.5 0.5 0.5 0.526699 0.552279 0.577741 0.603781 0.617152 0.630735 0.64506 0.659878 0.676009 0.693013 0.711355 0.730949 0.750677 0.769377 0.786929 0.803834 0.819804 0.83536 0.850178 0.864783 0.87897 0.892909 0.906811 0.920825 0.935208 0.950002 0.965706 0.98243 0.999297 1 1 1 1
  spline B1022 degree 3 poles (1263.4848, 212.3163) (1263.484, 212.2997) (1263.481, 212.2662) (1263.4721, 212.2166) (1263.4582, 212.1685) (1263.4408, 212.1217) (1263.418, 212.0772) (1263.3911, 212.0345) (1263.36, 211.9943) (1263.3247, 211.9572) (1263.2844, 211.9253) (1263.2406, 211.8973) (1263.1916, 211.8759) (1263.1392, 211.8578) (1263.0825, 211.8457) (1263.0215, 211.8388) (1262.9579, 211.8362) (1262.8942, 211.8389) (1262.8335, 211.8456) (1262.7773, 211.8579) (1262.7257, 211.8756) (1262.6783, 211.8975) (1262.6359, 211.9253) (1262.5969, 211.9569) (1262.554, 212.0065) (1262.5092, 212.0722) (1262.4684, 212.1552) (1262.4446, 212.2411) (1262.4395, 212.2993) (1262.4394, 212.3283) knots 0 0 0 0 0.015616 0.03152 0.047152 0.062588 0.078311 0.093928 0.109862 0.125958 0.141858 0.157928 0.174662 0.19182 0.209916 0.228947 0.249284 0.269622 0.288653 0.306551 0.323516 0.339697 0.355423 0.371009 0.386552 0.41682 0.445451 0.472863 0.5 0.5 0.5 0.5
  spline B1023 degree 3 poles (1263.5748, 210.8617) (1263.5738, 210.8535) (1263.5679, 210.8124) (1263.5503, 210.7385) (1263.52, 210.6588) (1263.4881, 210.5978) (1263.4585, 210.5561) (1263.425, 210.5183) (1263.3866, 210.4854) (1263.3439, 210.4564) (1263.2968, 210.4323) (1263.245, 210.413) (1263.1711, 210.3926) (1263.0762, 210.3769) (1262.9628, 210.3678) (1262.8514, 210.3717) (1262.7612, 210.3853) (1262.6921, 210.4013) (1262.6446, 210.4174) (1262.6014, 210.4378) (1262.5621, 210.4613) (1262.5266, 210.4878) (1262.4958, 210.5187) (1262.4698, 210.5535) (1262.4401, 210.6044) (1262.4123, 210.6742) (1262.3871, 210.7634) (1262.3768, 210.8597) (1262.3752, 210.9259) (1262.377, 210.9599) knots 0 0 0 0 0.006731 0.033655 0.061553 0.075719 0.089481 0.102935 0.116654 0.130461 0.144701 0.159566 0.175272 0.206881 0.237575 0.267497 0.297201 0.311494 0.325068 0.337894 0.350203 0.36213 0.373822 0.385502 0.397328 0.421536 0.446329 0.47238 0.5 0.5 0.5 0.5
  spline B1024 degree 3 poles (1262.377, 210.9599) (1262.3779, 210.977) (1262.3809, 211.0108) (1262.3889, 211.0606) (1262.4029, 211.1078) (1262.4203, 211.1534) (1262.4433, 211.1961) (1262.4701, 211.2368) (1262.5015, 211.2753) (1262.5489, 211.3236) (1262.6172, 211.3756) (1262.7096, 211.424) (1262.8124, 211.4557) (1262.9224, 211.4714) (1263.0351, 211.4712) (1263.1462, 211.4523) (1263.2527, 211.4139) (1263.3358, 211.3671) (1263.3969, 211.3222) (1263.4387, 211.2868) (1263.475, 211.2488) (1263.505, 211.2085) (1263.5314, 211.1673) (1263.5504, 211.1231) (1263.566, 211.0777) (1263.5774, 211.0141) (1263.5816, 210.9417) (1263.5777, 210.8854) (1263.5748, 210.8617) knots 0.5 0.5 0.5 0.5 0.513951 0.527514 0.540876 0.55391 0.567051 0.580127 0.593506 0.607313 0.635038 0.662812 0.691575 0.721975 0.752759 0.782749 0.813017 0.844284 0.859765 0.874609 0.888669 0.902355 0.915389 0.928302 0.941263 0.954339 0.980597 1 1 1 1
  spline B1025 degree 3 poles (1249.4904, 211.2967) (1249.4897, 211.2836) (1249.4855, 211.2163) (1249.4715, 211.0973) (1249.4409, 210.9421) (1249.4058, 210.8182) (1249.3706, 210.7251) (1249.3404, 210.6614) (1249.307, 210.6034) (1249.2692, 210.5519) (1249.2279, 210.5067) (1249.1835, 210.4672) (1249.135, 210.4338) (1249.0835, 210.4068) (1249.0303, 210.3864) (1248.9766, 210.3739) (1248.9229, 210.3691) (1248.8697, 210.3732) (1248.817, 210.3851) (1248.7646, 210.405) (1248.7123, 210.4324) (1248.6614, 210.4684) (1248.6118, 210.5112) (1248.5658, 210.5615) (1248.5235, 210.6184) (1248.4849, 210.6822) (1248.45, 210.7529) (1248.4191, 210.8306) (1248.3909, 210.9146) (1248.3674, 211.0053) (1248.3474, 211.1007) (1248.3316, 211.2) (1248.321, 211.3026) (1248.3134, 211.4085) (1248.3121, 211.5178) (1248.3135, 211.6303) (1248.3213, 211.746) (1248.3284, 211.8242) (1248.3327, 211.8637) knots 0 0 0 0 0.006629 0.034142 0.06066 0.086712 0.099288 0.11107 0.122383 0.13314 0.143395 0.153348 0.163211 0.173128 0.18275 0.191988 0.20102 0.209935 0.218934 0.228312 0.238228 0.248793 0.259841 0.271336 0.283255 0.295716 0.309067 0.32315 0.338074 0.353967 0.370563 0.387452 0.404893 0.422824 0.441265 0.460255 0.479829 0.5 0.5 0.5 0.5
  spline B1026 degree 3 poles (1248.3327, 211.8637) (1248.3369, 211.9026) (1248.3465, 211.978) (1248.3651, 212.0869) (1248.3877, 212.1877) (1248.4139, 212.2805) (1248.4424, 212.3659) (1248.4765, 212.4427) (1248.5134, 212.512) (1248.5536, 212.5735) (1248.5975, 212.6266) (1248.6421, 212.6732) (1248.6887, 212.7123) (1248.7376, 212.7434) (1248.7878, 212.768) (1248.8399, 212.7843) (1248.8937, 212.7937) (1248.9486, 212.7947) (1249.0027, 212.789) (1249.055, 212.7765) (1249.1043, 212.7571) (1249.1507, 212.7304) (1249.1944, 212.6973) (1249.2347, 212.6563) (1249.2725, 212.6093) (1249.3192, 212.5376) (1249.3686, 212.4397) (1249.4158, 212.3152) (1249.4499, 212.184) (1249.4689, 212.0457) (1249.4794, 211.9009) (1249.4884, 211.749) (1249.4921, 211.5895) (1249.4949, 211.438) (1249.4927, 211.3394) (1249.4904, 211.2967) knots 0.5 0.5 0.5 0.5 0.519807 0.538519 0.555959 0.57215 0.587352 0.601505 0.614714 0.627073 0.638695 0.649561 0.659693 0.669466 0.678842 0.687936 0.697066 0.706398 0.71567 0.724588 0.733555 0.742404 0.751645 0.761269 0.771416 0.782192 0.804526 0.826826 0.849613 0.873019 0.897465 0.923187 0.950087 0.978296 1 1 1 1
  spline B1027 degree 3 poles (1402.0261, 210.8617) (1402.0251, 210.8535) (1402.0193, 210.8124) (1402.0016, 210.7385) (1401.9713, 210.6588) (1401.9394, 210.5978) (1401.9098, 210.5561) (1401.8763, 210.5183) (1401.8379, 210.4854) (1401.7953, 210.4564) (1401.7481, 210.4323) (1401.6963, 210.413) (1401.6224, 210.3926) (1401.5275, 210.3769) (1401.4141, 210.3678) (1401.3027, 210.3717) (1401.2126, 210.3853) (1401.1434, 210.4013) (1401.0959, 210.4174) (1401.0527, 210.4378) (1401.0135, 210.4613) (1400.978, 210.4878) (1400.9471, 210.5187) (1400.9211, 210.5535) (1400.8915, 210.6044) (1400.8636, 210.6742) (1400.8384, 210.7634) (1400.8281, 210.8597) (1400.8266, 210.9259) (1400.8283, 210.9599) knots 0 0 0 0 0.006731 0.033655 0.061553 0.075719 0.089481 0.102935 0.116654 0.130461 0.144701 0.159566 0.175272 0.206881 0.237575 0.267497 0.297201 0.311494 0.325068 0.337894 0.350203 0.36213 0.373822 0.385502 0.397328 0.421536 0.446329 0.47238 0.5 0.5 0.5 0.5
  spline B1028 degree 3 poles (1400.8283, 210.9599) (1400.8292, 210.977) (1400.8322, 211.0108) (1400.8402, 211.0606) (1400.8543, 211.1078) (1400.8716, 211.1534) (1400.8946, 211.1961) (1400.9214, 211.2368) (1400.9529, 211.2753) (1401.0003, 211.3236) (1401.0686, 211.3756) (1401.1609, 211.424) (1401.2637, 211.4557) (1401.3738, 211.4714) (1401.4865, 211.4712) (1401.5975, 211.4523) (1401.7041, 211.4139) (1401.7871, 211.3671) (1401.8483, 211.3222) (1401.89, 211.2868) (1401.9263, 211.2488) (1401.9563, 211.2085) (1401.9828, 211.1673) (1402.0018, 211.1231) (1402.0173, 211.0777) (1402.0287, 211.0141) (1402.0329, 210.9417) (1402.029, 210.8854) (1402.0261, 210.8617) knots 0.5 0.5 0.5 0.5 0.513951 0.527514 0.540876 0.55391 0.567051 0.580127 0.593506 0.607313 0.635038 0.662812 0.691575 0.721975 0.752759 0.782749 0.813017 0.844284 0.859765 0.874609 0.888669 0.902355 0.915389 0.928302 0.941263 0.954339 0.980597 1 1 1 1
  spline B1029 degree 3 poles (1385.8652, 211.5398) (1385.8761, 211.5294) (1385.9012, 211.5025) (1385.9365, 211.4545) (1385.9672, 211.3934) (1385.9922, 211.3259) (1386.0095, 211.2511) (1386.0197, 211.1692) (1386.0223, 211.0823) (1386.02, 210.9948) (1386.0118, 210.9107) (1385.9972, 210.8321) (1385.9782, 210.759) (1385.9534, 210.6908) (1385.9222, 210.6286) (1385.8857, 210.5717) (1385.8439, 210.5207) (1385.7979, 210.4762) (1385.7489, 210.4373) (1385.6968, 210.4056) (1385.6422, 210.3798) (1385.5847, 210.3606) (1385.5241, 210.3496) (1385.461, 210.3431) (1385.3962, 210.3452) (1385.3316, 210.3512) (1385.2695, 210.363) (1385.2108, 210.3797) (1385.1546, 210.3988) (1385.1031, 210.4259) (1385.0541, 210.4555) (1385.0082, 210.4899) (1384.9808, 210.5166) (1384.9675, 210.5304) knots 0 0 0 0 0.01083 0.026523 0.042913 0.060107 0.078454 0.098345 0.119658 0.141279 0.161584 0.18069 0.198999 0.216193 0.233002 0.249205 0.265006 0.280511 0.295455 0.310147 0.324509 0.33902 0.353854 0.368955 0.384775 0.40067 0.415812 0.430441 0.444757 0.458625 0.472403 0.486154 0.5 0.5 0.5 0.5
  spline B1030 degree 3 poles (1384.9675, 210.5304) (1384.9542, 210.5442) (1384.9286, 210.5723) (1384.8953, 210.6185) (1384.866, 210.6671) (1384.8412, 210.7187) (1384.821, 210.7728) (1384.8053, 210.8298) (1384.7944, 210.8896) (1384.786, 210.9722) (1384.7858, 211.0764) (1384.8033, 211.2) (1384.8398, 211.32) (1384.8841, 211.4158) (1384.9284, 211.4876) (1384.9668, 211.5361) (1385.0104, 211.5782) (1385.0584, 211.6147) (1385.1115, 211.6449) (1385.1696, 211.6681) (1385.232, 211.6866) (1385.2983, 211.6977) (1385.3659, 211.7034) (1385.4328, 211.704) (1385.4982, 211.7001) (1385.5614, 211.6882) (1385.6236, 211.6731) (1385.6839, 211.6514) (1385.7428, 211.6247) (1385.799, 211.5925) (1385.8396, 211.5633) (1385.8605, 211.5444) (1385.8652, 211.5398) knots 0.5 0.5 0.5 0.5 0.513864 0.527427 0.541125 0.554854 0.568729 0.582863 0.597515 0.612631 0.642856 0.6726 0.702526 0.733283 0.748622 0.763444 0.777841 0.792375 0.806963 0.821853 0.837514 0.853889 0.870393 0.886524 0.902223 0.917646 0.932991 0.948445 0.963933 0.979648 0.995215 1 1 1 1
  spline B1031 degree 3 poles (1279.6177, 211.5398) (1279.6285, 211.5294) (1279.6536, 211.5025) (1279.6889, 211.4545) (1279.7196, 211.3934) (1279.7447, 211.3259) (1279.762, 211.2511) (1279.7721, 211.1692) (1279.7747, 211.0823) (1279.7724, 210.9948) (1279.7642, 210.9107) (1279.7497, 210.8321) (1279.7306, 210.759) (1279.7058, 210.6908) (1279.6746, 210.6286) (1279.6382, 210.5717) (1279.5964, 210.5207) (1279.5503, 210.4762) (1279.5013, 210.4373) (1279.4492, 210.4056) (1279.3947, 210.3798) (1279.3371, 210.3606) (1279.2765, 210.3496) (1279.2135, 210.3431) (1279.1486, 210.3452) (1279.0841, 210.3512) (1279.0219, 210.363) (1278.9632, 210.3797) (1278.907, 210.3988) (1278.8556, 210.4259) (1278.8065, 210.4555) (1278.7606, 210.4899) (1278.7333, 210.5166) (1278.7199, 210.5304) knots 0 0 0 0 0.01083 0.026523 0.042913 0.060107 0.078454 0.098345 0.119658 0.141279 0.161584 0.18069 0.198999 0.216193 0.233002 0.249205 0.265006 0.280511 0.295455 0.310147 0.324509 0.33902 0.353854 0.368955 0.384775 0.40067 0.415812 0.430441 0.444757 0.458625 0.472403 0.486154 0.5 0.5 0.5 0.5
  spline B1032 degree 3 poles (1278.7199, 210.5304) (1278.7066, 210.5442) (1278.681, 210.5723) (1278.6477, 210.6185) (1278.6184, 210.6671) (1278.5937, 210.7187) (1278.5735, 210.7728) (1278.5578, 210.8298) (1278.5469, 210.8896) (1278.5384, 210.9722) (1278.5383, 211.0764) (1278.5557, 211.2) (1278.5922, 211.32) (1278.6365, 211.4158) (1278.6808, 211.4876) (1278.7192, 211.5361) (1278.7629, 211.5782) (1278.8109, 211.6147) (1278.864, 211.6449) (1278.9221, 211.6681) (1278.9844, 211.6866) (1279.0508, 211.6977) (1279.1184, 211.7034) (1279.1852, 211.704) (1279.2506, 211.7001) (1279.3139, 211.6882) (1279.376, 211.6731) (1279.4364, 211.6514) (1279.4952, 211.6247) (1279.5514, 211.5925) (1279.5921, 211.5633) (1279.6129, 211.5444) (1279.6177, 211.5398) knots 0.5 0.5 0.5 0.5 0.513864 0.527427 0.541125 0.554854 0.568729 0.582863 0.597515 0.612631 0.642856 0.6726 0.702526 0.733283 0.748622 0.763444 0.777841 0.792375 0.806963 0.821853 0.837514 0.853889 0.870393 0.886524 0.902223 0.917646 0.932991 0.948445 0.963933 0.979648 0.995215 1 1 1 1
  spline B1033 degree 3 poles (1341.8641, 211.4094) (1341.8641, 211.4094) (1341.8703, 211.4498) (1341.8786, 211.5231) (1341.9447, 211.5918) (1341.9979, 211.645) (1342.048, 211.6909) (1342.1323, 211.7067) (1342.2206, 211.7067) (1342.3078, 211.6876) (1342.3501, 211.6408) (1342.3816, 211.599) (1342.3953, 211.5167) (1342.4027, 211.4531) (1342.4057, 211.4094) knots 4.036179 4.036179 4.036179 4.036179 4.036465 4.523969 4.895381 5.153022 5.450676 5.691954 6.165787 6.54029 6.708798 6.920788 7.164682 7.7002 7.7002 7.7002 7.7002
  spline B1034 degree 3 poles (1551.2149, 143.1154) (1551.202, 142.9536) (1551.1761, 142.6308) (1550.8905, 142.2553) (1550.5097, 142.0731) (1550.2568, 142.0584) (1550.1301, 142.0511) knots 0 0 0 0 0.280177 0.55896 0.779151 1 1 1 1
  spline B1035 degree 3 poles (1550.1301, 144.1798) (1550.2921, 144.1684) (1550.615, 144.1459) (1550.9967, 143.871) (1551.1913, 143.4953) (1551.2071, 143.2422) (1551.2149, 143.1154) knots 0 0 0 0 0.280395 0.559142 0.779226 1 1 1 1
  spline B1036 degree 3 poles (1550.4396, 97.263) (1550.6928, 97.2507) (1551.1969, 97.2264) (1551.7971, 96.9288) (1552.0728, 96.4899) (1552.1371, 95.9759) (1552.0294, 95.608) (1551.9576, 95.3628) knots 0 0 0 0 0.250794 0.499399 0.624267 0.749544 1 1 1 1
  spline B1037 degree 3 poles (1551.9576, 95.3628) (1551.8634, 95.1384) (1551.6752, 94.6899) (1551.0752, 94.0373) (1550.4958, 93.7956) (1550.1425, 93.6482) knots 0 0 0 0 0.280886 0.56138 1 1 1 1
  spline B1038 degree 3 poles (1547.4693, 141.0277) (1547.5655, 141.037) (1547.7573, 141.0557) (1547.971, 141.2425) (1548.0537, 141.4781) (1548.0598, 141.628) (1548.0629, 141.7032) knots 0 0 0 0 0.27982 0.558313 0.778796 1 1 1 1
  spline B1039 degree 3 poles (1546.8758, 141.7032) (1546.88, 141.6072) (1546.8885, 141.4162) (1547.025, 141.1736) (1547.2438, 141.0449) (1547.3941, 141.0335) (1547.4693, 141.0277) knots 0 0 0 0 0.281013 0.559492 0.779461 1 1 1 1
  spline B1040 degree 3 poles (1547.4693, 140.6388) (1547.3073, 140.6472) (1546.9851, 140.6638) (1546.5987, 140.9387) (1546.4265, 141.3245) (1546.4122, 141.5768) (1546.405, 141.7032) knots 0 0 0 0 0.280809 0.558537 0.778939 1 1 1 1
  spline B1041 degree 3 poles (1548.5336, 141.7032) (1548.5225, 141.5421) (1548.5002, 141.2211) (1548.2373, 140.8265) (1547.8478, 140.6564) (1547.5957, 140.6447) (1547.4693, 140.6388) knots 0 0 0 0 0.280477 0.559028 0.779014 1 1 1 1
  spline B1042 degree 3 poles (1549.4784, 94.3792) (1549.6456, 94.3963) (1549.9799, 94.4305) (1550.5388, 94.7145) (1550.7251, 95.1173) (1550.8387, 95.3628) knots 0 0 0 0 0.281026 0.561802 1 1 1 1
  spline B1043 degree 3 poles (1550.8387, 95.3628) (1550.8779, 95.5015) (1550.9367, 95.7096) (1550.889, 95.996) (1550.7318, 96.2436) (1550.3729, 96.3701) (1550.0915, 96.3784) (1549.95, 96.3826) knots 0 0 0 0 0.250283 0.375557 0.500424 0.748735 1 1 1 1
  spline B1044 degree 3 poles (1550.0073, 142.44) (1550.1153, 142.4444) (1550.33, 142.4531) (1550.6237, 142.5902) (1550.7346, 142.861) (1550.741, 143.0304) (1550.7442, 143.1154) knots 0 0 0 0 0.281273 0.559342 0.778877 1 1 1 1
  spline B1045 degree 3 poles (1550.7442, 143.1154) (1550.7414, 143.2253) (1550.7359, 143.4429) (1550.4749, 143.7739) (1550.1853, 143.7844) (1550.0073, 143.7909) knots 0 0 0 0 0.282452 0.559257 1 1 1 1
  spline B1046 degree 3 poles (1126.2149, 143.1154) (1126.202, 142.9536) (1126.1761, 142.6308) (1125.8905, 142.2553) (1125.5097, 142.0731) (1125.2568, 142.0584) (1125.1301, 142.0511) knots 0 0 0 0 0.280175 0.558961 0.779147 1 1 1 1
  spline B1047 degree 3 poles (1125.1301, 144.1798) (1125.2921, 144.1684) (1125.615, 144.1459) (1125.9967, 143.871) (1126.1913, 143.4953) (1126.207, 143.2422) (1126.2149, 143.1154) knots 0 0 0 0 0.280399 0.559145 0.779227 1 1 1 1
  spline B1048 degree 3 poles (1122.4693, 141.0277) (1122.5655, 141.037) (1122.7573, 141.0557) (1122.971, 141.2425) (1123.0537, 141.4781) (1123.0598, 141.628) (1123.0629, 141.7032) knots 0 0 0 0 0.279825 0.558317 0.778797 1 1 1 1
  spline B1049 degree 3 poles (1121.8758, 141.7032) (1121.88, 141.6072) (1121.8885, 141.4162) (1122.025, 141.1736) (1122.2438, 141.0449) (1122.3941, 141.0335) (1122.4693, 141.0277) knots 0 0 0 0 0.281016 0.559496 0.779459 1 1 1 1
  spline B1050 degree 3 poles (1122.4693, 140.6388) (1122.3073, 140.6472) (1121.9851, 140.6638) (1121.5987, 140.9387) (1121.4265, 141.3245) (1121.4122, 141.5768) (1121.405, 141.7032) knots 0 0 0 0 0.280805 0.558537 0.778939 1 1 1 1
  spline B1051 degree 3 poles (1123.5337, 141.7032) (1123.5225, 141.5421) (1123.5002, 141.2211) (1123.2373, 140.8264) (1122.8478, 140.6564) (1122.5957, 140.6447) (1122.4693, 140.6388) knots 0 0 0 0 0.280476 0.559026 0.779015 1 1 1 1
  spline B1052 degree 3 poles (1125.7442, 143.1154) (1125.7414, 143.2253) (1125.7359, 143.4429) (1125.4749, 143.7739) (1125.1853, 143.7844) (1125.0073, 143.7909) knots 0 0 0 0 0.282452 0.559257 1 1 1 1
  spline B1053 degree 3 poles (1125.0073, 142.44) (1125.1153, 142.4444) (1125.33, 142.4531) (1125.6237, 142.5902) (1125.7346, 142.861) (1125.741, 143.0304) (1125.7442, 143.1154) knots 0 0 0 0 0.281273 0.559338 0.778876 1 1 1 1
  line B1054 (421.5482, 63.335) -> (424.5, 63.335)
  line B1055 (417.5, 56.35) -> (417.5, 59.2868)
  line B1056 (423.6081, 62.6502) -> (423.9282, 61.335)
  line B1057 (423.6183, 62.6999) -> (423.6081, 62.6502)
  line B1058 (418.1848, 57.2269) -> (418.1351, 57.2167)
  line B1059 (419.5, 56.9067) -> (418.1848, 57.2269)
  line B1060 (423.6081, 62.6502) -> (423.6081, 61.335)
  line B1061 (419.5, 57.2269) -> (418.1848, 57.2269)
  line B1062 (422.0768, 164.5367) -> (411.3232, 164.5367)
  line B1063 (411.2891, 164.1797) -> (410.0601, 164.1797)
  line B1064 (409.742, 173.2214) -> (405.6, 173.2214)
  line B1065 (405.6, 173.2214) -> (405.6, 177.5)
  line B1066 (405.6, 177.5) -> (392.6, 177.5)
  line B1067 (392.6, 177.5) -> (392.6, 173.2214)
  line B1068 (392.6, 173.2214) -> (390.2868, 173.2214)
  line B1069 (421.7157, 62.6999) -> (423.6183, 62.6999)
  line B1070 (418.1351, 57.2167) -> (418.1351, 59.1193)
  line B1071 (418.5568, 59.4902) -> (419.5, 59.4902)
  line B1072 (421.3448, 61.335) -> (421.3448, 62.2781)
  line B1073 (418.0272, 59.7504) -> (419.5, 59.7504)
  line B1074 (421.0846, 61.335) -> (421.0846, 62.8078)
  line B1075 (422.1397, 163.2868) -> (422.1397, 158.9231)
  line B1076 (411.2603, 158.9231) -> (411.2603, 163.2868)
  line B1077 (409.5752, 163.2868) -> (409.5752, 156.9754)
  line B1078 (420.9769, 157.7603) -> (412.4231, 157.7603)
  line B1079 (410.0745, 83.0114) -> (410.0745, 83.1113)
  line B1080 (409.5752, 143.0246) -> (409.5752, 96.9754)
  line B1081 (420.9004, 157.9909) -> (412.4996, 157.9909)
  line B1082 (409.4218, 96.7067) -> (409.675, 96.8755)
  line B1083 (409.675, 83.1245) -> (409.4218, 83.2933)
  line B1084 (409.5752, 156.9754) -> (409.3219, 156.8067)
  line B1085 (409.3219, 143.1933) -> (409.5752, 143.0246)
  line B1086 (408.9711, 56.35) -> (408.9711, 163.665)
  line B1087 (408.9711, 163.665) -> (409.2424, 168.8412)
  line B1088 (409.3068, 156.5069) -> (409.3068, 143.4931)
  line B1089 (409.2726, 170.0741) -> (409.2803, 170.3272)
  line B1090 (412.4999, 164.1) -> (420.9001, 164.1)
  line B1091 (412, 163.0683) -> (412, 163.6001)
  line B1092 (411.9817, 163.05) -> (412, 163.0683)
  line B1093 (411.9817, 159.55) -> (411.9817, 163.05)
  line B1094 (412, 159.5317) -> (411.9817, 159.55)
  line B1095 (412, 158.4911) -> (412, 159.5317)
  line B1096 (421.4, 159.5317) -> (421.4, 158.4911)
  line B1097 (421.4183, 159.55) -> (421.4, 159.5317)
  line B1098 (421.4183, 163.05) -> (421.4183, 159.55)
  line B1099 (421.4, 163.0683) -> (421.4183, 163.05)
  line B1100 (421.4, 163.6001) -> (421.4, 163.0683)
  line B1101 (388.7582, 173.1906) -> (388.7637, 170.2965)
  line B1102 (388.7461, 169.4466) -> (388.4661, 164.1031)
  line B1103 (388.4661, 164.1031) -> (388.4661, 143.1612)
  line B1104 (412.252, 159.5317) -> (412.252, 163.0683)
  line B1105 (421.148, 163.0683) -> (421.148, 159.5317)
  line B1106 (421.4, 163.0683) -> (421.148, 163.0683)
  line B1107 (421.148, 159.5317) -> (421.4, 159.5317)
  line B1108 (412, 159.5317) -> (412.252, 159.5317)
  line B1109 (412.252, 163.0683) -> (412, 163.0683)
  line B1110 (396.6757, 174.1853) -> (396.6963, 173.0441)
  line B1111 (396.693, 172.8235) -> (396.6561, 172.254)
  line B1112 (396.6349, 172.0817) -> (396.6, 172)
  line B1113 (401.5651, 172.0817) -> (401.6, 172)
  line B1114 (401.507, 172.8235) -> (401.5438, 172.254)
  line B1115 (401.5242, 174.1853) -> (401.5037, 173.0441)
  line B1116 (396.693, 172.8235) -> (401.507, 172.8235)
  line B1117 (401.5384, 174.5606) -> (396.6615, 174.5606)
  line B1118 (396.6, 176) -> (401.6, 176)
  line B1119 (396.6349, 172.0817) -> (401.5651, 172.0817)
  line B1120 (409.4066, 83.4931) -> (409.4066, 96.5069)
  line B1121 (396.6, 172) -> (401.6, 172)
  line B1122 (390.2922, 170.3272) -> (390.2868, 173.2214)
  line B1123 (392.6, 170.5) -> (405.6, 170.5)
  line B1124 (392.6, 173.2214) -> (392.6, 170.5)
  line B1125 (405.6, 170.5) -> (405.6, 173.2214)
  line B1126 (390.2747, 168.8412) -> (409.2424, 168.8412)
  line B1127 (401.6, 176) -> (405.6, 176)
  line B1128 (405.6, 172) -> (401.6, 172)
  line B1129 (392.6, 176) -> (396.6, 176)
  line B1130 (396.6, 172) -> (392.6, 172)
  line B1131 (390.0034, 163.665) -> (390.2747, 168.8412)
  line B1132 (389.95, 163.7052) -> (390.0034, 163.665)
  line B1133 (408.4334, 144.6834) -> (389.95, 144.6834)
  line B1134 (389.95, 144.6834) -> (389.95, 163.7052)
  line B1135 (389.95, 56.35) -> (389.95, 95.3166)
  line B1136 (389.95, 95.3166) -> (408.4334, 95.3166)
  line B1137 (408.4334, 95.3166) -> (408.4334, 144.6834)
  line B1138 (389.95, 144.6834) -> (388.4661, 143.1612)
  line B1139 (406.8968, 143.1468) -> (408.4334, 144.6834)
  line B1140 (388.4658, 143.1468) -> (406.8968, 143.1468)
  line B1141 (406.8968, 143.1468) -> (406.8968, 96.8532)
  line B1142 (406.8968, 96.8532) -> (408.4334, 95.3166)
  line B1143 (406.8968, 96.8532) -> (388.4658, 96.8532)
  line B1144 (388.4661, 96.8388) -> (389.95, 95.3166)
  line B1145 (388.4661, 96.8388) -> (388.4661, 56.35)
  line B1146 (405.575, 98.1915) -> (402.375, 98.1915)
  line B1147 (393.375, 98.1915) -> (393.375, 96.869)
  line B1148 (402.375, 98.1915) -> (402.375, 96.869)
  line B1149 (405.575, 141.8085) -> (405.575, 98.1915)
  line B1150 (396.575, 98.1915) -> (393.375, 98.1915)
  line B1151 (388.925, 98.1915) -> (388.925, 141.8085)
  line B1152 (392.125, 96.869) -> (392.125, 98.1915)
  line B1153 (402.375, 143.131) -> (402.375, 141.8085)
  line B1154 (388.925, 141.8085) -> (392.125, 141.8085)
  line B1155 (392.125, 141.8085) -> (392.125, 143.131)
  line B1156 (393.375, 143.131) -> (393.375, 141.8085)
  line B1157 (393.375, 141.8085) -> (396.575, 141.8085)
  line B1158 (396.575, 141.8085) -> (396.575, 98.1915)
  line B1159 (392.125, 98.1915) -> (388.925, 98.1915)
  line B1160 (402.375, 141.8085) -> (405.575, 141.8085)
  line B1161 (401.125, 98.1915) -> (397.925, 98.1915)
  line B1162 (397.925, 98.1915) -> (397.925, 141.8085)
  line B1163 (397.925, 141.8085) -> (401.125, 141.8085)
  line B1164 (401.125, 141.8085) -> (401.125, 143.131)
  line B1165 (401.125, 96.869) -> (401.125, 98.1915)
  line B1166 (416.75, 117.6627) -> (418.25, 117.6627)
  line B1167 (418.25, 122.3373) -> (416.75, 122.3373)
  line B1168 (31.4518, 63.335) -> (28.5, 63.335)
  line B1169 (35.5, 56.35) -> (35.5, 59.2868)
  line B1170 (29.3817, 62.6999) -> (29.3919, 62.6502)
  line B1171 (29.3919, 62.6502) -> (29.0717, 61.335)
  line B1172 (33.5, 56.9067) -> (34.8152, 57.2269)
  line B1173 (34.8152, 57.2269) -> (34.8649, 57.2167)
  line B1174 (29.3919, 62.6502) -> (29.3919, 61.335)
  line B1175 (33.5, 57.2269) -> (34.8152, 57.2269)
  line B1176 (60.4, 173.2214) -> (62.7132, 173.2214)
  line B1177 (60.4, 177.5) -> (60.4, 173.2214)
  line B1178 (47.4, 177.5) -> (60.4, 177.5)
  line B1179 (47.4, 173.2214) -> (47.4, 177.5)
  line B1180 (43.2579, 173.2214) -> (47.4, 173.2214)
  line B1181 (30.9232, 164.5367) -> (41.6768, 164.5367)
  line B1182 (31.2843, 62.6999) -> (29.3817, 62.6999)
  line B1183 (34.8649, 57.2167) -> (34.8649, 59.1193)
  line B1184 (34.4431, 59.4902) -> (33.5, 59.4902)
  line B1185 (31.6552, 61.335) -> (31.6552, 62.2781)
  line B1186 (34.9728, 59.7504) -> (33.5, 59.7504)
  line B1187 (31.9154, 61.335) -> (31.9154, 62.8078)
  line B1188 (30.8603, 163.2868) -> (30.8603, 158.9231)
  line B1189 (41.7397, 158.9231) -> (41.7397, 163.2868)
  line B1190 (32.0231, 157.7603) -> (40.5769, 157.7603)
  line B1191 (43.4248, 163.2868) -> (43.4248, 156.9754)
  line B1192 (32.0996, 157.9909) -> (40.5004, 157.9909)
  line B1193 (43.5782, 156.7067) -> (43.325, 156.8755)
  line B1194 (43.325, 143.1245) -> (43.5782, 143.2933)
  line B1195 (43.678, 83.1933) -> (43.4248, 83.0246)
  line B1196 (43.4248, 96.9754) -> (43.678, 96.8067)
  line B1197 (43.6932, 96.5069) -> (43.6932, 83.4931)
  line B1198 (44.0289, 163.665) -> (43.7576, 168.8412)
  line B1199 (44.0289, 56.35) -> (44.0289, 163.665)
  line B1200 (43.7273, 170.0741) -> (43.7196, 170.3272)
  line B1201 (31.6, 163.6001) -> (31.6, 163.0683)
  line B1202 (31.6, 163.0683) -> (31.5817, 163.05)
  line B1203 (31.5817, 163.05) -> (31.5817, 159.55)
  line B1204 (31.5817, 159.55) -> (31.6, 159.5317)
  line B1205 (31.6, 159.5317) -> (31.6, 158.4911)
  line B1206 (41, 159.5317) -> (41.0183, 159.55)
  line B1207 (41.0183, 159.55) -> (41.0183, 163.05)
  line B1208 (41.0183, 163.05) -> (41, 163.0683)
  line B1209 (41, 163.0683) -> (41, 163.6001)
  line B1210 (41, 158.4911) -> (41, 159.5317)
  line B1211 (40.5001, 164.1) -> (32.0999, 164.1)
  line B1212 (64.5339, 164.1031) -> (64.5339, 143.1612)
  line B1213 (64.2538, 169.4466) -> (64.5339, 164.1031)
  line B1214 (64.2418, 173.1906) -> (64.2363, 170.2965)
  line B1215 (31.852, 163.0683) -> (31.852, 159.5317)
  line B1216 (40.748, 159.5317) -> (40.748, 163.0683)
  line B1217 (41, 159.5317) -> (40.748, 159.5317)
  line B1218 (40.748, 163.0683) -> (41, 163.0683)
  line B1219 (31.6, 163.0683) -> (31.852, 163.0683)
  line B1220 (31.852, 159.5317) -> (31.6, 159.5317)
  line B1221 (56.307, 172.8235) -> (51.493, 172.8235)
  line B1222 (51.493, 172.8235) -> (51.4561, 172.254)
  line B1223 (51.4349, 172.0817) -> (51.4, 172)
  line B1224 (51.4757, 174.1853) -> (51.4963, 173.0441)
  line B1225 (56.3651, 172.0817) -> (56.4, 172)
  line B1226 (56.307, 172.8235) -> (56.3438, 172.254)
  line B1227 (56.3243, 174.1853) -> (56.3037, 173.0441)
  line B1228 (56.3243, 174.1853) -> (51.4757, 174.1853)
  line B1229 (51.4561, 172.254) -> (56.3438, 172.254)
  line B1230 (56.4, 176) -> (51.4, 176)
  line B1231 (43.5933, 143.4931) -> (43.5933, 156.5069)
  line B1232 (56.4, 172) -> (51.4, 172)
  line B1233 (60.4, 170.5) -> (47.4, 170.5)
  line B1234 (62.7078, 170.3272) -> (62.7132, 173.2214)
  line B1235 (60.4, 173.2214) -> (60.4, 170.5)
  line B1236 (47.4, 170.5) -> (47.4, 173.2214)
  line B1237 (62.7253, 168.8412) -> (43.7576, 168.8412)
  line B1238 (47.4, 172) -> (51.4, 172)
  line B1239 (51.4, 176) -> (47.4, 176)
  line B1240 (60.4, 176) -> (56.4, 176)
  line B1241 (56.4, 172) -> (60.4, 172)
  line B1242 (63.05, 163.7052) -> (62.9966, 163.665)
  line B1243 (62.9966, 163.665) -> (62.7253, 168.8412)
  line B1244 (46.1032, 143.1468) -> (44.5666, 144.6834)
  line B1245 (44.5666, 144.6834) -> (63.05, 144.6834)
  line B1246 (63.05, 144.6834) -> (64.5339, 143.1612)
  line B1247 (64.5342, 143.1468) -> (46.1032, 143.1468)
  line B1248 (63.05, 95.3166) -> (44.5666, 95.3166)
  line B1249 (63.05, 56.35) -> (63.05, 95.3166)
  line B1250 (63.05, 144.6834) -> (63.05, 163.7052)
  line B1251 (44.5666, 95.3166) -> (44.5666, 144.6834)
  line B1252 (46.1032, 143.1468) -> (46.1032, 96.8532)
  line B1253 (46.1032, 96.8532) -> (44.5666, 95.3166)
  line B1254 (64.5339, 96.8388) -> (63.05, 95.3166)
  line B1255 (64.5339, 96.8388) -> (64.5339, 56.35)
  line B1256 (46.1032, 96.8532) -> (64.5342, 96.8532)
  line B1257 (60.875, 98.1915) -> (64.075, 98.1915)
  line B1258 (60.875, 96.869) -> (60.875, 98.1915)
  line B1259 (59.625, 98.1915) -> (59.625, 96.869)
  line B1260 (56.425, 98.1915) -> (59.625, 98.1915)
  line B1261 (56.425, 141.8085) -> (56.425, 98.1915)
  line B1262 (59.625, 141.8085) -> (56.425, 141.8085)
  line B1263 (59.625, 143.131) -> (59.625, 141.8085)
  line B1264 (60.875, 141.8085) -> (60.875, 143.131)
  line B1265 (64.075, 141.8085) -> (60.875, 141.8085)
  line B1266 (64.075, 98.1915) -> (64.075, 141.8085)
  line B1267 (50.625, 141.8085) -> (47.425, 141.8085)
  line B1268 (47.425, 98.1915) -> (50.625, 98.1915)
  line B1269 (50.625, 98.1915) -> (50.625, 96.869)
  line B1270 (47.425, 141.8085) -> (47.425, 98.1915)
  line B1271 (50.625, 143.131) -> (50.625, 141.8085)
  line B1272 (51.875, 98.1915) -> (55.075, 98.1915)
  line B1273 (51.875, 96.869) -> (51.875, 98.1915)
  line B1274 (51.875, 141.8085) -> (51.875, 143.131)
  line B1275 (55.075, 141.8085) -> (51.875, 141.8085)
  line B1276 (55.075, 98.1915) -> (55.075, 141.8085)
  line B1277 (34.75, 117.75) -> (36.25, 117.75)
  line B1278 (36.25, 122.25) -> (34.75, 122.25)
  line B1279 (33.5, 56.35) -> (210.5718, 56.35)
  line B1280 (0.5, 4) -> (0.5, 256)
  line B1281 (448.5, 0) -> (4.5, 0)
  line B1282 (419.5, 183.65) -> (33.5, 183.65)
  line B1283 (28.5, 178.65) -> (28.5, 61.35)
  line B1284 (452.5, 256) -> (452.5, 4)
  line B1285 (242.428, 56.35) -> (419.5, 56.35)
  line B1286 (4.5, 260) -> (448.5, 260)
  line B1287 (424.5, 61.35) -> (424.5, 178.65)
  line B1288 (389.5342, 96.8532) -> (64.5342, 96.8532)
  line B1289 (64.5342, 143.1468) -> (389.5342, 143.1468)
  line B1290 (424.5, 156.9886) -> (410.0745, 156.9886)
  line B1291 (410.0745, 56.35) -> (410.0745, 83.0114)
  line B1292 (410.0745, 96.8887) -> (424.5, 96.8887)
  line B1293 (424.5, 83.1113) -> (410.0745, 83.1113)
  line B1294 (410.0745, 143.0114) -> (424.5, 143.0114)
  line B1295 (42.9255, 83.0114) -> (28.5, 83.0114)
  line B1296 (28.5, 96.9886) -> (42.9255, 96.9886)
  line B1297 (28.5, 143.1113) -> (42.9255, 143.1113)
  line B1298 (42.9255, 156.8887) -> (28.5, 156.8887)
  arc B1299 (420.368, 56.83) -> (424.005, 60.467) centre (419.5, 61.335) ccw
  arc B1300 (419.5, 57.2269) -> (423.6081, 61.335) centre (419.5, 61.335) ccw
  arc B1301 (419.5, 59.4902) -> (421.3448, 61.335) centre (419.5, 61.335) ccw
  arc B1302 (419.5, 59.7504) -> (421.0846, 61.335) centre (419.5, 61.335) ccw
  arc B1303 (410.0601, 164.1797) -> (409.5607, 163.7332) centre (410.0477, 163.6911) ccw
  circle B1304 centre (417.5, 120) radius 5.4683
  arc B1305 (409.5752, 96.9754) -> (409.675, 96.8755) centre (409.6753, 96.9756) ccw
  circle B1306 centre (416.7, 161.3) radius 1.6
  arc B1307 (418.25, 117.6627) -> (418.25, 122.3373) centre (418.25, 120) ccw
  arc B1308 (416.75, 122.3373) -> (416.75, 117.6627) centre (416.7504, 120) ccw
  arc B1309 (28.9949, 60.467) -> (32.632, 56.83) centre (33.5, 61.335) ccw
  arc B1310 (29.3919, 61.335) -> (33.5, 57.2269) centre (33.5, 61.335) ccw
  arc B1311 (31.6552, 61.335) -> (33.5, 59.4902) centre (33.5, 61.335) ccw
  arc B1312 (31.9154, 61.335) -> (33.5, 59.7504) centre (33.5, 61.335) ccw
  circle B1313 centre (35.5, 120) radius 5.4683
  arc B1314 (43.325, 156.8755) -> (43.4248, 156.9754) centre (43.3247, 156.9756) ccw
  circle B1315 centre (36.3, 161.3) radius 1.6
  arc B1316 (34.75, 122.25) -> (34.75, 117.75) centre (34.7505, 120) ccw
  arc B1317 (36.25, 117.75) -> (36.25, 122.25) centre (36.25, 120) ccw
  arc B1318 (211.8983, 55.3367) -> (210.5718, 56.35) centre (210.4662, 54.8369) ccw
  arc B1319 (242.428, 56.35) -> (241.1018, 55.3368) centre (242.5336, 54.8372) ccw
  arc B1320 (448.5, 0) -> (452.5, 4) centre (448.5, 4) ccw
  arc B1321 (4.5, 260) -> (0.5, 256) centre (4.5, 256) ccw
  arc B1322 (452.5, 256) -> (448.5, 260) centre (448.5, 256) ccw
  arc B1323 (424.5, 178.65) -> (419.5, 183.65) centre (419.5, 178.65) ccw
  arc B1324 (0.5, 4) -> (4.5, 0) centre (4.5, 4) ccw
  arc B1325 (33.5, 183.65) -> (28.5, 178.65) centre (33.5, 178.65) ccw
  arc B1326 (419.5, 56.35) -> (424.5, 61.35) centre (419.5, 61.35) ccw
  arc B1327 (28.5, 61.35) -> (33.5, 56.35) centre (33.5, 61.35) ccw
  ellipse B1328 centre (422.3598, 173.6) end of major axis (422.3598, 184.15) minor radius 0.5529 (422.0768, 164.5367) -> (422.1109, 164.1797) ccw
  ellipse B1329 centre (411.0402, 173.6) end of major axis (411.0402, 184.15) minor radius 0.5529 (411.2891, 164.1797) -> (411.3232, 164.5367) ccw
  ellipse B1330 centre (421.751, 62.238) end of major axis (421.6145, 62.6849) minor radius 0.4 (421.7157, 62.6999) -> (421.3448, 62.2781) ccw
  ellipse B1331 centre (418.5969, 59.084) end of major axis (418.1501, 59.2205) minor radius 0.4 (418.5568, 59.4902) -> (418.1351, 59.1193) ccw
  ellipse B1332 centre (418.0773, 59.2427) end of major axis (417.5188, 59.4133) minor radius 0.5 (418.0272, 59.7504) -> (417.5, 59.2868) ccw
  ellipse B1333 centre (421.5923, 62.7576) end of major axis (421.4217, 63.3162) minor radius 0.5 (421.5482, 63.335) -> (421.0846, 62.8078) ccw
  ellipse B1334 centre (422.0873, 163.2868) end of major axis (422.0873, 164.2868) minor radius 0.0524 (422.1397, 163.2868) -> (422.1109, 164.1797) ccw
  ellipse B1335 centre (411.3127, 163.2868) end of major axis (411.3127, 164.2868) minor radius 0.0524 (411.2891, 164.1797) -> (411.2603, 163.2868) ccw
  ellipse B1336 centre (410.0745, 156.9747) end of major axis (410.5745, 156.9747) minor radius 0.014 (410.0745, 156.9886) -> (409.5752, 156.9754) ccw
  ellipse B1337 centre (409.5489, 163.2868) end of major axis (409.5489, 163.7868) minor radius 0.0262 (409.5752, 163.2868) -> (409.5607, 163.7332) ccw
  ellipse B1338 centre (410.0745, 143.0253) end of major axis (409.5745, 143.0253) minor radius 0.014 (409.5752, 143.0246) -> (410.0745, 143.0114) ccw
  ellipse B1339 centre (410.0745, 96.8747) end of major axis (410.4745, 96.8747) minor radius 0.014 (410.0745, 96.8887) -> (409.675, 96.8755) ccw
  ellipse B1340 centre (410.0745, 83.1253) end of major axis (409.6745, 83.1253) minor radius 0.014 (409.675, 83.1245) -> (410.0745, 83.1113) ccw
  ellipse B1341 centre (409.1683, 170.2555) end of major axis (409.1683, 172.2555) minor radius 0.1048 (409.2424, 168.8412) -> (409.2726, 170.0741) ccw
  ellipse B1342 centre (409.8215, 173.6) end of major axis (409.8215, 184.65) minor radius 0.5791 (409.2726, 170.0741) -> (409.5607, 163.7332) ccw
  ellipse B1343 centre (409.3225, 156.5069) end of major axis (409.3225, 156.8069) minor radius 0.0157 (409.3219, 156.8067) -> (409.3068, 156.5069) ccw
  ellipse B1344 centre (409.3225, 143.4931) end of major axis (409.3225, 143.7931) minor radius 0.0157 (409.3068, 143.4931) -> (409.3219, 143.1933) ccw
  ellipse B1345 centre (420.8999, 158.4916) end of major axis (420.7417, 158.9667) minor radius 0.5 (420.9004, 157.9909) -> (421.4, 158.4911) ccw
  ellipse B1346 centre (420.8999, 163.5999) end of major axis (421.2536, 163.9536) minor radius 0.5 (421.4, 163.6001) -> (420.9001, 164.1) ccw
  ellipse B1347 centre (412.5001, 163.5999) end of major axis (412.1464, 163.9536) minor radius 0.5 (412.4999, 164.1) -> (412, 163.6001) ccw
  ellipse B1348 centre (412.5001, 158.4916) end of major axis (412.6583, 158.9667) minor radius 0.5 (412, 158.4911) -> (412.4996, 157.9909) ccw
  ellipse B1349 centre (396.6361, 173.9248) end of major axis (396.6361, 174.7248) minor radius 0.0419 (396.6757, 174.1853) -> (396.6615, 174.5606) ccw
  ellipse B1350 centre (396.6864, 172.9789) end of major axis (396.6864, 173.1789) minor radius 0.0105 (396.693, 172.8235) -> (396.6963, 173.0441) ccw
  ellipse B1351 centre (396.6298, 172.8758) end of major axis (396.6298, 173.6758) minor radius 0.0419 (396.6349, 172.0817) -> (396.6561, 172.254) ccw
  ellipse B1352 centre (396.7887, 177.7397) end of major axis (396.7887, 181.7397) minor radius 0.2096 (396.6, 176) -> (396.6615, 174.5606) ccw
  ellipse B1353 centre (401.5639, 173.9248) end of major axis (401.5639, 174.7248) minor radius 0.0419 (401.5384, 174.5606) -> (401.5242, 174.1853) ccw
  ellipse B1354 centre (401.4112, 177.7397) end of major axis (401.4112, 181.7397) minor radius 0.2096 (401.5384, 174.5606) -> (401.6, 176) ccw
  ellipse B1355 centre (401.5702, 172.8758) end of major axis (401.5702, 173.6758) minor radius 0.0419 (401.5438, 172.254) -> (401.5651, 172.0817) ccw
  ellipse B1356 centre (401.5136, 172.9789) end of major axis (401.5136, 173.1789) minor radius 0.0105 (401.5037, 173.0441) -> (401.507, 172.8235) ccw
  ellipse B1357 centre (409.4224, 83.4931) end of major axis (409.4224, 83.6931) minor radius 0.0157 (409.4066, 83.4931) -> (409.4218, 83.2933) ccw
  ellipse B1358 centre (409.4224, 96.5069) end of major axis (409.4224, 96.7069) minor radius 0.0157 (409.4218, 96.7067) -> (409.4066, 96.5069) ccw
  ellipse B1359 centre (41.9598, 173.6) end of major axis (41.9598, 184.15) minor radius 0.5529 (41.6768, 164.5367) -> (41.7109, 164.1797) ccw
  ellipse B1360 centre (30.6402, 173.6) end of major axis (30.6402, 184.15) minor radius 0.5529 (30.8891, 164.1797) -> (30.9232, 164.5367) ccw
  ellipse B1361 centre (31.249, 62.238) end of major axis (31.3855, 62.6849) minor radius 0.4 (31.6552, 62.2781) -> (31.2843, 62.6999) ccw
  ellipse B1362 centre (34.403, 59.084) end of major axis (34.8499, 59.2205) minor radius 0.4 (34.8649, 59.1193) -> (34.4431, 59.4902) ccw
  ellipse B1363 centre (31.4077, 62.7576) end of major axis (31.5783, 63.3162) minor radius 0.5 (31.9154, 62.8078) -> (31.4518, 63.335) ccw
  ellipse B1364 centre (34.9226, 59.2427) end of major axis (35.4812, 59.4133) minor radius 0.5 (35.5, 59.2868) -> (34.9728, 59.7504) ccw
  ellipse B1365 centre (30.9127, 163.2868) end of major axis (30.9127, 164.2868) minor radius 0.0524 (30.8891, 164.1797) -> (30.8603, 163.2868) ccw
  ellipse B1366 centre (41.6873, 163.2868) end of major axis (41.6873, 164.2868) minor radius 0.0524 (41.7397, 163.2868) -> (41.7109, 164.1797) ccw
  ellipse B1367 centre (43.451, 163.2868) end of major axis (43.451, 163.7868) minor radius 0.0262 (43.4392, 163.7332) -> (43.4248, 163.2868) ccw
  ellipse B1368 centre (42.9255, 83.0253) end of major axis (43.4255, 83.0253) minor radius 0.014 (42.9255, 83.0114) -> (43.4248, 83.0246) ccw
  ellipse B1369 centre (42.9255, 96.9747) end of major axis (42.4255, 96.9747) minor radius 0.014 (43.4248, 96.9754) -> (42.9255, 96.9886) ccw
  ellipse B1370 centre (42.9255, 143.1253) end of major axis (43.3255, 143.1253) minor radius 0.014 (42.9255, 143.1113) -> (43.325, 143.1245) ccw
  ellipse B1371 centre (42.9255, 156.8747) end of major axis (42.5255, 156.8747) minor radius 0.014 (43.325, 156.8755) -> (42.9255, 156.8887) ccw
  ellipse B1372 centre (43.6775, 96.5069) end of major axis (43.6775, 96.8069) minor radius 0.0157 (43.6932, 96.5069) -> (43.678, 96.8067) ccw
  ellipse B1373 centre (43.1785, 173.6) end of major axis (43.1785, 184.65) minor radius 0.5791 (43.4392, 163.7332) -> (43.7273, 170.0741) ccw
  ellipse B1374 centre (43.8317, 170.2555) end of major axis (43.8317, 172.2555) minor radius 0.1048 (43.7273, 170.0741) -> (43.7576, 168.8412) ccw
  ellipse B1375 centre (43.6775, 83.4931) end of major axis (43.6775, 83.7931) minor radius 0.0157 (43.678, 83.1933) -> (43.6932, 83.4931) ccw
  ellipse B1376 centre (32.1001, 158.4916) end of major axis (32.2583, 158.9667) minor radius 0.5 (31.6, 158.4911) -> (32.0996, 157.9909) ccw
  ellipse B1377 centre (40.4999, 158.4916) end of major axis (40.3417, 158.9667) minor radius 0.5 (40.5004, 157.9909) -> (41, 158.4911) ccw
  ellipse B1378 centre (32.1001, 163.5999) end of major axis (31.7464, 163.9536) minor radius 0.5 (32.0999, 164.1) -> (31.6, 163.6001) ccw
  ellipse B1379 centre (40.4999, 163.5999) end of major axis (40.8536, 163.9536) minor radius 0.5 (41, 163.6001) -> (40.5001, 164.1) ccw
  ellipse B1380 centre (51.4864, 172.9789) end of major axis (51.4864, 173.1789) minor radius 0.0105 (51.493, 172.8235) -> (51.4963, 173.0441) ccw
  ellipse B1381 centre (56.3136, 172.9789) end of major axis (56.3136, 173.1789) minor radius 0.0105 (56.3037, 173.0441) -> (56.307, 172.8235) ccw
  ellipse B1382 centre (51.4298, 172.8758) end of major axis (51.4298, 173.6758) minor radius 0.0419 (51.4349, 172.0817) -> (51.4561, 172.254) ccw
  ellipse B1383 centre (51.5888, 177.7397) end of major axis (51.5888, 181.7397) minor radius 0.2096 (51.4, 176) -> (51.4615, 174.5606) ccw
  ellipse B1384 centre (51.4361, 173.9248) end of major axis (51.4361, 174.7248) minor radius 0.0419 (51.4757, 174.1853) -> (51.4615, 174.5606) ccw
  ellipse B1385 centre (56.3702, 172.8758) end of major axis (56.3702, 173.6758) minor radius 0.0419 (56.3438, 172.254) -> (56.3651, 172.0817) ccw
  ellipse B1386 centre (56.3639, 173.9248) end of major axis (56.3639, 174.7248) minor radius 0.0419 (56.3384, 174.5606) -> (56.3243, 174.1853) ccw
  ellipse B1387 centre (56.2112, 177.7397) end of major axis (56.2112, 181.7397) minor radius 0.2096 (56.3384, 174.5606) -> (56.4, 176) ccw
  ellipse B1388 centre (43.5776, 143.4931) end of major axis (43.5776, 143.6931) minor radius 0.0157 (43.5782, 143.2933) -> (43.5933, 143.4931) ccw
  ellipse B1389 centre (43.5776, 156.5069) end of major axis (43.5776, 156.7069) minor radius 0.0157 (43.5933, 156.5069) -> (43.5782, 156.7067) ccw
  spline B1390 degree 3 poles (424.029, 60.8061) (424.0295, 60.8022) (424.0327, 60.7764) (424.0345, 60.7115) (424.0269, 60.5958) (424.0123, 60.5098) (424.005, 60.467) knots 0 0 0 0 0.056474 0.369913 0.685771 1 1 1 1
  spline B1391 degree 3 poles (420.368, 56.83) (420.3595, 56.8284) (420.3091, 56.8189) (420.2166, 56.8063) (420.1036, 56.7998) (420.0538, 56.8039) (420.0288, 56.806) knots 0 0 0 0 0.062947 0.372592 0.68524 1 1 1 1
  spline B1392 degree 3 poles (420.0288, 56.806) (419.9961, 56.8105) (419.8194, 56.835) (419.6434, 56.8745) (419.5, 56.9067) knots 0 0 0 0 0.185228 1 1 1 1
  spline B1393 degree 3 poles (423.9282, 61.335) (423.9362, 61.3024) (423.9789, 61.1267) (424.0065, 60.9501) (424.029, 60.8061) knots 0 0 0 0 0.18523 1 1 1 1
  spline B1394 degree 3 poles (390.2868, 173.2214) (390.2894, 174.2281) (390.2947, 176.2418) (390.3637, 179.044) (390.4655, 181.3541) (390.5553, 182.3772) (390.5972, 183.65) knots 0 0 0 0 0.25789 0.515836 0.773884 1 1 1 1
  spline B1395 degree 3 poles (412.4231, 157.7603) (412.2925, 157.7731) (412.0312, 157.7988) (411.6828, 157.9991) (411.4199, 158.2939) (411.2803, 158.6209) (411.266, 158.8371) (411.2603, 158.9231) knots 0 0 0 0 0.214547 0.429106 0.643794 0.858332 1 1 1 1
  spline B1396 degree 3 poles (422.1397, 158.9231) (422.1268, 158.7925) (422.1012, 158.5312) (421.9009, 158.1829) (421.6061, 157.9199) (421.2791, 157.7803) (421.0629, 157.766) (420.9769, 157.7603) knots 0 0 0 0 0.214545 0.429103 0.643792 0.858332 1 1 1 1
  spline B1397 degree 3 poles (409.742, 173.2214) (409.7406, 173.2147) (409.5834, 172.4857) (409.3682, 171.5275) (409.2973, 170.5587) (409.2803, 170.3272) knots 0 0 0 0 0.006999 0.762692 1 1 1 1
  spline B1398 degree 3 poles (389.0081, 183.65) (388.9833, 182.4861) (388.9032, 181.2929) (388.8184, 178.8443) (388.7639, 176.0999) (388.7601, 174.1603) (388.7582, 173.1906) knots 0 0 0 0 0.250108 0.500131 0.750084 1 1 1 1
  spline B1399 degree 3 poles (388.7637, 170.2965) (388.7636, 170.2181) (388.7634, 170.0612) (388.7599, 169.8342) (388.7543, 169.6225) (388.7489, 169.5052) (388.7461, 169.4466) knots 0 0 0 0 0.249943 0.499907 0.749921 1 1 1 1
  spline B1400 degree 3 poles (390.2747, 168.8412) (390.2775, 168.9462) (390.2829, 169.1515) (390.2885, 169.5225) (390.2919, 169.9166) (390.2921, 170.1909) (390.2922, 170.3272) knots 0 0 0 0 0.255599 0.500029 0.751497 1 1 1 1
  spline B1401 degree 3 poles (28.971, 60.8061) (28.9705, 60.8022) (28.9673, 60.7764) (28.9655, 60.7115) (28.973, 60.5958) (28.9877, 60.5098) (28.9949, 60.467) knots 0 0 0 0 0.056474 0.369913 0.685771 1 1 1 1
  spline B1402 degree 3 poles (32.632, 56.83) (32.6405, 56.8284) (32.6909, 56.8189) (32.7834, 56.8063) (32.8964, 56.7998) (32.9462, 56.8039) (32.9711, 56.806) knots 0 0 0 0 0.062947 0.372592 0.68524 1 1 1 1
  spline B1403 degree 3 poles (29.0717, 61.335) (29.0638, 61.3024) (29.021, 61.1267) (28.9934, 60.9501) (28.971, 60.8061) knots 0 0 0 0 0.18523 1 1 1 1
  spline B1404 degree 3 poles (32.9711, 56.806) (33.0039, 56.8105) (33.1806, 56.835) (33.3566, 56.8745) (33.5, 56.9067) knots 0 0 0 0 0.185228 1 1 1 1
  spline B1405 degree 3 poles (62.7132, 173.2214) (62.7105, 174.2281) (62.7052, 176.2418) (62.6363, 179.044) (62.5345, 181.3541) (62.4447, 182.3772) (62.4027, 183.65) knots 0 0 0 0 0.25789 0.515836 0.773884 1 1 1 1
  spline B1406 degree 3 poles (30.8603, 158.9231) (30.8731, 158.7925) (30.8988, 158.5312) (31.0991, 158.1829) (31.3939, 157.9199) (31.7209, 157.7803) (31.9371, 157.766) (32.0231, 157.7603) knots 0 0 0 0 0.214545 0.429103 0.643792 0.858332 1 1 1 1
  spline B1407 degree 3 poles (40.5769, 157.7603) (40.7075, 157.7731) (40.9688, 157.7988) (41.3171, 157.9991) (41.5801, 158.2939) (41.7197, 158.6209) (41.734, 158.8371) (41.7397, 158.9231) knots 0 0 0 0 0.214547 0.429106 0.643794 0.858332 1 1 1 1
  spline B1408 degree 3 poles (43.2579, 173.2214) (43.2594, 173.2147) (43.4166, 172.4857) (43.6317, 171.5275) (43.7027, 170.5587) (43.7196, 170.3272) knots 0 0 0 0 0.006999 0.762692 1 1 1 1
  spline B1409 degree 3 poles (63.9765, 183.65) (64.0166, 182.4861) (64.0968, 181.2929) (64.1816, 178.8443) (64.2361, 176.0999) (64.2399, 174.1603) (64.2418, 173.1906) knots 0 0 0 0 0.250108 0.500131 0.750084 1 1 1 1
  spline B1410 degree 3 poles (64.2363, 170.2965) (64.2364, 170.2181) (64.2366, 170.0612) (64.2401, 169.8342) (64.2456, 169.6225) (64.2511, 169.5052) (64.2538, 169.4466) knots 0 0 0 0 0.249943 0.499907 0.749921 1 1 1 1
  spline B1411 degree 3 poles (62.7253, 168.8412) (62.7225, 168.9462) (62.717, 169.1515) (62.7115, 169.5225) (62.708, 169.9166) (62.7078, 170.1909) (62.7078, 170.3272) knots 0 0 0 0 0.255599 0.500029 0.751497 1 1 1 1
  spline B1412 degree 3 poles (211.8983, 55.3367) (212.3341, 54.7751) (212.7969, 54.2386) (213.7832, 53.2214) (214.3088, 52.7389) (215.4006, 51.8424) (215.9677, 51.4265) (217.1438, 50.6586) (217.7529, 50.3068) (219.0124, 49.6662) (219.665, 49.3777) (220.9852, 48.879) (221.6559, 48.6666) (223.0201, 48.32) (223.7141, 48.186) (225.1262, 48.0069) (225.8292, 47.9635) (227.9295, 47.9673) (229.3179, 48.1491) (232.0726, 48.8548) (233.3841, 49.3578) (235.2612, 50.3151) (235.8719, 50.668) (237.061, 51.4468) (237.6288, 51.8654) (238.7125, 52.7583) (239.2283, 53.2329) (240.2052, 54.2414) (240.6661, 54.7754) (241.1018, 55.3368) knots 0 0 0 0 0.0625 0.0625 0.125 0.125 0.1875 0.1875 0.25 0.25 0.3125 0.3125 0.375 0.375 0.4375 0.4375 0.5 0.5 0.625 0.625 0.75 0.75 0.8125 0.8125 0.875 0.875 0.9375 0.9375 1 1 1 1
  spline B1413 degree 3 poles (210.5718, 56.35) (211.0672, 56.35) (211.5861, 56.35) (212.6765, 56.35) (213.248, 56.35) (214.4428, 56.35) (215.066, 56.35) (216.3644, 56.35) (217.0328, 56.35) (219.0751, 56.35) (220.4931, 56.35) (222.3434, 56.35) (222.7187, 56.35) (223.4711, 56.35) (223.8473, 56.35) (224.9762, 56.35) (226.4819, 56.35) (227.9885, 56.35) (229.4957, 56.35) (230.2539, 56.35) (232.4755, 56.35) (233.9, 56.35) (235.6153, 56.35) (235.9559, 56.35) (236.6249, 56.35) (236.9533, 56.35) (237.9207, 56.35) (238.542, 56.35) (239.7368, 56.35) (240.3102, 56.35) (241.4075, 56.35) (241.9319, 56.35) (242.428, 56.35) knots 0 0 0 0 0.0625 0.0625 0.125 0.125 0.1875 0.1875 0.25 0.25 0.375 0.375 0.40625 0.40625 0.4375 0.4375 0.5 0.5625 0.5625 0.625 0.625 0.75 0.75 0.78125 0.78125 0.8125 0.8125 0.875 0.875 0.9375 0.9375 1 1 1 1
  line B1414 (829.0121, 239.3951) -> (741.0121, 239.3951)
  line B1415 (740.0121, 238.3951) -> (740.0121, 20.3951)
  line B1416 (741.0121, 19.3951) -> (829.0121, 19.3951)
  line B1417 (837.0121, -0.6049) -> (829.0121, -0.6049)
  line B1418 (837.0121, 259.3951) -> (829.0121, 259.3951)
  line B1419 (839.0121, 3.3951) -> (839.0121, 255.3951)
  line B1420 (839.0121, 1.3951) -> (839.0121, 3.3951)
  line B1421 (839.0121, 255.3951) -> (839.0121, 257.3951)
  line B1422 (829.0121, -0.6049) -> (829.0121, 259.3951)
  arc B1423 (741.0121, 239.3951) -> (740.0121, 238.3951) centre (741.0121, 238.3951) ccw
  arc B1424 (740.0121, 20.3951) -> (740.3506, 19.6451) centre (741.0121, 20.3951) ccw
  arc B1425 (740.5121, 19.5291) -> (741.0121, 19.3951) centre (741.0121, 20.3951) ccw
  arc B1426 (837.0121, -0.6049) -> (839.0121, 1.3951) centre (837.0121, 1.3951) ccw
  arc B1427 (839.0121, 257.3951) -> (837.0121, 259.3951) centre (837.0121, 257.3951) ccw
  circle B1428 centre (770.0121, 179.3951) radius 13
  circle B1429 centre (770.0121, 79.3951) radius 13
sketch_block_instance "块6-2"
sketch_block "块6"
sketch_block_instance "块9-2"
sketch_block "块9"
sketch_block_instance "块7-2"
sketch_block "块7"
sketch_block_instance "块8-2"
sketch_block "块8"
